VERSION 5.8 ;
BUSBITCHARS "[]" ;
DIVIDERCHAR "/" ;
UNITS
    DATABASE MICRONS 1000 ;
END UNITS

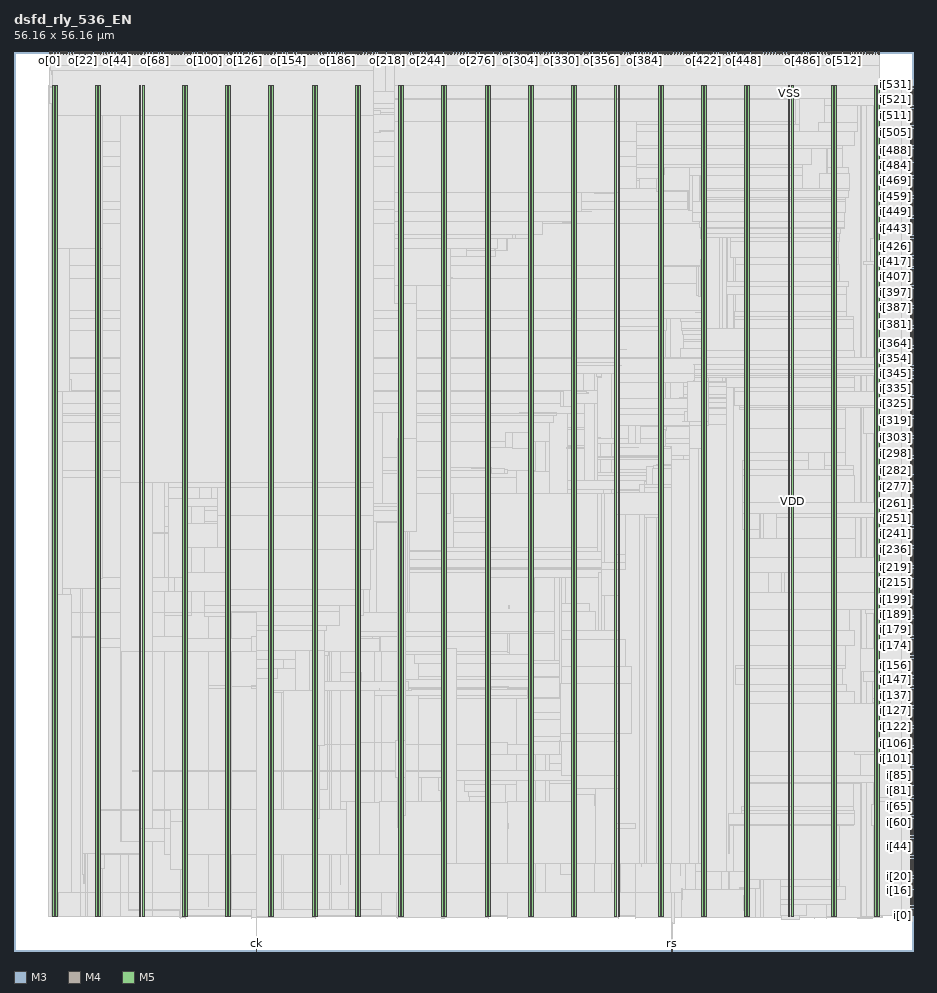
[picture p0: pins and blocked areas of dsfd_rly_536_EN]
MACRO dsfd_rly_536_EN
  FOREIGN dsfd_rly_536_EN 0 0 ;
  CLASS BLOCK ;
  SIZE 56.16 BY 56.16 ;
  PIN ck
    DIRECTION INPUT ;
    USE SIGNAL ;
    PORT
      LAYER M3 ;
        RECT  15.12 0 15.138 0.144 ;
    END
  END ck
  PIN i[0]
    DIRECTION INPUT ;
    USE SIGNAL ;
    PORT
      LAYER M4 ;
        RECT  55.968 2.208 56.16 2.232 ;
    END
  END i[0]
  PIN i[100]
    DIRECTION INPUT ;
    USE SIGNAL ;
    PORT
      LAYER M4 ;
        RECT  55.968 11.904 56.16 11.928 ;
    END
  END i[100]
  PIN i[101]
    DIRECTION INPUT ;
    USE SIGNAL ;
    PORT
      LAYER M4 ;
        RECT  55.968 12 56.16 12.024 ;
    END
  END i[101]
  PIN i[102]
    DIRECTION INPUT ;
    USE SIGNAL ;
    PORT
      LAYER M4 ;
        RECT  55.968 12.096 56.16 12.12 ;
    END
  END i[102]
  PIN i[103]
    DIRECTION INPUT ;
    USE SIGNAL ;
    PORT
      LAYER M4 ;
        RECT  55.968 12.192 56.16 12.216 ;
    END
  END i[103]
  PIN i[104]
    DIRECTION INPUT ;
    USE SIGNAL ;
    PORT
      LAYER M4 ;
        RECT  55.968 12.288 56.16 12.312 ;
    END
  END i[104]
  PIN i[105]
    DIRECTION INPUT ;
    USE SIGNAL ;
    PORT
      LAYER M4 ;
        RECT  55.968 12.384 56.16 12.408 ;
    END
  END i[105]
  PIN i[106]
    DIRECTION INPUT ;
    USE SIGNAL ;
    PORT
      LAYER M4 ;
        RECT  55.968 12.48 56.16 12.504 ;
    END
  END i[106]
  PIN i[107]
    DIRECTION INPUT ;
    USE SIGNAL ;
    PORT
      LAYER M4 ;
        RECT  55.968 12.576 56.16 12.6 ;
    END
  END i[107]
  PIN i[108]
    DIRECTION INPUT ;
    USE SIGNAL ;
    PORT
      LAYER M4 ;
        RECT  55.968 12.672 56.16 12.696 ;
    END
  END i[108]
  PIN i[109]
    DIRECTION INPUT ;
    USE SIGNAL ;
    PORT
      LAYER M4 ;
        RECT  55.968 12.768 56.16 12.792 ;
    END
  END i[109]
  PIN i[10]
    DIRECTION INPUT ;
    USE SIGNAL ;
    PORT
      LAYER M4 ;
        RECT  55.968 3.168 56.16 3.192 ;
    END
  END i[10]
  PIN i[110]
    DIRECTION INPUT ;
    USE SIGNAL ;
    PORT
      LAYER M4 ;
        RECT  55.968 12.864 56.16 12.888 ;
    END
  END i[110]
  PIN i[111]
    DIRECTION INPUT ;
    USE SIGNAL ;
    PORT
      LAYER M4 ;
        RECT  55.968 12.96 56.16 12.984 ;
    END
  END i[111]
  PIN i[112]
    DIRECTION INPUT ;
    USE SIGNAL ;
    PORT
      LAYER M4 ;
        RECT  55.968 13.056 56.16 13.08 ;
    END
  END i[112]
  PIN i[113]
    DIRECTION INPUT ;
    USE SIGNAL ;
    PORT
      LAYER M4 ;
        RECT  55.968 13.152 56.16 13.176 ;
    END
  END i[113]
  PIN i[114]
    DIRECTION INPUT ;
    USE SIGNAL ;
    PORT
      LAYER M4 ;
        RECT  55.968 13.248 56.16 13.272 ;
    END
  END i[114]
  PIN i[115]
    DIRECTION INPUT ;
    USE SIGNAL ;
    PORT
      LAYER M4 ;
        RECT  55.968 13.344 56.16 13.368 ;
    END
  END i[115]
  PIN i[116]
    DIRECTION INPUT ;
    USE SIGNAL ;
    PORT
      LAYER M4 ;
        RECT  55.968 13.44 56.16 13.464 ;
    END
  END i[116]
  PIN i[117]
    DIRECTION INPUT ;
    USE SIGNAL ;
    PORT
      LAYER M4 ;
        RECT  55.968 13.536 56.16 13.56 ;
    END
  END i[117]
  PIN i[118]
    DIRECTION INPUT ;
    USE SIGNAL ;
    PORT
      LAYER M4 ;
        RECT  55.968 13.632 56.16 13.656 ;
    END
  END i[118]
  PIN i[119]
    DIRECTION INPUT ;
    USE SIGNAL ;
    PORT
      LAYER M4 ;
        RECT  55.968 13.728 56.16 13.752 ;
    END
  END i[119]
  PIN i[11]
    DIRECTION INPUT ;
    USE SIGNAL ;
    PORT
      LAYER M4 ;
        RECT  55.968 3.264 56.16 3.288 ;
    END
  END i[11]
  PIN i[120]
    DIRECTION INPUT ;
    USE SIGNAL ;
    PORT
      LAYER M4 ;
        RECT  55.968 13.824 56.16 13.848 ;
    END
  END i[120]
  PIN i[121]
    DIRECTION INPUT ;
    USE SIGNAL ;
    PORT
      LAYER M4 ;
        RECT  55.968 13.92 56.16 13.944 ;
    END
  END i[121]
  PIN i[122]
    DIRECTION INPUT ;
    USE SIGNAL ;
    PORT
      LAYER M4 ;
        RECT  55.968 14.016 56.16 14.04 ;
    END
  END i[122]
  PIN i[123]
    DIRECTION INPUT ;
    USE SIGNAL ;
    PORT
      LAYER M4 ;
        RECT  55.968 14.112 56.16 14.136 ;
    END
  END i[123]
  PIN i[124]
    DIRECTION INPUT ;
    USE SIGNAL ;
    PORT
      LAYER M4 ;
        RECT  55.968 14.208 56.16 14.232 ;
    END
  END i[124]
  PIN i[125]
    DIRECTION INPUT ;
    USE SIGNAL ;
    PORT
      LAYER M4 ;
        RECT  55.968 14.304 56.16 14.328 ;
    END
  END i[125]
  PIN i[126]
    DIRECTION INPUT ;
    USE SIGNAL ;
    PORT
      LAYER M4 ;
        RECT  55.968 14.4 56.16 14.424 ;
    END
  END i[126]
  PIN i[127]
    DIRECTION INPUT ;
    USE SIGNAL ;
    PORT
      LAYER M4 ;
        RECT  55.968 14.496 56.16 14.52 ;
    END
  END i[127]
  PIN i[128]
    DIRECTION INPUT ;
    USE SIGNAL ;
    PORT
      LAYER M4 ;
        RECT  55.968 14.592 56.16 14.616 ;
    END
  END i[128]
  PIN i[129]
    DIRECTION INPUT ;
    USE SIGNAL ;
    PORT
      LAYER M4 ;
        RECT  55.968 14.688 56.16 14.712 ;
    END
  END i[129]
  PIN i[12]
    DIRECTION INPUT ;
    USE SIGNAL ;
    PORT
      LAYER M4 ;
        RECT  55.968 3.36 56.16 3.384 ;
    END
  END i[12]
  PIN i[130]
    DIRECTION INPUT ;
    USE SIGNAL ;
    PORT
      LAYER M4 ;
        RECT  55.968 14.784 56.16 14.808 ;
    END
  END i[130]
  PIN i[131]
    DIRECTION INPUT ;
    USE SIGNAL ;
    PORT
      LAYER M4 ;
        RECT  55.968 14.88 56.16 14.904 ;
    END
  END i[131]
  PIN i[132]
    DIRECTION INPUT ;
    USE SIGNAL ;
    PORT
      LAYER M4 ;
        RECT  55.968 14.976 56.16 15 ;
    END
  END i[132]
  PIN i[133]
    DIRECTION INPUT ;
    USE SIGNAL ;
    PORT
      LAYER M4 ;
        RECT  55.968 15.072 56.16 15.096 ;
    END
  END i[133]
  PIN i[134]
    DIRECTION INPUT ;
    USE SIGNAL ;
    PORT
      LAYER M4 ;
        RECT  55.968 15.168 56.16 15.192 ;
    END
  END i[134]
  PIN i[135]
    DIRECTION INPUT ;
    USE SIGNAL ;
    PORT
      LAYER M4 ;
        RECT  55.968 15.264 56.16 15.288 ;
    END
  END i[135]
  PIN i[136]
    DIRECTION INPUT ;
    USE SIGNAL ;
    PORT
      LAYER M4 ;
        RECT  55.968 15.36 56.16 15.384 ;
    END
  END i[136]
  PIN i[137]
    DIRECTION INPUT ;
    USE SIGNAL ;
    PORT
      LAYER M4 ;
        RECT  55.968 15.456 56.16 15.48 ;
    END
  END i[137]
  PIN i[138]
    DIRECTION INPUT ;
    USE SIGNAL ;
    PORT
      LAYER M4 ;
        RECT  55.968 15.552 56.16 15.576 ;
    END
  END i[138]
  PIN i[139]
    DIRECTION INPUT ;
    USE SIGNAL ;
    PORT
      LAYER M4 ;
        RECT  55.968 15.648 56.16 15.672 ;
    END
  END i[139]
  PIN i[13]
    DIRECTION INPUT ;
    USE SIGNAL ;
    PORT
      LAYER M4 ;
        RECT  55.968 3.456 56.16 3.48 ;
    END
  END i[13]
  PIN i[140]
    DIRECTION INPUT ;
    USE SIGNAL ;
    PORT
      LAYER M4 ;
        RECT  55.968 15.744 56.16 15.768 ;
    END
  END i[140]
  PIN i[141]
    DIRECTION INPUT ;
    USE SIGNAL ;
    PORT
      LAYER M4 ;
        RECT  55.968 15.84 56.16 15.864 ;
    END
  END i[141]
  PIN i[142]
    DIRECTION INPUT ;
    USE SIGNAL ;
    PORT
      LAYER M4 ;
        RECT  55.968 15.936 56.16 15.96 ;
    END
  END i[142]
  PIN i[143]
    DIRECTION INPUT ;
    USE SIGNAL ;
    PORT
      LAYER M4 ;
        RECT  55.968 16.032 56.16 16.056 ;
    END
  END i[143]
  PIN i[144]
    DIRECTION INPUT ;
    USE SIGNAL ;
    PORT
      LAYER M4 ;
        RECT  55.968 16.128 56.16 16.152 ;
    END
  END i[144]
  PIN i[145]
    DIRECTION INPUT ;
    USE SIGNAL ;
    PORT
      LAYER M4 ;
        RECT  55.968 16.224 56.16 16.248 ;
    END
  END i[145]
  PIN i[146]
    DIRECTION INPUT ;
    USE SIGNAL ;
    PORT
      LAYER M4 ;
        RECT  55.968 16.32 56.16 16.344 ;
    END
  END i[146]
  PIN i[147]
    DIRECTION INPUT ;
    USE SIGNAL ;
    PORT
      LAYER M4 ;
        RECT  55.968 16.416 56.16 16.44 ;
    END
  END i[147]
  PIN i[148]
    DIRECTION INPUT ;
    USE SIGNAL ;
    PORT
      LAYER M4 ;
        RECT  55.968 16.512 56.16 16.536 ;
    END
  END i[148]
  PIN i[149]
    DIRECTION INPUT ;
    USE SIGNAL ;
    PORT
      LAYER M4 ;
        RECT  55.968 16.608 56.16 16.632 ;
    END
  END i[149]
  PIN i[14]
    DIRECTION INPUT ;
    USE SIGNAL ;
    PORT
      LAYER M4 ;
        RECT  55.968 3.552 56.16 3.576 ;
    END
  END i[14]
  PIN i[150]
    DIRECTION INPUT ;
    USE SIGNAL ;
    PORT
      LAYER M4 ;
        RECT  55.968 16.704 56.16 16.728 ;
    END
  END i[150]
  PIN i[151]
    DIRECTION INPUT ;
    USE SIGNAL ;
    PORT
      LAYER M4 ;
        RECT  55.968 16.848 56.16 16.872 ;
    END
  END i[151]
  PIN i[152]
    DIRECTION INPUT ;
    USE SIGNAL ;
    PORT
      LAYER M4 ;
        RECT  55.968 16.944 56.16 16.968 ;
    END
  END i[152]
  PIN i[153]
    DIRECTION INPUT ;
    USE SIGNAL ;
    PORT
      LAYER M4 ;
        RECT  55.968 17.04 56.16 17.064 ;
    END
  END i[153]
  PIN i[154]
    DIRECTION INPUT ;
    USE SIGNAL ;
    PORT
      LAYER M4 ;
        RECT  55.968 17.136 56.16 17.16 ;
    END
  END i[154]
  PIN i[155]
    DIRECTION INPUT ;
    USE SIGNAL ;
    PORT
      LAYER M4 ;
        RECT  55.968 17.232 56.16 17.256 ;
    END
  END i[155]
  PIN i[156]
    DIRECTION INPUT ;
    USE SIGNAL ;
    PORT
      LAYER M4 ;
        RECT  55.968 17.328 56.16 17.352 ;
    END
  END i[156]
  PIN i[157]
    DIRECTION INPUT ;
    USE SIGNAL ;
    PORT
      LAYER M4 ;
        RECT  55.968 17.424 56.16 17.448 ;
    END
  END i[157]
  PIN i[158]
    DIRECTION INPUT ;
    USE SIGNAL ;
    PORT
      LAYER M4 ;
        RECT  55.968 17.52 56.16 17.544 ;
    END
  END i[158]
  PIN i[159]
    DIRECTION INPUT ;
    USE SIGNAL ;
    PORT
      LAYER M4 ;
        RECT  55.968 17.616 56.16 17.64 ;
    END
  END i[159]
  PIN i[15]
    DIRECTION INPUT ;
    USE SIGNAL ;
    PORT
      LAYER M4 ;
        RECT  55.968 3.648 56.16 3.672 ;
    END
  END i[15]
  PIN i[160]
    DIRECTION INPUT ;
    USE SIGNAL ;
    PORT
      LAYER M4 ;
        RECT  55.968 17.712 56.16 17.736 ;
    END
  END i[160]
  PIN i[161]
    DIRECTION INPUT ;
    USE SIGNAL ;
    PORT
      LAYER M4 ;
        RECT  55.968 17.808 56.16 17.832 ;
    END
  END i[161]
  PIN i[162]
    DIRECTION INPUT ;
    USE SIGNAL ;
    PORT
      LAYER M4 ;
        RECT  55.968 17.904 56.16 17.928 ;
    END
  END i[162]
  PIN i[163]
    DIRECTION INPUT ;
    USE SIGNAL ;
    PORT
      LAYER M4 ;
        RECT  55.968 18 56.16 18.024 ;
    END
  END i[163]
  PIN i[164]
    DIRECTION INPUT ;
    USE SIGNAL ;
    PORT
      LAYER M4 ;
        RECT  55.968 18.096 56.16 18.12 ;
    END
  END i[164]
  PIN i[165]
    DIRECTION INPUT ;
    USE SIGNAL ;
    PORT
      LAYER M4 ;
        RECT  55.968 18.192 56.16 18.216 ;
    END
  END i[165]
  PIN i[166]
    DIRECTION INPUT ;
    USE SIGNAL ;
    PORT
      LAYER M4 ;
        RECT  55.968 18.288 56.16 18.312 ;
    END
  END i[166]
  PIN i[167]
    DIRECTION INPUT ;
    USE SIGNAL ;
    PORT
      LAYER M4 ;
        RECT  55.968 18.384 56.16 18.408 ;
    END
  END i[167]
  PIN i[168]
    DIRECTION INPUT ;
    USE SIGNAL ;
    PORT
      LAYER M4 ;
        RECT  55.968 18.48 56.16 18.504 ;
    END
  END i[168]
  PIN i[169]
    DIRECTION INPUT ;
    USE SIGNAL ;
    PORT
      LAYER M4 ;
        RECT  55.968 18.576 56.16 18.6 ;
    END
  END i[169]
  PIN i[16]
    DIRECTION INPUT ;
    USE SIGNAL ;
    PORT
      LAYER M4 ;
        RECT  55.968 3.744 56.16 3.768 ;
    END
  END i[16]
  PIN i[170]
    DIRECTION INPUT ;
    USE SIGNAL ;
    PORT
      LAYER M4 ;
        RECT  55.968 18.672 56.16 18.696 ;
    END
  END i[170]
  PIN i[171]
    DIRECTION INPUT ;
    USE SIGNAL ;
    PORT
      LAYER M4 ;
        RECT  55.968 18.768 56.16 18.792 ;
    END
  END i[171]
  PIN i[172]
    DIRECTION INPUT ;
    USE SIGNAL ;
    PORT
      LAYER M4 ;
        RECT  55.968 18.864 56.16 18.888 ;
    END
  END i[172]
  PIN i[173]
    DIRECTION INPUT ;
    USE SIGNAL ;
    PORT
      LAYER M4 ;
        RECT  55.968 18.96 56.16 18.984 ;
    END
  END i[173]
  PIN i[174]
    DIRECTION INPUT ;
    USE SIGNAL ;
    PORT
      LAYER M4 ;
        RECT  55.968 19.056 56.16 19.08 ;
    END
  END i[174]
  PIN i[175]
    DIRECTION INPUT ;
    USE SIGNAL ;
    PORT
      LAYER M4 ;
        RECT  55.968 19.152 56.16 19.176 ;
    END
  END i[175]
  PIN i[176]
    DIRECTION INPUT ;
    USE SIGNAL ;
    PORT
      LAYER M4 ;
        RECT  55.968 19.248 56.16 19.272 ;
    END
  END i[176]
  PIN i[177]
    DIRECTION INPUT ;
    USE SIGNAL ;
    PORT
      LAYER M4 ;
        RECT  55.968 19.344 56.16 19.368 ;
    END
  END i[177]
  PIN i[178]
    DIRECTION INPUT ;
    USE SIGNAL ;
    PORT
      LAYER M4 ;
        RECT  55.968 19.44 56.16 19.464 ;
    END
  END i[178]
  PIN i[179]
    DIRECTION INPUT ;
    USE SIGNAL ;
    PORT
      LAYER M4 ;
        RECT  55.968 19.536 56.16 19.56 ;
    END
  END i[179]
  PIN i[17]
    DIRECTION INPUT ;
    USE SIGNAL ;
    PORT
      LAYER M4 ;
        RECT  55.968 3.888 56.16 3.912 ;
    END
  END i[17]
  PIN i[180]
    DIRECTION INPUT ;
    USE SIGNAL ;
    PORT
      LAYER M4 ;
        RECT  55.968 19.632 56.16 19.656 ;
    END
  END i[180]
  PIN i[181]
    DIRECTION INPUT ;
    USE SIGNAL ;
    PORT
      LAYER M4 ;
        RECT  55.968 19.728 56.16 19.752 ;
    END
  END i[181]
  PIN i[182]
    DIRECTION INPUT ;
    USE SIGNAL ;
    PORT
      LAYER M4 ;
        RECT  55.968 19.824 56.16 19.848 ;
    END
  END i[182]
  PIN i[183]
    DIRECTION INPUT ;
    USE SIGNAL ;
    PORT
      LAYER M4 ;
        RECT  55.968 19.92 56.16 19.944 ;
    END
  END i[183]
  PIN i[184]
    DIRECTION INPUT ;
    USE SIGNAL ;
    PORT
      LAYER M4 ;
        RECT  55.968 20.016 56.16 20.04 ;
    END
  END i[184]
  PIN i[185]
    DIRECTION INPUT ;
    USE SIGNAL ;
    PORT
      LAYER M4 ;
        RECT  55.968 20.112 56.16 20.136 ;
    END
  END i[185]
  PIN i[186]
    DIRECTION INPUT ;
    USE SIGNAL ;
    PORT
      LAYER M4 ;
        RECT  55.968 20.208 56.16 20.232 ;
    END
  END i[186]
  PIN i[187]
    DIRECTION INPUT ;
    USE SIGNAL ;
    PORT
      LAYER M4 ;
        RECT  55.968 20.304 56.16 20.328 ;
    END
  END i[187]
  PIN i[188]
    DIRECTION INPUT ;
    USE SIGNAL ;
    PORT
      LAYER M4 ;
        RECT  55.968 20.4 56.16 20.424 ;
    END
  END i[188]
  PIN i[189]
    DIRECTION INPUT ;
    USE SIGNAL ;
    PORT
      LAYER M4 ;
        RECT  55.968 20.496 56.16 20.52 ;
    END
  END i[189]
  PIN i[18]
    DIRECTION INPUT ;
    USE SIGNAL ;
    PORT
      LAYER M4 ;
        RECT  55.968 3.984 56.16 4.008 ;
    END
  END i[18]
  PIN i[190]
    DIRECTION INPUT ;
    USE SIGNAL ;
    PORT
      LAYER M4 ;
        RECT  55.968 20.592 56.16 20.616 ;
    END
  END i[190]
  PIN i[191]
    DIRECTION INPUT ;
    USE SIGNAL ;
    PORT
      LAYER M4 ;
        RECT  55.968 20.688 56.16 20.712 ;
    END
  END i[191]
  PIN i[192]
    DIRECTION INPUT ;
    USE SIGNAL ;
    PORT
      LAYER M4 ;
        RECT  55.968 20.784 56.16 20.808 ;
    END
  END i[192]
  PIN i[193]
    DIRECTION INPUT ;
    USE SIGNAL ;
    PORT
      LAYER M4 ;
        RECT  55.968 20.88 56.16 20.904 ;
    END
  END i[193]
  PIN i[194]
    DIRECTION INPUT ;
    USE SIGNAL ;
    PORT
      LAYER M4 ;
        RECT  55.968 20.976 56.16 21 ;
    END
  END i[194]
  PIN i[195]
    DIRECTION INPUT ;
    USE SIGNAL ;
    PORT
      LAYER M4 ;
        RECT  55.968 21.072 56.16 21.096 ;
    END
  END i[195]
  PIN i[196]
    DIRECTION INPUT ;
    USE SIGNAL ;
    PORT
      LAYER M4 ;
        RECT  55.968 21.168 56.16 21.192 ;
    END
  END i[196]
  PIN i[197]
    DIRECTION INPUT ;
    USE SIGNAL ;
    PORT
      LAYER M4 ;
        RECT  55.968 21.264 56.16 21.288 ;
    END
  END i[197]
  PIN i[198]
    DIRECTION INPUT ;
    USE SIGNAL ;
    PORT
      LAYER M4 ;
        RECT  55.968 21.36 56.16 21.384 ;
    END
  END i[198]
  PIN i[199]
    DIRECTION INPUT ;
    USE SIGNAL ;
    PORT
      LAYER M4 ;
        RECT  55.968 21.456 56.16 21.48 ;
    END
  END i[199]
  PIN i[19]
    DIRECTION INPUT ;
    USE SIGNAL ;
    PORT
      LAYER M4 ;
        RECT  55.968 4.08 56.16 4.104 ;
    END
  END i[19]
  PIN i[1]
    DIRECTION INPUT ;
    USE SIGNAL ;
    PORT
      LAYER M4 ;
        RECT  55.968 2.304 56.16 2.328 ;
    END
  END i[1]
  PIN i[200]
    DIRECTION INPUT ;
    USE SIGNAL ;
    PORT
      LAYER M4 ;
        RECT  55.968 21.552 56.16 21.576 ;
    END
  END i[200]
  PIN i[201]
    DIRECTION INPUT ;
    USE SIGNAL ;
    PORT
      LAYER M4 ;
        RECT  55.968 21.648 56.16 21.672 ;
    END
  END i[201]
  PIN i[202]
    DIRECTION INPUT ;
    USE SIGNAL ;
    PORT
      LAYER M4 ;
        RECT  55.968 21.744 56.16 21.768 ;
    END
  END i[202]
  PIN i[203]
    DIRECTION INPUT ;
    USE SIGNAL ;
    PORT
      LAYER M4 ;
        RECT  55.968 21.84 56.16 21.864 ;
    END
  END i[203]
  PIN i[204]
    DIRECTION INPUT ;
    USE SIGNAL ;
    PORT
      LAYER M4 ;
        RECT  55.968 21.936 56.16 21.96 ;
    END
  END i[204]
  PIN i[205]
    DIRECTION INPUT ;
    USE SIGNAL ;
    PORT
      LAYER M4 ;
        RECT  55.968 22.032 56.16 22.056 ;
    END
  END i[205]
  PIN i[206]
    DIRECTION INPUT ;
    USE SIGNAL ;
    PORT
      LAYER M4 ;
        RECT  55.968 22.128 56.16 22.152 ;
    END
  END i[206]
  PIN i[207]
    DIRECTION INPUT ;
    USE SIGNAL ;
    PORT
      LAYER M4 ;
        RECT  55.968 22.224 56.16 22.248 ;
    END
  END i[207]
  PIN i[208]
    DIRECTION INPUT ;
    USE SIGNAL ;
    PORT
      LAYER M4 ;
        RECT  55.968 22.32 56.16 22.344 ;
    END
  END i[208]
  PIN i[209]
    DIRECTION INPUT ;
    USE SIGNAL ;
    PORT
      LAYER M4 ;
        RECT  55.968 22.416 56.16 22.44 ;
    END
  END i[209]
  PIN i[20]
    DIRECTION INPUT ;
    USE SIGNAL ;
    PORT
      LAYER M4 ;
        RECT  55.968 4.176 56.16 4.2 ;
    END
  END i[20]
  PIN i[210]
    DIRECTION INPUT ;
    USE SIGNAL ;
    PORT
      LAYER M4 ;
        RECT  55.968 22.512 56.16 22.536 ;
    END
  END i[210]
  PIN i[211]
    DIRECTION INPUT ;
    USE SIGNAL ;
    PORT
      LAYER M4 ;
        RECT  55.968 22.608 56.16 22.632 ;
    END
  END i[211]
  PIN i[212]
    DIRECTION INPUT ;
    USE SIGNAL ;
    PORT
      LAYER M4 ;
        RECT  55.968 22.704 56.16 22.728 ;
    END
  END i[212]
  PIN i[213]
    DIRECTION INPUT ;
    USE SIGNAL ;
    PORT
      LAYER M4 ;
        RECT  55.968 22.8 56.16 22.824 ;
    END
  END i[213]
  PIN i[214]
    DIRECTION INPUT ;
    USE SIGNAL ;
    PORT
      LAYER M4 ;
        RECT  55.968 22.896 56.16 22.92 ;
    END
  END i[214]
  PIN i[215]
    DIRECTION INPUT ;
    USE SIGNAL ;
    PORT
      LAYER M4 ;
        RECT  55.968 22.992 56.16 23.016 ;
    END
  END i[215]
  PIN i[216]
    DIRECTION INPUT ;
    USE SIGNAL ;
    PORT
      LAYER M4 ;
        RECT  55.968 23.088 56.16 23.112 ;
    END
  END i[216]
  PIN i[217]
    DIRECTION INPUT ;
    USE SIGNAL ;
    PORT
      LAYER M4 ;
        RECT  55.968 23.184 56.16 23.208 ;
    END
  END i[217]
  PIN i[218]
    DIRECTION INPUT ;
    USE SIGNAL ;
    PORT
      LAYER M4 ;
        RECT  55.968 23.328 56.16 23.352 ;
    END
  END i[218]
  PIN i[219]
    DIRECTION INPUT ;
    USE SIGNAL ;
    PORT
      LAYER M4 ;
        RECT  55.968 23.424 56.16 23.448 ;
    END
  END i[219]
  PIN i[21]
    DIRECTION INPUT ;
    USE SIGNAL ;
    PORT
      LAYER M4 ;
        RECT  55.968 4.272 56.16 4.296 ;
    END
  END i[21]
  PIN i[220]
    DIRECTION INPUT ;
    USE SIGNAL ;
    PORT
      LAYER M4 ;
        RECT  55.968 23.52 56.16 23.544 ;
    END
  END i[220]
  PIN i[221]
    DIRECTION INPUT ;
    USE SIGNAL ;
    PORT
      LAYER M4 ;
        RECT  55.968 23.616 56.16 23.64 ;
    END
  END i[221]
  PIN i[222]
    DIRECTION INPUT ;
    USE SIGNAL ;
    PORT
      LAYER M4 ;
        RECT  55.968 23.712 56.16 23.736 ;
    END
  END i[222]
  PIN i[223]
    DIRECTION INPUT ;
    USE SIGNAL ;
    PORT
      LAYER M4 ;
        RECT  55.968 23.808 56.16 23.832 ;
    END
  END i[223]
  PIN i[224]
    DIRECTION INPUT ;
    USE SIGNAL ;
    PORT
      LAYER M4 ;
        RECT  55.968 23.904 56.16 23.928 ;
    END
  END i[224]
  PIN i[225]
    DIRECTION INPUT ;
    USE SIGNAL ;
    PORT
      LAYER M4 ;
        RECT  55.968 24 56.16 24.024 ;
    END
  END i[225]
  PIN i[226]
    DIRECTION INPUT ;
    USE SIGNAL ;
    PORT
      LAYER M4 ;
        RECT  55.968 24.096 56.16 24.12 ;
    END
  END i[226]
  PIN i[227]
    DIRECTION INPUT ;
    USE SIGNAL ;
    PORT
      LAYER M4 ;
        RECT  55.968 24.192 56.16 24.216 ;
    END
  END i[227]
  PIN i[228]
    DIRECTION INPUT ;
    USE SIGNAL ;
    PORT
      LAYER M4 ;
        RECT  55.968 24.288 56.16 24.312 ;
    END
  END i[228]
  PIN i[229]
    DIRECTION INPUT ;
    USE SIGNAL ;
    PORT
      LAYER M4 ;
        RECT  55.968 24.384 56.16 24.408 ;
    END
  END i[229]
  PIN i[22]
    DIRECTION INPUT ;
    USE SIGNAL ;
    PORT
      LAYER M4 ;
        RECT  55.968 4.368 56.16 4.392 ;
    END
  END i[22]
  PIN i[230]
    DIRECTION INPUT ;
    USE SIGNAL ;
    PORT
      LAYER M4 ;
        RECT  55.968 24.48 56.16 24.504 ;
    END
  END i[230]
  PIN i[231]
    DIRECTION INPUT ;
    USE SIGNAL ;
    PORT
      LAYER M4 ;
        RECT  55.968 24.576 56.16 24.6 ;
    END
  END i[231]
  PIN i[232]
    DIRECTION INPUT ;
    USE SIGNAL ;
    PORT
      LAYER M4 ;
        RECT  55.968 24.672 56.16 24.696 ;
    END
  END i[232]
  PIN i[233]
    DIRECTION INPUT ;
    USE SIGNAL ;
    PORT
      LAYER M4 ;
        RECT  55.968 24.768 56.16 24.792 ;
    END
  END i[233]
  PIN i[234]
    DIRECTION INPUT ;
    USE SIGNAL ;
    PORT
      LAYER M4 ;
        RECT  55.968 24.864 56.16 24.888 ;
    END
  END i[234]
  PIN i[235]
    DIRECTION INPUT ;
    USE SIGNAL ;
    PORT
      LAYER M4 ;
        RECT  55.968 24.96 56.16 24.984 ;
    END
  END i[235]
  PIN i[236]
    DIRECTION INPUT ;
    USE SIGNAL ;
    PORT
      LAYER M4 ;
        RECT  55.968 25.056 56.16 25.08 ;
    END
  END i[236]
  PIN i[237]
    DIRECTION INPUT ;
    USE SIGNAL ;
    PORT
      LAYER M4 ;
        RECT  55.968 25.152 56.16 25.176 ;
    END
  END i[237]
  PIN i[238]
    DIRECTION INPUT ;
    USE SIGNAL ;
    PORT
      LAYER M4 ;
        RECT  55.968 25.248 56.16 25.272 ;
    END
  END i[238]
  PIN i[239]
    DIRECTION INPUT ;
    USE SIGNAL ;
    PORT
      LAYER M4 ;
        RECT  55.968 25.344 56.16 25.368 ;
    END
  END i[239]
  PIN i[23]
    DIRECTION INPUT ;
    USE SIGNAL ;
    PORT
      LAYER M4 ;
        RECT  55.968 4.464 56.16 4.488 ;
    END
  END i[23]
  PIN i[240]
    DIRECTION INPUT ;
    USE SIGNAL ;
    PORT
      LAYER M4 ;
        RECT  55.968 25.44 56.16 25.464 ;
    END
  END i[240]
  PIN i[241]
    DIRECTION INPUT ;
    USE SIGNAL ;
    PORT
      LAYER M4 ;
        RECT  55.968 25.536 56.16 25.56 ;
    END
  END i[241]
  PIN i[242]
    DIRECTION INPUT ;
    USE SIGNAL ;
    PORT
      LAYER M4 ;
        RECT  55.968 25.632 56.16 25.656 ;
    END
  END i[242]
  PIN i[243]
    DIRECTION INPUT ;
    USE SIGNAL ;
    PORT
      LAYER M4 ;
        RECT  55.968 25.728 56.16 25.752 ;
    END
  END i[243]
  PIN i[244]
    DIRECTION INPUT ;
    USE SIGNAL ;
    PORT
      LAYER M4 ;
        RECT  55.968 25.824 56.16 25.848 ;
    END
  END i[244]
  PIN i[245]
    DIRECTION INPUT ;
    USE SIGNAL ;
    PORT
      LAYER M4 ;
        RECT  55.968 25.92 56.16 25.944 ;
    END
  END i[245]
  PIN i[246]
    DIRECTION INPUT ;
    USE SIGNAL ;
    PORT
      LAYER M4 ;
        RECT  55.968 26.016 56.16 26.04 ;
    END
  END i[246]
  PIN i[247]
    DIRECTION INPUT ;
    USE SIGNAL ;
    PORT
      LAYER M4 ;
        RECT  55.968 26.112 56.16 26.136 ;
    END
  END i[247]
  PIN i[248]
    DIRECTION INPUT ;
    USE SIGNAL ;
    PORT
      LAYER M4 ;
        RECT  55.968 26.208 56.16 26.232 ;
    END
  END i[248]
  PIN i[249]
    DIRECTION INPUT ;
    USE SIGNAL ;
    PORT
      LAYER M4 ;
        RECT  55.968 26.304 56.16 26.328 ;
    END
  END i[249]
  PIN i[24]
    DIRECTION INPUT ;
    USE SIGNAL ;
    PORT
      LAYER M4 ;
        RECT  55.968 4.56 56.16 4.584 ;
    END
  END i[24]
  PIN i[250]
    DIRECTION INPUT ;
    USE SIGNAL ;
    PORT
      LAYER M4 ;
        RECT  55.968 26.4 56.16 26.424 ;
    END
  END i[250]
  PIN i[251]
    DIRECTION INPUT ;
    USE SIGNAL ;
    PORT
      LAYER M4 ;
        RECT  55.968 26.496 56.16 26.52 ;
    END
  END i[251]
  PIN i[252]
    DIRECTION INPUT ;
    USE SIGNAL ;
    PORT
      LAYER M4 ;
        RECT  55.968 26.592 56.16 26.616 ;
    END
  END i[252]
  PIN i[253]
    DIRECTION INPUT ;
    USE SIGNAL ;
    PORT
      LAYER M4 ;
        RECT  55.968 26.688 56.16 26.712 ;
    END
  END i[253]
  PIN i[254]
    DIRECTION INPUT ;
    USE SIGNAL ;
    PORT
      LAYER M4 ;
        RECT  55.968 26.784 56.16 26.808 ;
    END
  END i[254]
  PIN i[255]
    DIRECTION INPUT ;
    USE SIGNAL ;
    PORT
      LAYER M4 ;
        RECT  55.968 26.88 56.16 26.904 ;
    END
  END i[255]
  PIN i[256]
    DIRECTION INPUT ;
    USE SIGNAL ;
    PORT
      LAYER M4 ;
        RECT  55.968 26.976 56.16 27 ;
    END
  END i[256]
  PIN i[257]
    DIRECTION INPUT ;
    USE SIGNAL ;
    PORT
      LAYER M4 ;
        RECT  55.968 27.072 56.16 27.096 ;
    END
  END i[257]
  PIN i[258]
    DIRECTION INPUT ;
    USE SIGNAL ;
    PORT
      LAYER M4 ;
        RECT  55.968 27.168 56.16 27.192 ;
    END
  END i[258]
  PIN i[259]
    DIRECTION INPUT ;
    USE SIGNAL ;
    PORT
      LAYER M4 ;
        RECT  55.968 27.264 56.16 27.288 ;
    END
  END i[259]
  PIN i[25]
    DIRECTION INPUT ;
    USE SIGNAL ;
    PORT
      LAYER M4 ;
        RECT  55.968 4.656 56.16 4.68 ;
    END
  END i[25]
  PIN i[260]
    DIRECTION INPUT ;
    USE SIGNAL ;
    PORT
      LAYER M4 ;
        RECT  55.968 27.36 56.16 27.384 ;
    END
  END i[260]
  PIN i[261]
    DIRECTION INPUT ;
    USE SIGNAL ;
    PORT
      LAYER M4 ;
        RECT  55.968 27.456 56.16 27.48 ;
    END
  END i[261]
  PIN i[262]
    DIRECTION INPUT ;
    USE SIGNAL ;
    PORT
      LAYER M4 ;
        RECT  55.968 27.552 56.16 27.576 ;
    END
  END i[262]
  PIN i[263]
    DIRECTION INPUT ;
    USE SIGNAL ;
    PORT
      LAYER M4 ;
        RECT  55.968 27.648 56.16 27.672 ;
    END
  END i[263]
  PIN i[264]
    DIRECTION INPUT ;
    USE SIGNAL ;
    PORT
      LAYER M4 ;
        RECT  55.968 27.744 56.16 27.768 ;
    END
  END i[264]
  PIN i[265]
    DIRECTION INPUT ;
    USE SIGNAL ;
    PORT
      LAYER M4 ;
        RECT  55.968 27.84 56.16 27.864 ;
    END
  END i[265]
  PIN i[266]
    DIRECTION INPUT ;
    USE SIGNAL ;
    PORT
      LAYER M4 ;
        RECT  55.968 27.936 56.16 27.96 ;
    END
  END i[266]
  PIN i[267]
    DIRECTION INPUT ;
    USE SIGNAL ;
    PORT
      LAYER M4 ;
        RECT  55.968 28.032 56.16 28.056 ;
    END
  END i[267]
  PIN i[268]
    DIRECTION INPUT ;
    USE SIGNAL ;
    PORT
      LAYER M4 ;
        RECT  55.968 28.128 56.16 28.152 ;
    END
  END i[268]
  PIN i[269]
    DIRECTION INPUT ;
    USE SIGNAL ;
    PORT
      LAYER M4 ;
        RECT  55.968 28.224 56.16 28.248 ;
    END
  END i[269]
  PIN i[26]
    DIRECTION INPUT ;
    USE SIGNAL ;
    PORT
      LAYER M4 ;
        RECT  55.968 4.752 56.16 4.776 ;
    END
  END i[26]
  PIN i[270]
    DIRECTION INPUT ;
    USE SIGNAL ;
    PORT
      LAYER M4 ;
        RECT  55.968 28.32 56.16 28.344 ;
    END
  END i[270]
  PIN i[271]
    DIRECTION INPUT ;
    USE SIGNAL ;
    PORT
      LAYER M4 ;
        RECT  55.968 28.416 56.16 28.44 ;
    END
  END i[271]
  PIN i[272]
    DIRECTION INPUT ;
    USE SIGNAL ;
    PORT
      LAYER M4 ;
        RECT  55.968 28.512 56.16 28.536 ;
    END
  END i[272]
  PIN i[273]
    DIRECTION INPUT ;
    USE SIGNAL ;
    PORT
      LAYER M4 ;
        RECT  55.968 28.608 56.16 28.632 ;
    END
  END i[273]
  PIN i[274]
    DIRECTION INPUT ;
    USE SIGNAL ;
    PORT
      LAYER M4 ;
        RECT  55.968 28.704 56.16 28.728 ;
    END
  END i[274]
  PIN i[275]
    DIRECTION INPUT ;
    USE SIGNAL ;
    PORT
      LAYER M4 ;
        RECT  55.968 28.8 56.16 28.824 ;
    END
  END i[275]
  PIN i[276]
    DIRECTION INPUT ;
    USE SIGNAL ;
    PORT
      LAYER M4 ;
        RECT  55.968 28.896 56.16 28.92 ;
    END
  END i[276]
  PIN i[277]
    DIRECTION INPUT ;
    USE SIGNAL ;
    PORT
      LAYER M4 ;
        RECT  55.968 28.992 56.16 29.016 ;
    END
  END i[277]
  PIN i[278]
    DIRECTION INPUT ;
    USE SIGNAL ;
    PORT
      LAYER M4 ;
        RECT  55.968 29.088 56.16 29.112 ;
    END
  END i[278]
  PIN i[279]
    DIRECTION INPUT ;
    USE SIGNAL ;
    PORT
      LAYER M4 ;
        RECT  55.968 29.184 56.16 29.208 ;
    END
  END i[279]
  PIN i[27]
    DIRECTION INPUT ;
    USE SIGNAL ;
    PORT
      LAYER M4 ;
        RECT  55.968 4.848 56.16 4.872 ;
    END
  END i[27]
  PIN i[280]
    DIRECTION INPUT ;
    USE SIGNAL ;
    PORT
      LAYER M4 ;
        RECT  55.968 29.28 56.16 29.304 ;
    END
  END i[280]
  PIN i[281]
    DIRECTION INPUT ;
    USE SIGNAL ;
    PORT
      LAYER M4 ;
        RECT  55.968 29.376 56.16 29.4 ;
    END
  END i[281]
  PIN i[282]
    DIRECTION INPUT ;
    USE SIGNAL ;
    PORT
      LAYER M4 ;
        RECT  55.968 29.472 56.16 29.496 ;
    END
  END i[282]
  PIN i[283]
    DIRECTION INPUT ;
    USE SIGNAL ;
    PORT
      LAYER M4 ;
        RECT  55.968 29.568 56.16 29.592 ;
    END
  END i[283]
  PIN i[284]
    DIRECTION INPUT ;
    USE SIGNAL ;
    PORT
      LAYER M4 ;
        RECT  55.968 29.664 56.16 29.688 ;
    END
  END i[284]
  PIN i[285]
    DIRECTION INPUT ;
    USE SIGNAL ;
    PORT
      LAYER M4 ;
        RECT  55.968 29.808 56.16 29.832 ;
    END
  END i[285]
  PIN i[286]
    DIRECTION INPUT ;
    USE SIGNAL ;
    PORT
      LAYER M4 ;
        RECT  55.968 29.904 56.16 29.928 ;
    END
  END i[286]
  PIN i[287]
    DIRECTION INPUT ;
    USE SIGNAL ;
    PORT
      LAYER M4 ;
        RECT  55.968 30 56.16 30.024 ;
    END
  END i[287]
  PIN i[288]
    DIRECTION INPUT ;
    USE SIGNAL ;
    PORT
      LAYER M4 ;
        RECT  55.968 30.096 56.16 30.12 ;
    END
  END i[288]
  PIN i[289]
    DIRECTION INPUT ;
    USE SIGNAL ;
    PORT
      LAYER M4 ;
        RECT  55.968 30.192 56.16 30.216 ;
    END
  END i[289]
  PIN i[28]
    DIRECTION INPUT ;
    USE SIGNAL ;
    PORT
      LAYER M4 ;
        RECT  55.968 4.944 56.16 4.968 ;
    END
  END i[28]
  PIN i[290]
    DIRECTION INPUT ;
    USE SIGNAL ;
    PORT
      LAYER M4 ;
        RECT  55.968 30.288 56.16 30.312 ;
    END
  END i[290]
  PIN i[291]
    DIRECTION INPUT ;
    USE SIGNAL ;
    PORT
      LAYER M4 ;
        RECT  55.968 30.384 56.16 30.408 ;
    END
  END i[291]
  PIN i[292]
    DIRECTION INPUT ;
    USE SIGNAL ;
    PORT
      LAYER M4 ;
        RECT  55.968 30.48 56.16 30.504 ;
    END
  END i[292]
  PIN i[293]
    DIRECTION INPUT ;
    USE SIGNAL ;
    PORT
      LAYER M4 ;
        RECT  55.968 30.576 56.16 30.6 ;
    END
  END i[293]
  PIN i[294]
    DIRECTION INPUT ;
    USE SIGNAL ;
    PORT
      LAYER M4 ;
        RECT  55.968 30.672 56.16 30.696 ;
    END
  END i[294]
  PIN i[295]
    DIRECTION INPUT ;
    USE SIGNAL ;
    PORT
      LAYER M4 ;
        RECT  55.968 30.768 56.16 30.792 ;
    END
  END i[295]
  PIN i[296]
    DIRECTION INPUT ;
    USE SIGNAL ;
    PORT
      LAYER M4 ;
        RECT  55.968 30.864 56.16 30.888 ;
    END
  END i[296]
  PIN i[297]
    DIRECTION INPUT ;
    USE SIGNAL ;
    PORT
      LAYER M4 ;
        RECT  55.968 30.96 56.16 30.984 ;
    END
  END i[297]
  PIN i[298]
    DIRECTION INPUT ;
    USE SIGNAL ;
    PORT
      LAYER M4 ;
        RECT  55.968 31.056 56.16 31.08 ;
    END
  END i[298]
  PIN i[299]
    DIRECTION INPUT ;
    USE SIGNAL ;
    PORT
      LAYER M4 ;
        RECT  55.968 31.152 56.16 31.176 ;
    END
  END i[299]
  PIN i[29]
    DIRECTION INPUT ;
    USE SIGNAL ;
    PORT
      LAYER M4 ;
        RECT  55.968 5.04 56.16 5.064 ;
    END
  END i[29]
  PIN i[2]
    DIRECTION INPUT ;
    USE SIGNAL ;
    PORT
      LAYER M4 ;
        RECT  55.968 2.4 56.16 2.424 ;
    END
  END i[2]
  PIN i[300]
    DIRECTION INPUT ;
    USE SIGNAL ;
    PORT
      LAYER M4 ;
        RECT  55.968 31.248 56.16 31.272 ;
    END
  END i[300]
  PIN i[301]
    DIRECTION INPUT ;
    USE SIGNAL ;
    PORT
      LAYER M4 ;
        RECT  55.968 31.344 56.16 31.368 ;
    END
  END i[301]
  PIN i[302]
    DIRECTION INPUT ;
    USE SIGNAL ;
    PORT
      LAYER M4 ;
        RECT  55.968 31.44 56.16 31.464 ;
    END
  END i[302]
  PIN i[303]
    DIRECTION INPUT ;
    USE SIGNAL ;
    PORT
      LAYER M4 ;
        RECT  55.968 31.536 56.16 31.56 ;
    END
  END i[303]
  PIN i[304]
    DIRECTION INPUT ;
    USE SIGNAL ;
    PORT
      LAYER M4 ;
        RECT  55.968 31.632 56.16 31.656 ;
    END
  END i[304]
  PIN i[305]
    DIRECTION INPUT ;
    USE SIGNAL ;
    PORT
      LAYER M4 ;
        RECT  55.968 31.728 56.16 31.752 ;
    END
  END i[305]
  PIN i[306]
    DIRECTION INPUT ;
    USE SIGNAL ;
    PORT
      LAYER M4 ;
        RECT  55.968 31.824 56.16 31.848 ;
    END
  END i[306]
  PIN i[307]
    DIRECTION INPUT ;
    USE SIGNAL ;
    PORT
      LAYER M4 ;
        RECT  55.968 31.92 56.16 31.944 ;
    END
  END i[307]
  PIN i[308]
    DIRECTION INPUT ;
    USE SIGNAL ;
    PORT
      LAYER M4 ;
        RECT  55.968 32.016 56.16 32.04 ;
    END
  END i[308]
  PIN i[309]
    DIRECTION INPUT ;
    USE SIGNAL ;
    PORT
      LAYER M4 ;
        RECT  55.968 32.112 56.16 32.136 ;
    END
  END i[309]
  PIN i[30]
    DIRECTION INPUT ;
    USE SIGNAL ;
    PORT
      LAYER M4 ;
        RECT  55.968 5.136 56.16 5.16 ;
    END
  END i[30]
  PIN i[310]
    DIRECTION INPUT ;
    USE SIGNAL ;
    PORT
      LAYER M4 ;
        RECT  55.968 32.208 56.16 32.232 ;
    END
  END i[310]
  PIN i[311]
    DIRECTION INPUT ;
    USE SIGNAL ;
    PORT
      LAYER M4 ;
        RECT  55.968 32.304 56.16 32.328 ;
    END
  END i[311]
  PIN i[312]
    DIRECTION INPUT ;
    USE SIGNAL ;
    PORT
      LAYER M4 ;
        RECT  55.968 32.4 56.16 32.424 ;
    END
  END i[312]
  PIN i[313]
    DIRECTION INPUT ;
    USE SIGNAL ;
    PORT
      LAYER M4 ;
        RECT  55.968 32.496 56.16 32.52 ;
    END
  END i[313]
  PIN i[314]
    DIRECTION INPUT ;
    USE SIGNAL ;
    PORT
      LAYER M4 ;
        RECT  55.968 32.592 56.16 32.616 ;
    END
  END i[314]
  PIN i[315]
    DIRECTION INPUT ;
    USE SIGNAL ;
    PORT
      LAYER M4 ;
        RECT  55.968 32.688 56.16 32.712 ;
    END
  END i[315]
  PIN i[316]
    DIRECTION INPUT ;
    USE SIGNAL ;
    PORT
      LAYER M4 ;
        RECT  55.968 32.784 56.16 32.808 ;
    END
  END i[316]
  PIN i[317]
    DIRECTION INPUT ;
    USE SIGNAL ;
    PORT
      LAYER M4 ;
        RECT  55.968 32.88 56.16 32.904 ;
    END
  END i[317]
  PIN i[318]
    DIRECTION INPUT ;
    USE SIGNAL ;
    PORT
      LAYER M4 ;
        RECT  55.968 32.976 56.16 33 ;
    END
  END i[318]
  PIN i[319]
    DIRECTION INPUT ;
    USE SIGNAL ;
    PORT
      LAYER M4 ;
        RECT  55.968 33.072 56.16 33.096 ;
    END
  END i[319]
  PIN i[31]
    DIRECTION INPUT ;
    USE SIGNAL ;
    PORT
      LAYER M4 ;
        RECT  55.968 5.232 56.16 5.256 ;
    END
  END i[31]
  PIN i[320]
    DIRECTION INPUT ;
    USE SIGNAL ;
    PORT
      LAYER M4 ;
        RECT  55.968 33.168 56.16 33.192 ;
    END
  END i[320]
  PIN i[321]
    DIRECTION INPUT ;
    USE SIGNAL ;
    PORT
      LAYER M4 ;
        RECT  55.968 33.264 56.16 33.288 ;
    END
  END i[321]
  PIN i[322]
    DIRECTION INPUT ;
    USE SIGNAL ;
    PORT
      LAYER M4 ;
        RECT  55.968 33.36 56.16 33.384 ;
    END
  END i[322]
  PIN i[323]
    DIRECTION INPUT ;
    USE SIGNAL ;
    PORT
      LAYER M4 ;
        RECT  55.968 33.456 56.16 33.48 ;
    END
  END i[323]
  PIN i[324]
    DIRECTION INPUT ;
    USE SIGNAL ;
    PORT
      LAYER M4 ;
        RECT  55.968 33.552 56.16 33.576 ;
    END
  END i[324]
  PIN i[325]
    DIRECTION INPUT ;
    USE SIGNAL ;
    PORT
      LAYER M4 ;
        RECT  55.968 33.648 56.16 33.672 ;
    END
  END i[325]
  PIN i[326]
    DIRECTION INPUT ;
    USE SIGNAL ;
    PORT
      LAYER M4 ;
        RECT  55.968 33.744 56.16 33.768 ;
    END
  END i[326]
  PIN i[327]
    DIRECTION INPUT ;
    USE SIGNAL ;
    PORT
      LAYER M4 ;
        RECT  55.968 33.84 56.16 33.864 ;
    END
  END i[327]
  PIN i[328]
    DIRECTION INPUT ;
    USE SIGNAL ;
    PORT
      LAYER M4 ;
        RECT  55.968 33.936 56.16 33.96 ;
    END
  END i[328]
  PIN i[329]
    DIRECTION INPUT ;
    USE SIGNAL ;
    PORT
      LAYER M4 ;
        RECT  55.968 34.032 56.16 34.056 ;
    END
  END i[329]
  PIN i[32]
    DIRECTION INPUT ;
    USE SIGNAL ;
    PORT
      LAYER M4 ;
        RECT  55.968 5.328 56.16 5.352 ;
    END
  END i[32]
  PIN i[330]
    DIRECTION INPUT ;
    USE SIGNAL ;
    PORT
      LAYER M4 ;
        RECT  55.968 34.128 56.16 34.152 ;
    END
  END i[330]
  PIN i[331]
    DIRECTION INPUT ;
    USE SIGNAL ;
    PORT
      LAYER M4 ;
        RECT  55.968 34.224 56.16 34.248 ;
    END
  END i[331]
  PIN i[332]
    DIRECTION INPUT ;
    USE SIGNAL ;
    PORT
      LAYER M4 ;
        RECT  55.968 34.32 56.16 34.344 ;
    END
  END i[332]
  PIN i[333]
    DIRECTION INPUT ;
    USE SIGNAL ;
    PORT
      LAYER M4 ;
        RECT  55.968 34.416 56.16 34.44 ;
    END
  END i[333]
  PIN i[334]
    DIRECTION INPUT ;
    USE SIGNAL ;
    PORT
      LAYER M4 ;
        RECT  55.968 34.512 56.16 34.536 ;
    END
  END i[334]
  PIN i[335]
    DIRECTION INPUT ;
    USE SIGNAL ;
    PORT
      LAYER M4 ;
        RECT  55.968 34.608 56.16 34.632 ;
    END
  END i[335]
  PIN i[336]
    DIRECTION INPUT ;
    USE SIGNAL ;
    PORT
      LAYER M4 ;
        RECT  55.968 34.704 56.16 34.728 ;
    END
  END i[336]
  PIN i[337]
    DIRECTION INPUT ;
    USE SIGNAL ;
    PORT
      LAYER M4 ;
        RECT  55.968 34.8 56.16 34.824 ;
    END
  END i[337]
  PIN i[338]
    DIRECTION INPUT ;
    USE SIGNAL ;
    PORT
      LAYER M4 ;
        RECT  55.968 34.896 56.16 34.92 ;
    END
  END i[338]
  PIN i[339]
    DIRECTION INPUT ;
    USE SIGNAL ;
    PORT
      LAYER M4 ;
        RECT  55.968 34.992 56.16 35.016 ;
    END
  END i[339]
  PIN i[33]
    DIRECTION INPUT ;
    USE SIGNAL ;
    PORT
      LAYER M4 ;
        RECT  55.968 5.424 56.16 5.448 ;
    END
  END i[33]
  PIN i[340]
    DIRECTION INPUT ;
    USE SIGNAL ;
    PORT
      LAYER M4 ;
        RECT  55.968 35.088 56.16 35.112 ;
    END
  END i[340]
  PIN i[341]
    DIRECTION INPUT ;
    USE SIGNAL ;
    PORT
      LAYER M4 ;
        RECT  55.968 35.184 56.16 35.208 ;
    END
  END i[341]
  PIN i[342]
    DIRECTION INPUT ;
    USE SIGNAL ;
    PORT
      LAYER M4 ;
        RECT  55.968 35.28 56.16 35.304 ;
    END
  END i[342]
  PIN i[343]
    DIRECTION INPUT ;
    USE SIGNAL ;
    PORT
      LAYER M4 ;
        RECT  55.968 35.376 56.16 35.4 ;
    END
  END i[343]
  PIN i[344]
    DIRECTION INPUT ;
    USE SIGNAL ;
    PORT
      LAYER M4 ;
        RECT  55.968 35.472 56.16 35.496 ;
    END
  END i[344]
  PIN i[345]
    DIRECTION INPUT ;
    USE SIGNAL ;
    PORT
      LAYER M4 ;
        RECT  55.968 35.568 56.16 35.592 ;
    END
  END i[345]
  PIN i[346]
    DIRECTION INPUT ;
    USE SIGNAL ;
    PORT
      LAYER M4 ;
        RECT  55.968 35.664 56.16 35.688 ;
    END
  END i[346]
  PIN i[347]
    DIRECTION INPUT ;
    USE SIGNAL ;
    PORT
      LAYER M4 ;
        RECT  55.968 35.76 56.16 35.784 ;
    END
  END i[347]
  PIN i[348]
    DIRECTION INPUT ;
    USE SIGNAL ;
    PORT
      LAYER M4 ;
        RECT  55.968 35.856 56.16 35.88 ;
    END
  END i[348]
  PIN i[349]
    DIRECTION INPUT ;
    USE SIGNAL ;
    PORT
      LAYER M4 ;
        RECT  55.968 35.952 56.16 35.976 ;
    END
  END i[349]
  PIN i[34]
    DIRECTION INPUT ;
    USE SIGNAL ;
    PORT
      LAYER M4 ;
        RECT  55.968 5.52 56.16 5.544 ;
    END
  END i[34]
  PIN i[350]
    DIRECTION INPUT ;
    USE SIGNAL ;
    PORT
      LAYER M4 ;
        RECT  55.968 36.048 56.16 36.072 ;
    END
  END i[350]
  PIN i[351]
    DIRECTION INPUT ;
    USE SIGNAL ;
    PORT
      LAYER M4 ;
        RECT  55.968 36.144 56.16 36.168 ;
    END
  END i[351]
  PIN i[352]
    DIRECTION INPUT ;
    USE SIGNAL ;
    PORT
      LAYER M4 ;
        RECT  55.968 36.288 56.16 36.312 ;
    END
  END i[352]
  PIN i[353]
    DIRECTION INPUT ;
    USE SIGNAL ;
    PORT
      LAYER M4 ;
        RECT  55.968 36.384 56.16 36.408 ;
    END
  END i[353]
  PIN i[354]
    DIRECTION INPUT ;
    USE SIGNAL ;
    PORT
      LAYER M4 ;
        RECT  55.968 36.48 56.16 36.504 ;
    END
  END i[354]
  PIN i[355]
    DIRECTION INPUT ;
    USE SIGNAL ;
    PORT
      LAYER M4 ;
        RECT  55.968 36.576 56.16 36.6 ;
    END
  END i[355]
  PIN i[356]
    DIRECTION INPUT ;
    USE SIGNAL ;
    PORT
      LAYER M4 ;
        RECT  55.968 36.672 56.16 36.696 ;
    END
  END i[356]
  PIN i[357]
    DIRECTION INPUT ;
    USE SIGNAL ;
    PORT
      LAYER M4 ;
        RECT  55.968 36.768 56.16 36.792 ;
    END
  END i[357]
  PIN i[358]
    DIRECTION INPUT ;
    USE SIGNAL ;
    PORT
      LAYER M4 ;
        RECT  55.968 36.864 56.16 36.888 ;
    END
  END i[358]
  PIN i[359]
    DIRECTION INPUT ;
    USE SIGNAL ;
    PORT
      LAYER M4 ;
        RECT  55.968 36.96 56.16 36.984 ;
    END
  END i[359]
  PIN i[35]
    DIRECTION INPUT ;
    USE SIGNAL ;
    PORT
      LAYER M4 ;
        RECT  55.968 5.616 56.16 5.64 ;
    END
  END i[35]
  PIN i[360]
    DIRECTION INPUT ;
    USE SIGNAL ;
    PORT
      LAYER M4 ;
        RECT  55.968 37.056 56.16 37.08 ;
    END
  END i[360]
  PIN i[361]
    DIRECTION INPUT ;
    USE SIGNAL ;
    PORT
      LAYER M4 ;
        RECT  55.968 37.152 56.16 37.176 ;
    END
  END i[361]
  PIN i[362]
    DIRECTION INPUT ;
    USE SIGNAL ;
    PORT
      LAYER M4 ;
        RECT  55.968 37.248 56.16 37.272 ;
    END
  END i[362]
  PIN i[363]
    DIRECTION INPUT ;
    USE SIGNAL ;
    PORT
      LAYER M4 ;
        RECT  55.968 37.344 56.16 37.368 ;
    END
  END i[363]
  PIN i[364]
    DIRECTION INPUT ;
    USE SIGNAL ;
    PORT
      LAYER M4 ;
        RECT  55.968 37.44 56.16 37.464 ;
    END
  END i[364]
  PIN i[365]
    DIRECTION INPUT ;
    USE SIGNAL ;
    PORT
      LAYER M4 ;
        RECT  55.968 37.536 56.16 37.56 ;
    END
  END i[365]
  PIN i[366]
    DIRECTION INPUT ;
    USE SIGNAL ;
    PORT
      LAYER M4 ;
        RECT  55.968 37.632 56.16 37.656 ;
    END
  END i[366]
  PIN i[367]
    DIRECTION INPUT ;
    USE SIGNAL ;
    PORT
      LAYER M4 ;
        RECT  55.968 37.728 56.16 37.752 ;
    END
  END i[367]
  PIN i[368]
    DIRECTION INPUT ;
    USE SIGNAL ;
    PORT
      LAYER M4 ;
        RECT  55.968 37.824 56.16 37.848 ;
    END
  END i[368]
  PIN i[369]
    DIRECTION INPUT ;
    USE SIGNAL ;
    PORT
      LAYER M4 ;
        RECT  55.968 37.92 56.16 37.944 ;
    END
  END i[369]
  PIN i[36]
    DIRECTION INPUT ;
    USE SIGNAL ;
    PORT
      LAYER M4 ;
        RECT  55.968 5.712 56.16 5.736 ;
    END
  END i[36]
  PIN i[370]
    DIRECTION INPUT ;
    USE SIGNAL ;
    PORT
      LAYER M4 ;
        RECT  55.968 38.016 56.16 38.04 ;
    END
  END i[370]
  PIN i[371]
    DIRECTION INPUT ;
    USE SIGNAL ;
    PORT
      LAYER M4 ;
        RECT  55.968 38.112 56.16 38.136 ;
    END
  END i[371]
  PIN i[372]
    DIRECTION INPUT ;
    USE SIGNAL ;
    PORT
      LAYER M4 ;
        RECT  55.968 38.208 56.16 38.232 ;
    END
  END i[372]
  PIN i[373]
    DIRECTION INPUT ;
    USE SIGNAL ;
    PORT
      LAYER M4 ;
        RECT  55.968 38.304 56.16 38.328 ;
    END
  END i[373]
  PIN i[374]
    DIRECTION INPUT ;
    USE SIGNAL ;
    PORT
      LAYER M4 ;
        RECT  55.968 38.4 56.16 38.424 ;
    END
  END i[374]
  PIN i[375]
    DIRECTION INPUT ;
    USE SIGNAL ;
    PORT
      LAYER M4 ;
        RECT  55.968 38.496 56.16 38.52 ;
    END
  END i[375]
  PIN i[376]
    DIRECTION INPUT ;
    USE SIGNAL ;
    PORT
      LAYER M4 ;
        RECT  55.968 38.592 56.16 38.616 ;
    END
  END i[376]
  PIN i[377]
    DIRECTION INPUT ;
    USE SIGNAL ;
    PORT
      LAYER M4 ;
        RECT  55.968 38.688 56.16 38.712 ;
    END
  END i[377]
  PIN i[378]
    DIRECTION INPUT ;
    USE SIGNAL ;
    PORT
      LAYER M4 ;
        RECT  55.968 38.784 56.16 38.808 ;
    END
  END i[378]
  PIN i[379]
    DIRECTION INPUT ;
    USE SIGNAL ;
    PORT
      LAYER M4 ;
        RECT  55.968 38.88 56.16 38.904 ;
    END
  END i[379]
  PIN i[37]
    DIRECTION INPUT ;
    USE SIGNAL ;
    PORT
      LAYER M4 ;
        RECT  55.968 5.808 56.16 5.832 ;
    END
  END i[37]
  PIN i[380]
    DIRECTION INPUT ;
    USE SIGNAL ;
    PORT
      LAYER M4 ;
        RECT  55.968 38.976 56.16 39 ;
    END
  END i[380]
  PIN i[381]
    DIRECTION INPUT ;
    USE SIGNAL ;
    PORT
      LAYER M4 ;
        RECT  55.968 39.072 56.16 39.096 ;
    END
  END i[381]
  PIN i[382]
    DIRECTION INPUT ;
    USE SIGNAL ;
    PORT
      LAYER M4 ;
        RECT  55.968 39.168 56.16 39.192 ;
    END
  END i[382]
  PIN i[383]
    DIRECTION INPUT ;
    USE SIGNAL ;
    PORT
      LAYER M4 ;
        RECT  55.968 39.264 56.16 39.288 ;
    END
  END i[383]
  PIN i[384]
    DIRECTION INPUT ;
    USE SIGNAL ;
    PORT
      LAYER M4 ;
        RECT  55.968 39.36 56.16 39.384 ;
    END
  END i[384]
  PIN i[385]
    DIRECTION INPUT ;
    USE SIGNAL ;
    PORT
      LAYER M4 ;
        RECT  55.968 39.456 56.16 39.48 ;
    END
  END i[385]
  PIN i[386]
    DIRECTION INPUT ;
    USE SIGNAL ;
    PORT
      LAYER M4 ;
        RECT  55.968 39.552 56.16 39.576 ;
    END
  END i[386]
  PIN i[387]
    DIRECTION INPUT ;
    USE SIGNAL ;
    PORT
      LAYER M4 ;
        RECT  55.968 39.648 56.16 39.672 ;
    END
  END i[387]
  PIN i[388]
    DIRECTION INPUT ;
    USE SIGNAL ;
    PORT
      LAYER M4 ;
        RECT  55.968 39.744 56.16 39.768 ;
    END
  END i[388]
  PIN i[389]
    DIRECTION INPUT ;
    USE SIGNAL ;
    PORT
      LAYER M4 ;
        RECT  55.968 39.84 56.16 39.864 ;
    END
  END i[389]
  PIN i[38]
    DIRECTION INPUT ;
    USE SIGNAL ;
    PORT
      LAYER M4 ;
        RECT  55.968 5.904 56.16 5.928 ;
    END
  END i[38]
  PIN i[390]
    DIRECTION INPUT ;
    USE SIGNAL ;
    PORT
      LAYER M4 ;
        RECT  55.968 39.936 56.16 39.96 ;
    END
  END i[390]
  PIN i[391]
    DIRECTION INPUT ;
    USE SIGNAL ;
    PORT
      LAYER M4 ;
        RECT  55.968 40.032 56.16 40.056 ;
    END
  END i[391]
  PIN i[392]
    DIRECTION INPUT ;
    USE SIGNAL ;
    PORT
      LAYER M4 ;
        RECT  55.968 40.128 56.16 40.152 ;
    END
  END i[392]
  PIN i[393]
    DIRECTION INPUT ;
    USE SIGNAL ;
    PORT
      LAYER M4 ;
        RECT  55.968 40.224 56.16 40.248 ;
    END
  END i[393]
  PIN i[394]
    DIRECTION INPUT ;
    USE SIGNAL ;
    PORT
      LAYER M4 ;
        RECT  55.968 40.32 56.16 40.344 ;
    END
  END i[394]
  PIN i[395]
    DIRECTION INPUT ;
    USE SIGNAL ;
    PORT
      LAYER M4 ;
        RECT  55.968 40.416 56.16 40.44 ;
    END
  END i[395]
  PIN i[396]
    DIRECTION INPUT ;
    USE SIGNAL ;
    PORT
      LAYER M4 ;
        RECT  55.968 40.512 56.16 40.536 ;
    END
  END i[396]
  PIN i[397]
    DIRECTION INPUT ;
    USE SIGNAL ;
    PORT
      LAYER M4 ;
        RECT  55.968 40.608 56.16 40.632 ;
    END
  END i[397]
  PIN i[398]
    DIRECTION INPUT ;
    USE SIGNAL ;
    PORT
      LAYER M4 ;
        RECT  55.968 40.704 56.16 40.728 ;
    END
  END i[398]
  PIN i[399]
    DIRECTION INPUT ;
    USE SIGNAL ;
    PORT
      LAYER M4 ;
        RECT  55.968 40.8 56.16 40.824 ;
    END
  END i[399]
  PIN i[39]
    DIRECTION INPUT ;
    USE SIGNAL ;
    PORT
      LAYER M4 ;
        RECT  55.968 6 56.16 6.024 ;
    END
  END i[39]
  PIN i[3]
    DIRECTION INPUT ;
    USE SIGNAL ;
    PORT
      LAYER M4 ;
        RECT  55.968 2.496 56.16 2.52 ;
    END
  END i[3]
  PIN i[400]
    DIRECTION INPUT ;
    USE SIGNAL ;
    PORT
      LAYER M4 ;
        RECT  55.968 40.896 56.16 40.92 ;
    END
  END i[400]
  PIN i[401]
    DIRECTION INPUT ;
    USE SIGNAL ;
    PORT
      LAYER M4 ;
        RECT  55.968 40.992 56.16 41.016 ;
    END
  END i[401]
  PIN i[402]
    DIRECTION INPUT ;
    USE SIGNAL ;
    PORT
      LAYER M4 ;
        RECT  55.968 41.088 56.16 41.112 ;
    END
  END i[402]
  PIN i[403]
    DIRECTION INPUT ;
    USE SIGNAL ;
    PORT
      LAYER M4 ;
        RECT  55.968 41.184 56.16 41.208 ;
    END
  END i[403]
  PIN i[404]
    DIRECTION INPUT ;
    USE SIGNAL ;
    PORT
      LAYER M4 ;
        RECT  55.968 41.28 56.16 41.304 ;
    END
  END i[404]
  PIN i[405]
    DIRECTION INPUT ;
    USE SIGNAL ;
    PORT
      LAYER M4 ;
        RECT  55.968 41.376 56.16 41.4 ;
    END
  END i[405]
  PIN i[406]
    DIRECTION INPUT ;
    USE SIGNAL ;
    PORT
      LAYER M4 ;
        RECT  55.968 41.472 56.16 41.496 ;
    END
  END i[406]
  PIN i[407]
    DIRECTION INPUT ;
    USE SIGNAL ;
    PORT
      LAYER M4 ;
        RECT  55.968 41.568 56.16 41.592 ;
    END
  END i[407]
  PIN i[408]
    DIRECTION INPUT ;
    USE SIGNAL ;
    PORT
      LAYER M4 ;
        RECT  55.968 41.664 56.16 41.688 ;
    END
  END i[408]
  PIN i[409]
    DIRECTION INPUT ;
    USE SIGNAL ;
    PORT
      LAYER M4 ;
        RECT  55.968 41.76 56.16 41.784 ;
    END
  END i[409]
  PIN i[40]
    DIRECTION INPUT ;
    USE SIGNAL ;
    PORT
      LAYER M4 ;
        RECT  55.968 6.096 56.16 6.12 ;
    END
  END i[40]
  PIN i[410]
    DIRECTION INPUT ;
    USE SIGNAL ;
    PORT
      LAYER M4 ;
        RECT  55.968 41.856 56.16 41.88 ;
    END
  END i[410]
  PIN i[411]
    DIRECTION INPUT ;
    USE SIGNAL ;
    PORT
      LAYER M4 ;
        RECT  55.968 41.952 56.16 41.976 ;
    END
  END i[411]
  PIN i[412]
    DIRECTION INPUT ;
    USE SIGNAL ;
    PORT
      LAYER M4 ;
        RECT  55.968 42.048 56.16 42.072 ;
    END
  END i[412]
  PIN i[413]
    DIRECTION INPUT ;
    USE SIGNAL ;
    PORT
      LAYER M4 ;
        RECT  55.968 42.144 56.16 42.168 ;
    END
  END i[413]
  PIN i[414]
    DIRECTION INPUT ;
    USE SIGNAL ;
    PORT
      LAYER M4 ;
        RECT  55.968 42.24 56.16 42.264 ;
    END
  END i[414]
  PIN i[415]
    DIRECTION INPUT ;
    USE SIGNAL ;
    PORT
      LAYER M4 ;
        RECT  55.968 42.336 56.16 42.36 ;
    END
  END i[415]
  PIN i[416]
    DIRECTION INPUT ;
    USE SIGNAL ;
    PORT
      LAYER M4 ;
        RECT  55.968 42.432 56.16 42.456 ;
    END
  END i[416]
  PIN i[417]
    DIRECTION INPUT ;
    USE SIGNAL ;
    PORT
      LAYER M4 ;
        RECT  55.968 42.528 56.16 42.552 ;
    END
  END i[417]
  PIN i[418]
    DIRECTION INPUT ;
    USE SIGNAL ;
    PORT
      LAYER M4 ;
        RECT  55.968 42.624 56.16 42.648 ;
    END
  END i[418]
  PIN i[419]
    DIRECTION INPUT ;
    USE SIGNAL ;
    PORT
      LAYER M4 ;
        RECT  55.968 42.768 56.16 42.792 ;
    END
  END i[419]
  PIN i[41]
    DIRECTION INPUT ;
    USE SIGNAL ;
    PORT
      LAYER M4 ;
        RECT  55.968 6.192 56.16 6.216 ;
    END
  END i[41]
  PIN i[420]
    DIRECTION INPUT ;
    USE SIGNAL ;
    PORT
      LAYER M4 ;
        RECT  55.968 42.864 56.16 42.888 ;
    END
  END i[420]
  PIN i[421]
    DIRECTION INPUT ;
    USE SIGNAL ;
    PORT
      LAYER M4 ;
        RECT  55.968 42.96 56.16 42.984 ;
    END
  END i[421]
  PIN i[422]
    DIRECTION INPUT ;
    USE SIGNAL ;
    PORT
      LAYER M4 ;
        RECT  55.968 43.056 56.16 43.08 ;
    END
  END i[422]
  PIN i[423]
    DIRECTION INPUT ;
    USE SIGNAL ;
    PORT
      LAYER M4 ;
        RECT  55.968 43.152 56.16 43.176 ;
    END
  END i[423]
  PIN i[424]
    DIRECTION INPUT ;
    USE SIGNAL ;
    PORT
      LAYER M4 ;
        RECT  55.968 43.248 56.16 43.272 ;
    END
  END i[424]
  PIN i[425]
    DIRECTION INPUT ;
    USE SIGNAL ;
    PORT
      LAYER M4 ;
        RECT  55.968 43.344 56.16 43.368 ;
    END
  END i[425]
  PIN i[426]
    DIRECTION INPUT ;
    USE SIGNAL ;
    PORT
      LAYER M4 ;
        RECT  55.968 43.44 56.16 43.464 ;
    END
  END i[426]
  PIN i[427]
    DIRECTION INPUT ;
    USE SIGNAL ;
    PORT
      LAYER M4 ;
        RECT  55.968 43.536 56.16 43.56 ;
    END
  END i[427]
  PIN i[428]
    DIRECTION INPUT ;
    USE SIGNAL ;
    PORT
      LAYER M4 ;
        RECT  55.968 43.632 56.16 43.656 ;
    END
  END i[428]
  PIN i[429]
    DIRECTION INPUT ;
    USE SIGNAL ;
    PORT
      LAYER M4 ;
        RECT  55.968 43.728 56.16 43.752 ;
    END
  END i[429]
  PIN i[42]
    DIRECTION INPUT ;
    USE SIGNAL ;
    PORT
      LAYER M4 ;
        RECT  55.968 6.288 56.16 6.312 ;
    END
  END i[42]
  PIN i[430]
    DIRECTION INPUT ;
    USE SIGNAL ;
    PORT
      LAYER M4 ;
        RECT  55.968 43.824 56.16 43.848 ;
    END
  END i[430]
  PIN i[431]
    DIRECTION INPUT ;
    USE SIGNAL ;
    PORT
      LAYER M4 ;
        RECT  55.968 43.92 56.16 43.944 ;
    END
  END i[431]
  PIN i[432]
    DIRECTION INPUT ;
    USE SIGNAL ;
    PORT
      LAYER M4 ;
        RECT  55.968 44.016 56.16 44.04 ;
    END
  END i[432]
  PIN i[433]
    DIRECTION INPUT ;
    USE SIGNAL ;
    PORT
      LAYER M4 ;
        RECT  55.968 44.112 56.16 44.136 ;
    END
  END i[433]
  PIN i[434]
    DIRECTION INPUT ;
    USE SIGNAL ;
    PORT
      LAYER M4 ;
        RECT  55.968 44.208 56.16 44.232 ;
    END
  END i[434]
  PIN i[435]
    DIRECTION INPUT ;
    USE SIGNAL ;
    PORT
      LAYER M4 ;
        RECT  55.968 44.304 56.16 44.328 ;
    END
  END i[435]
  PIN i[436]
    DIRECTION INPUT ;
    USE SIGNAL ;
    PORT
      LAYER M4 ;
        RECT  55.968 44.4 56.16 44.424 ;
    END
  END i[436]
  PIN i[437]
    DIRECTION INPUT ;
    USE SIGNAL ;
    PORT
      LAYER M4 ;
        RECT  55.968 44.496 56.16 44.52 ;
    END
  END i[437]
  PIN i[438]
    DIRECTION INPUT ;
    USE SIGNAL ;
    PORT
      LAYER M4 ;
        RECT  55.968 44.592 56.16 44.616 ;
    END
  END i[438]
  PIN i[439]
    DIRECTION INPUT ;
    USE SIGNAL ;
    PORT
      LAYER M4 ;
        RECT  55.968 44.688 56.16 44.712 ;
    END
  END i[439]
  PIN i[43]
    DIRECTION INPUT ;
    USE SIGNAL ;
    PORT
      LAYER M4 ;
        RECT  55.968 6.384 56.16 6.408 ;
    END
  END i[43]
  PIN i[440]
    DIRECTION INPUT ;
    USE SIGNAL ;
    PORT
      LAYER M4 ;
        RECT  55.968 44.784 56.16 44.808 ;
    END
  END i[440]
  PIN i[441]
    DIRECTION INPUT ;
    USE SIGNAL ;
    PORT
      LAYER M4 ;
        RECT  55.968 44.88 56.16 44.904 ;
    END
  END i[441]
  PIN i[442]
    DIRECTION INPUT ;
    USE SIGNAL ;
    PORT
      LAYER M4 ;
        RECT  55.968 44.976 56.16 45 ;
    END
  END i[442]
  PIN i[443]
    DIRECTION INPUT ;
    USE SIGNAL ;
    PORT
      LAYER M4 ;
        RECT  55.968 45.072 56.16 45.096 ;
    END
  END i[443]
  PIN i[444]
    DIRECTION INPUT ;
    USE SIGNAL ;
    PORT
      LAYER M4 ;
        RECT  55.968 45.168 56.16 45.192 ;
    END
  END i[444]
  PIN i[445]
    DIRECTION INPUT ;
    USE SIGNAL ;
    PORT
      LAYER M4 ;
        RECT  55.968 45.264 56.16 45.288 ;
    END
  END i[445]
  PIN i[446]
    DIRECTION INPUT ;
    USE SIGNAL ;
    PORT
      LAYER M4 ;
        RECT  55.968 45.36 56.16 45.384 ;
    END
  END i[446]
  PIN i[447]
    DIRECTION INPUT ;
    USE SIGNAL ;
    PORT
      LAYER M4 ;
        RECT  55.968 45.456 56.16 45.48 ;
    END
  END i[447]
  PIN i[448]
    DIRECTION INPUT ;
    USE SIGNAL ;
    PORT
      LAYER M4 ;
        RECT  55.968 45.552 56.16 45.576 ;
    END
  END i[448]
  PIN i[449]
    DIRECTION INPUT ;
    USE SIGNAL ;
    PORT
      LAYER M4 ;
        RECT  55.968 45.648 56.16 45.672 ;
    END
  END i[449]
  PIN i[44]
    DIRECTION INPUT ;
    USE SIGNAL ;
    PORT
      LAYER M4 ;
        RECT  55.968 6.48 56.16 6.504 ;
    END
  END i[44]
  PIN i[450]
    DIRECTION INPUT ;
    USE SIGNAL ;
    PORT
      LAYER M4 ;
        RECT  55.968 45.744 56.16 45.768 ;
    END
  END i[450]
  PIN i[451]
    DIRECTION INPUT ;
    USE SIGNAL ;
    PORT
      LAYER M4 ;
        RECT  55.968 45.84 56.16 45.864 ;
    END
  END i[451]
  PIN i[452]
    DIRECTION INPUT ;
    USE SIGNAL ;
    PORT
      LAYER M4 ;
        RECT  55.968 45.936 56.16 45.96 ;
    END
  END i[452]
  PIN i[453]
    DIRECTION INPUT ;
    USE SIGNAL ;
    PORT
      LAYER M4 ;
        RECT  55.968 46.032 56.16 46.056 ;
    END
  END i[453]
  PIN i[454]
    DIRECTION INPUT ;
    USE SIGNAL ;
    PORT
      LAYER M4 ;
        RECT  55.968 46.128 56.16 46.152 ;
    END
  END i[454]
  PIN i[455]
    DIRECTION INPUT ;
    USE SIGNAL ;
    PORT
      LAYER M4 ;
        RECT  55.968 46.224 56.16 46.248 ;
    END
  END i[455]
  PIN i[456]
    DIRECTION INPUT ;
    USE SIGNAL ;
    PORT
      LAYER M4 ;
        RECT  55.968 46.32 56.16 46.344 ;
    END
  END i[456]
  PIN i[457]
    DIRECTION INPUT ;
    USE SIGNAL ;
    PORT
      LAYER M4 ;
        RECT  55.968 46.416 56.16 46.44 ;
    END
  END i[457]
  PIN i[458]
    DIRECTION INPUT ;
    USE SIGNAL ;
    PORT
      LAYER M4 ;
        RECT  55.968 46.512 56.16 46.536 ;
    END
  END i[458]
  PIN i[459]
    DIRECTION INPUT ;
    USE SIGNAL ;
    PORT
      LAYER M4 ;
        RECT  55.968 46.608 56.16 46.632 ;
    END
  END i[459]
  PIN i[45]
    DIRECTION INPUT ;
    USE SIGNAL ;
    PORT
      LAYER M4 ;
        RECT  55.968 6.576 56.16 6.6 ;
    END
  END i[45]
  PIN i[460]
    DIRECTION INPUT ;
    USE SIGNAL ;
    PORT
      LAYER M4 ;
        RECT  55.968 46.704 56.16 46.728 ;
    END
  END i[460]
  PIN i[461]
    DIRECTION INPUT ;
    USE SIGNAL ;
    PORT
      LAYER M4 ;
        RECT  55.968 46.8 56.16 46.824 ;
    END
  END i[461]
  PIN i[462]
    DIRECTION INPUT ;
    USE SIGNAL ;
    PORT
      LAYER M4 ;
        RECT  55.968 46.896 56.16 46.92 ;
    END
  END i[462]
  PIN i[463]
    DIRECTION INPUT ;
    USE SIGNAL ;
    PORT
      LAYER M4 ;
        RECT  55.968 46.992 56.16 47.016 ;
    END
  END i[463]
  PIN i[464]
    DIRECTION INPUT ;
    USE SIGNAL ;
    PORT
      LAYER M4 ;
        RECT  55.968 47.088 56.16 47.112 ;
    END
  END i[464]
  PIN i[465]
    DIRECTION INPUT ;
    USE SIGNAL ;
    PORT
      LAYER M4 ;
        RECT  55.968 47.184 56.16 47.208 ;
    END
  END i[465]
  PIN i[466]
    DIRECTION INPUT ;
    USE SIGNAL ;
    PORT
      LAYER M4 ;
        RECT  55.968 47.28 56.16 47.304 ;
    END
  END i[466]
  PIN i[467]
    DIRECTION INPUT ;
    USE SIGNAL ;
    PORT
      LAYER M4 ;
        RECT  55.968 47.376 56.16 47.4 ;
    END
  END i[467]
  PIN i[468]
    DIRECTION INPUT ;
    USE SIGNAL ;
    PORT
      LAYER M4 ;
        RECT  55.968 47.472 56.16 47.496 ;
    END
  END i[468]
  PIN i[469]
    DIRECTION INPUT ;
    USE SIGNAL ;
    PORT
      LAYER M4 ;
        RECT  55.968 47.568 56.16 47.592 ;
    END
  END i[469]
  PIN i[46]
    DIRECTION INPUT ;
    USE SIGNAL ;
    PORT
      LAYER M4 ;
        RECT  55.968 6.672 56.16 6.696 ;
    END
  END i[46]
  PIN i[470]
    DIRECTION INPUT ;
    USE SIGNAL ;
    PORT
      LAYER M4 ;
        RECT  55.968 47.664 56.16 47.688 ;
    END
  END i[470]
  PIN i[471]
    DIRECTION INPUT ;
    USE SIGNAL ;
    PORT
      LAYER M4 ;
        RECT  55.968 47.76 56.16 47.784 ;
    END
  END i[471]
  PIN i[472]
    DIRECTION INPUT ;
    USE SIGNAL ;
    PORT
      LAYER M4 ;
        RECT  55.968 47.856 56.16 47.88 ;
    END
  END i[472]
  PIN i[473]
    DIRECTION INPUT ;
    USE SIGNAL ;
    PORT
      LAYER M4 ;
        RECT  55.968 47.952 56.16 47.976 ;
    END
  END i[473]
  PIN i[474]
    DIRECTION INPUT ;
    USE SIGNAL ;
    PORT
      LAYER M4 ;
        RECT  55.968 48.048 56.16 48.072 ;
    END
  END i[474]
  PIN i[475]
    DIRECTION INPUT ;
    USE SIGNAL ;
    PORT
      LAYER M4 ;
        RECT  55.968 48.144 56.16 48.168 ;
    END
  END i[475]
  PIN i[476]
    DIRECTION INPUT ;
    USE SIGNAL ;
    PORT
      LAYER M4 ;
        RECT  55.968 48.24 56.16 48.264 ;
    END
  END i[476]
  PIN i[477]
    DIRECTION INPUT ;
    USE SIGNAL ;
    PORT
      LAYER M4 ;
        RECT  55.968 48.336 56.16 48.36 ;
    END
  END i[477]
  PIN i[478]
    DIRECTION INPUT ;
    USE SIGNAL ;
    PORT
      LAYER M4 ;
        RECT  55.968 48.432 56.16 48.456 ;
    END
  END i[478]
  PIN i[479]
    DIRECTION INPUT ;
    USE SIGNAL ;
    PORT
      LAYER M4 ;
        RECT  55.968 48.528 56.16 48.552 ;
    END
  END i[479]
  PIN i[47]
    DIRECTION INPUT ;
    USE SIGNAL ;
    PORT
      LAYER M4 ;
        RECT  55.968 6.768 56.16 6.792 ;
    END
  END i[47]
  PIN i[480]
    DIRECTION INPUT ;
    USE SIGNAL ;
    PORT
      LAYER M4 ;
        RECT  55.968 48.624 56.16 48.648 ;
    END
  END i[480]
  PIN i[481]
    DIRECTION INPUT ;
    USE SIGNAL ;
    PORT
      LAYER M4 ;
        RECT  55.968 48.72 56.16 48.744 ;
    END
  END i[481]
  PIN i[482]
    DIRECTION INPUT ;
    USE SIGNAL ;
    PORT
      LAYER M4 ;
        RECT  55.968 48.816 56.16 48.84 ;
    END
  END i[482]
  PIN i[483]
    DIRECTION INPUT ;
    USE SIGNAL ;
    PORT
      LAYER M4 ;
        RECT  55.968 48.912 56.16 48.936 ;
    END
  END i[483]
  PIN i[484]
    DIRECTION INPUT ;
    USE SIGNAL ;
    PORT
      LAYER M4 ;
        RECT  55.968 49.008 56.16 49.032 ;
    END
  END i[484]
  PIN i[485]
    DIRECTION INPUT ;
    USE SIGNAL ;
    PORT
      LAYER M4 ;
        RECT  55.968 49.104 56.16 49.128 ;
    END
  END i[485]
  PIN i[486]
    DIRECTION INPUT ;
    USE SIGNAL ;
    PORT
      LAYER M4 ;
        RECT  55.968 49.248 56.16 49.272 ;
    END
  END i[486]
  PIN i[487]
    DIRECTION INPUT ;
    USE SIGNAL ;
    PORT
      LAYER M4 ;
        RECT  55.968 49.344 56.16 49.368 ;
    END
  END i[487]
  PIN i[488]
    DIRECTION INPUT ;
    USE SIGNAL ;
    PORT
      LAYER M4 ;
        RECT  55.968 49.44 56.16 49.464 ;
    END
  END i[488]
  PIN i[489]
    DIRECTION INPUT ;
    USE SIGNAL ;
    PORT
      LAYER M4 ;
        RECT  55.968 49.536 56.16 49.56 ;
    END
  END i[489]
  PIN i[48]
    DIRECTION INPUT ;
    USE SIGNAL ;
    PORT
      LAYER M4 ;
        RECT  55.968 6.864 56.16 6.888 ;
    END
  END i[48]
  PIN i[490]
    DIRECTION INPUT ;
    USE SIGNAL ;
    PORT
      LAYER M4 ;
        RECT  55.968 49.632 56.16 49.656 ;
    END
  END i[490]
  PIN i[491]
    DIRECTION INPUT ;
    USE SIGNAL ;
    PORT
      LAYER M4 ;
        RECT  55.968 49.728 56.16 49.752 ;
    END
  END i[491]
  PIN i[492]
    DIRECTION INPUT ;
    USE SIGNAL ;
    PORT
      LAYER M4 ;
        RECT  55.968 49.824 56.16 49.848 ;
    END
  END i[492]
  PIN i[493]
    DIRECTION INPUT ;
    USE SIGNAL ;
    PORT
      LAYER M4 ;
        RECT  55.968 49.92 56.16 49.944 ;
    END
  END i[493]
  PIN i[494]
    DIRECTION INPUT ;
    USE SIGNAL ;
    PORT
      LAYER M4 ;
        RECT  55.968 50.016 56.16 50.04 ;
    END
  END i[494]
  PIN i[495]
    DIRECTION INPUT ;
    USE SIGNAL ;
    PORT
      LAYER M4 ;
        RECT  55.968 50.112 56.16 50.136 ;
    END
  END i[495]
  PIN i[496]
    DIRECTION INPUT ;
    USE SIGNAL ;
    PORT
      LAYER M4 ;
        RECT  55.968 50.208 56.16 50.232 ;
    END
  END i[496]
  PIN i[497]
    DIRECTION INPUT ;
    USE SIGNAL ;
    PORT
      LAYER M4 ;
        RECT  55.968 50.304 56.16 50.328 ;
    END
  END i[497]
  PIN i[498]
    DIRECTION INPUT ;
    USE SIGNAL ;
    PORT
      LAYER M4 ;
        RECT  55.968 50.4 56.16 50.424 ;
    END
  END i[498]
  PIN i[499]
    DIRECTION INPUT ;
    USE SIGNAL ;
    PORT
      LAYER M4 ;
        RECT  55.968 50.496 56.16 50.52 ;
    END
  END i[499]
  PIN i[49]
    DIRECTION INPUT ;
    USE SIGNAL ;
    PORT
      LAYER M4 ;
        RECT  55.968 6.96 56.16 6.984 ;
    END
  END i[49]
  PIN i[4]
    DIRECTION INPUT ;
    USE SIGNAL ;
    PORT
      LAYER M4 ;
        RECT  55.968 2.592 56.16 2.616 ;
    END
  END i[4]
  PIN i[500]
    DIRECTION INPUT ;
    USE SIGNAL ;
    PORT
      LAYER M4 ;
        RECT  55.968 50.592 56.16 50.616 ;
    END
  END i[500]
  PIN i[501]
    DIRECTION INPUT ;
    USE SIGNAL ;
    PORT
      LAYER M4 ;
        RECT  55.968 50.688 56.16 50.712 ;
    END
  END i[501]
  PIN i[502]
    DIRECTION INPUT ;
    USE SIGNAL ;
    PORT
      LAYER M4 ;
        RECT  55.968 50.784 56.16 50.808 ;
    END
  END i[502]
  PIN i[503]
    DIRECTION INPUT ;
    USE SIGNAL ;
    PORT
      LAYER M4 ;
        RECT  55.968 50.88 56.16 50.904 ;
    END
  END i[503]
  PIN i[504]
    DIRECTION INPUT ;
    USE SIGNAL ;
    PORT
      LAYER M4 ;
        RECT  55.968 50.976 56.16 51 ;
    END
  END i[504]
  PIN i[505]
    DIRECTION INPUT ;
    USE SIGNAL ;
    PORT
      LAYER M4 ;
        RECT  55.968 51.072 56.16 51.096 ;
    END
  END i[505]
  PIN i[506]
    DIRECTION INPUT ;
    USE SIGNAL ;
    PORT
      LAYER M4 ;
        RECT  55.968 51.168 56.16 51.192 ;
    END
  END i[506]
  PIN i[507]
    DIRECTION INPUT ;
    USE SIGNAL ;
    PORT
      LAYER M4 ;
        RECT  55.968 51.264 56.16 51.288 ;
    END
  END i[507]
  PIN i[508]
    DIRECTION INPUT ;
    USE SIGNAL ;
    PORT
      LAYER M4 ;
        RECT  55.968 51.36 56.16 51.384 ;
    END
  END i[508]
  PIN i[509]
    DIRECTION INPUT ;
    USE SIGNAL ;
    PORT
      LAYER M4 ;
        RECT  55.968 51.456 56.16 51.48 ;
    END
  END i[509]
  PIN i[50]
    DIRECTION INPUT ;
    USE SIGNAL ;
    PORT
      LAYER M4 ;
        RECT  55.968 7.056 56.16 7.08 ;
    END
  END i[50]
  PIN i[510]
    DIRECTION INPUT ;
    USE SIGNAL ;
    PORT
      LAYER M4 ;
        RECT  55.968 51.552 56.16 51.576 ;
    END
  END i[510]
  PIN i[511]
    DIRECTION INPUT ;
    USE SIGNAL ;
    PORT
      LAYER M4 ;
        RECT  55.968 51.648 56.16 51.672 ;
    END
  END i[511]
  PIN i[512]
    DIRECTION INPUT ;
    USE SIGNAL ;
    PORT
      LAYER M4 ;
        RECT  55.968 51.744 56.16 51.768 ;
    END
  END i[512]
  PIN i[513]
    DIRECTION INPUT ;
    USE SIGNAL ;
    PORT
      LAYER M4 ;
        RECT  55.968 51.84 56.16 51.864 ;
    END
  END i[513]
  PIN i[514]
    DIRECTION INPUT ;
    USE SIGNAL ;
    PORT
      LAYER M4 ;
        RECT  55.968 51.936 56.16 51.96 ;
    END
  END i[514]
  PIN i[515]
    DIRECTION INPUT ;
    USE SIGNAL ;
    PORT
      LAYER M4 ;
        RECT  55.968 52.032 56.16 52.056 ;
    END
  END i[515]
  PIN i[516]
    DIRECTION INPUT ;
    USE SIGNAL ;
    PORT
      LAYER M4 ;
        RECT  55.968 52.128 56.16 52.152 ;
    END
  END i[516]
  PIN i[517]
    DIRECTION INPUT ;
    USE SIGNAL ;
    PORT
      LAYER M4 ;
        RECT  55.968 52.224 56.16 52.248 ;
    END
  END i[517]
  PIN i[518]
    DIRECTION INPUT ;
    USE SIGNAL ;
    PORT
      LAYER M4 ;
        RECT  55.968 52.32 56.16 52.344 ;
    END
  END i[518]
  PIN i[519]
    DIRECTION INPUT ;
    USE SIGNAL ;
    PORT
      LAYER M4 ;
        RECT  55.968 52.416 56.16 52.44 ;
    END
  END i[519]
  PIN i[51]
    DIRECTION INPUT ;
    USE SIGNAL ;
    PORT
      LAYER M4 ;
        RECT  55.968 7.152 56.16 7.176 ;
    END
  END i[51]
  PIN i[520]
    DIRECTION INPUT ;
    USE SIGNAL ;
    PORT
      LAYER M4 ;
        RECT  55.968 52.512 56.16 52.536 ;
    END
  END i[520]
  PIN i[521]
    DIRECTION INPUT ;
    USE SIGNAL ;
    PORT
      LAYER M4 ;
        RECT  55.968 52.608 56.16 52.632 ;
    END
  END i[521]
  PIN i[522]
    DIRECTION INPUT ;
    USE SIGNAL ;
    PORT
      LAYER M4 ;
        RECT  55.968 52.704 56.16 52.728 ;
    END
  END i[522]
  PIN i[523]
    DIRECTION INPUT ;
    USE SIGNAL ;
    PORT
      LAYER M4 ;
        RECT  55.968 52.8 56.16 52.824 ;
    END
  END i[523]
  PIN i[524]
    DIRECTION INPUT ;
    USE SIGNAL ;
    PORT
      LAYER M4 ;
        RECT  55.968 52.896 56.16 52.92 ;
    END
  END i[524]
  PIN i[525]
    DIRECTION INPUT ;
    USE SIGNAL ;
    PORT
      LAYER M4 ;
        RECT  55.968 52.992 56.16 53.016 ;
    END
  END i[525]
  PIN i[526]
    DIRECTION INPUT ;
    USE SIGNAL ;
    PORT
      LAYER M4 ;
        RECT  55.968 53.088 56.16 53.112 ;
    END
  END i[526]
  PIN i[527]
    DIRECTION INPUT ;
    USE SIGNAL ;
    PORT
      LAYER M4 ;
        RECT  55.968 53.184 56.16 53.208 ;
    END
  END i[527]
  PIN i[528]
    DIRECTION INPUT ;
    USE SIGNAL ;
    PORT
      LAYER M4 ;
        RECT  55.968 53.28 56.16 53.304 ;
    END
  END i[528]
  PIN i[529]
    DIRECTION INPUT ;
    USE SIGNAL ;
    PORT
      LAYER M4 ;
        RECT  55.968 53.376 56.16 53.4 ;
    END
  END i[529]
  PIN i[52]
    DIRECTION INPUT ;
    USE SIGNAL ;
    PORT
      LAYER M4 ;
        RECT  55.968 7.248 56.16 7.272 ;
    END
  END i[52]
  PIN i[530]
    DIRECTION INPUT ;
    USE SIGNAL ;
    PORT
      LAYER M4 ;
        RECT  55.968 53.472 56.16 53.496 ;
    END
  END i[530]
  PIN i[531]
    DIRECTION INPUT ;
    USE SIGNAL ;
    PORT
      LAYER M4 ;
        RECT  55.968 53.568 56.16 53.592 ;
    END
  END i[531]
  PIN i[532]
    DIRECTION INPUT ;
    USE SIGNAL ;
    PORT
      LAYER M4 ;
        RECT  55.968 53.664 56.16 53.688 ;
    END
  END i[532]
  PIN i[533]
    DIRECTION INPUT ;
    USE SIGNAL ;
    PORT
      LAYER M4 ;
        RECT  55.968 53.76 56.16 53.784 ;
    END
  END i[533]
  PIN i[534]
    DIRECTION INPUT ;
    USE SIGNAL ;
    PORT
      LAYER M4 ;
        RECT  55.968 53.856 56.16 53.88 ;
    END
  END i[534]
  PIN i[535]
    DIRECTION INPUT ;
    USE SIGNAL ;
    PORT
      LAYER M4 ;
        RECT  55.968 53.952 56.16 53.976 ;
    END
  END i[535]
  PIN i[53]
    DIRECTION INPUT ;
    USE SIGNAL ;
    PORT
      LAYER M4 ;
        RECT  55.968 7.344 56.16 7.368 ;
    END
  END i[53]
  PIN i[54]
    DIRECTION INPUT ;
    USE SIGNAL ;
    PORT
      LAYER M4 ;
        RECT  55.968 7.44 56.16 7.464 ;
    END
  END i[54]
  PIN i[55]
    DIRECTION INPUT ;
    USE SIGNAL ;
    PORT
      LAYER M4 ;
        RECT  55.968 7.536 56.16 7.56 ;
    END
  END i[55]
  PIN i[56]
    DIRECTION INPUT ;
    USE SIGNAL ;
    PORT
      LAYER M4 ;
        RECT  55.968 7.632 56.16 7.656 ;
    END
  END i[56]
  PIN i[57]
    DIRECTION INPUT ;
    USE SIGNAL ;
    PORT
      LAYER M4 ;
        RECT  55.968 7.728 56.16 7.752 ;
    END
  END i[57]
  PIN i[58]
    DIRECTION INPUT ;
    USE SIGNAL ;
    PORT
      LAYER M4 ;
        RECT  55.968 7.824 56.16 7.848 ;
    END
  END i[58]
  PIN i[59]
    DIRECTION INPUT ;
    USE SIGNAL ;
    PORT
      LAYER M4 ;
        RECT  55.968 7.92 56.16 7.944 ;
    END
  END i[59]
  PIN i[5]
    DIRECTION INPUT ;
    USE SIGNAL ;
    PORT
      LAYER M4 ;
        RECT  55.968 2.688 56.16 2.712 ;
    END
  END i[5]
  PIN i[60]
    DIRECTION INPUT ;
    USE SIGNAL ;
    PORT
      LAYER M4 ;
        RECT  55.968 8.016 56.16 8.04 ;
    END
  END i[60]
  PIN i[61]
    DIRECTION INPUT ;
    USE SIGNAL ;
    PORT
      LAYER M4 ;
        RECT  55.968 8.112 56.16 8.136 ;
    END
  END i[61]
  PIN i[62]
    DIRECTION INPUT ;
    USE SIGNAL ;
    PORT
      LAYER M4 ;
        RECT  55.968 8.208 56.16 8.232 ;
    END
  END i[62]
  PIN i[63]
    DIRECTION INPUT ;
    USE SIGNAL ;
    PORT
      LAYER M4 ;
        RECT  55.968 8.304 56.16 8.328 ;
    END
  END i[63]
  PIN i[64]
    DIRECTION INPUT ;
    USE SIGNAL ;
    PORT
      LAYER M4 ;
        RECT  55.968 8.4 56.16 8.424 ;
    END
  END i[64]
  PIN i[65]
    DIRECTION INPUT ;
    USE SIGNAL ;
    PORT
      LAYER M4 ;
        RECT  55.968 8.496 56.16 8.52 ;
    END
  END i[65]
  PIN i[66]
    DIRECTION INPUT ;
    USE SIGNAL ;
    PORT
      LAYER M4 ;
        RECT  55.968 8.592 56.16 8.616 ;
    END
  END i[66]
  PIN i[67]
    DIRECTION INPUT ;
    USE SIGNAL ;
    PORT
      LAYER M4 ;
        RECT  55.968 8.688 56.16 8.712 ;
    END
  END i[67]
  PIN i[68]
    DIRECTION INPUT ;
    USE SIGNAL ;
    PORT
      LAYER M4 ;
        RECT  55.968 8.784 56.16 8.808 ;
    END
  END i[68]
  PIN i[69]
    DIRECTION INPUT ;
    USE SIGNAL ;
    PORT
      LAYER M4 ;
        RECT  55.968 8.88 56.16 8.904 ;
    END
  END i[69]
  PIN i[6]
    DIRECTION INPUT ;
    USE SIGNAL ;
    PORT
      LAYER M4 ;
        RECT  55.968 2.784 56.16 2.808 ;
    END
  END i[6]
  PIN i[70]
    DIRECTION INPUT ;
    USE SIGNAL ;
    PORT
      LAYER M4 ;
        RECT  55.968 8.976 56.16 9 ;
    END
  END i[70]
  PIN i[71]
    DIRECTION INPUT ;
    USE SIGNAL ;
    PORT
      LAYER M4 ;
        RECT  55.968 9.072 56.16 9.096 ;
    END
  END i[71]
  PIN i[72]
    DIRECTION INPUT ;
    USE SIGNAL ;
    PORT
      LAYER M4 ;
        RECT  55.968 9.168 56.16 9.192 ;
    END
  END i[72]
  PIN i[73]
    DIRECTION INPUT ;
    USE SIGNAL ;
    PORT
      LAYER M4 ;
        RECT  55.968 9.264 56.16 9.288 ;
    END
  END i[73]
  PIN i[74]
    DIRECTION INPUT ;
    USE SIGNAL ;
    PORT
      LAYER M4 ;
        RECT  55.968 9.36 56.16 9.384 ;
    END
  END i[74]
  PIN i[75]
    DIRECTION INPUT ;
    USE SIGNAL ;
    PORT
      LAYER M4 ;
        RECT  55.968 9.456 56.16 9.48 ;
    END
  END i[75]
  PIN i[76]
    DIRECTION INPUT ;
    USE SIGNAL ;
    PORT
      LAYER M4 ;
        RECT  55.968 9.552 56.16 9.576 ;
    END
  END i[76]
  PIN i[77]
    DIRECTION INPUT ;
    USE SIGNAL ;
    PORT
      LAYER M4 ;
        RECT  55.968 9.648 56.16 9.672 ;
    END
  END i[77]
  PIN i[78]
    DIRECTION INPUT ;
    USE SIGNAL ;
    PORT
      LAYER M4 ;
        RECT  55.968 9.744 56.16 9.768 ;
    END
  END i[78]
  PIN i[79]
    DIRECTION INPUT ;
    USE SIGNAL ;
    PORT
      LAYER M4 ;
        RECT  55.968 9.84 56.16 9.864 ;
    END
  END i[79]
  PIN i[7]
    DIRECTION INPUT ;
    USE SIGNAL ;
    PORT
      LAYER M4 ;
        RECT  55.968 2.88 56.16 2.904 ;
    END
  END i[7]
  PIN i[80]
    DIRECTION INPUT ;
    USE SIGNAL ;
    PORT
      LAYER M4 ;
        RECT  55.968 9.936 56.16 9.96 ;
    END
  END i[80]
  PIN i[81]
    DIRECTION INPUT ;
    USE SIGNAL ;
    PORT
      LAYER M4 ;
        RECT  55.968 10.032 56.16 10.056 ;
    END
  END i[81]
  PIN i[82]
    DIRECTION INPUT ;
    USE SIGNAL ;
    PORT
      LAYER M4 ;
        RECT  55.968 10.128 56.16 10.152 ;
    END
  END i[82]
  PIN i[83]
    DIRECTION INPUT ;
    USE SIGNAL ;
    PORT
      LAYER M4 ;
        RECT  55.968 10.224 56.16 10.248 ;
    END
  END i[83]
  PIN i[84]
    DIRECTION INPUT ;
    USE SIGNAL ;
    PORT
      LAYER M4 ;
        RECT  55.968 10.368 56.16 10.392 ;
    END
  END i[84]
  PIN i[85]
    DIRECTION INPUT ;
    USE SIGNAL ;
    PORT
      LAYER M4 ;
        RECT  55.968 10.464 56.16 10.488 ;
    END
  END i[85]
  PIN i[86]
    DIRECTION INPUT ;
    USE SIGNAL ;
    PORT
      LAYER M4 ;
        RECT  55.968 10.56 56.16 10.584 ;
    END
  END i[86]
  PIN i[87]
    DIRECTION INPUT ;
    USE SIGNAL ;
    PORT
      LAYER M4 ;
        RECT  55.968 10.656 56.16 10.68 ;
    END
  END i[87]
  PIN i[88]
    DIRECTION INPUT ;
    USE SIGNAL ;
    PORT
      LAYER M4 ;
        RECT  55.968 10.752 56.16 10.776 ;
    END
  END i[88]
  PIN i[89]
    DIRECTION INPUT ;
    USE SIGNAL ;
    PORT
      LAYER M4 ;
        RECT  55.968 10.848 56.16 10.872 ;
    END
  END i[89]
  PIN i[8]
    DIRECTION INPUT ;
    USE SIGNAL ;
    PORT
      LAYER M4 ;
        RECT  55.968 2.976 56.16 3 ;
    END
  END i[8]
  PIN i[90]
    DIRECTION INPUT ;
    USE SIGNAL ;
    PORT
      LAYER M4 ;
        RECT  55.968 10.944 56.16 10.968 ;
    END
  END i[90]
  PIN i[91]
    DIRECTION INPUT ;
    USE SIGNAL ;
    PORT
      LAYER M4 ;
        RECT  55.968 11.04 56.16 11.064 ;
    END
  END i[91]
  PIN i[92]
    DIRECTION INPUT ;
    USE SIGNAL ;
    PORT
      LAYER M4 ;
        RECT  55.968 11.136 56.16 11.16 ;
    END
  END i[92]
  PIN i[93]
    DIRECTION INPUT ;
    USE SIGNAL ;
    PORT
      LAYER M4 ;
        RECT  55.968 11.232 56.16 11.256 ;
    END
  END i[93]
  PIN i[94]
    DIRECTION INPUT ;
    USE SIGNAL ;
    PORT
      LAYER M4 ;
        RECT  55.968 11.328 56.16 11.352 ;
    END
  END i[94]
  PIN i[95]
    DIRECTION INPUT ;
    USE SIGNAL ;
    PORT
      LAYER M4 ;
        RECT  55.968 11.424 56.16 11.448 ;
    END
  END i[95]
  PIN i[96]
    DIRECTION INPUT ;
    USE SIGNAL ;
    PORT
      LAYER M4 ;
        RECT  55.968 11.52 56.16 11.544 ;
    END
  END i[96]
  PIN i[97]
    DIRECTION INPUT ;
    USE SIGNAL ;
    PORT
      LAYER M4 ;
        RECT  55.968 11.616 56.16 11.64 ;
    END
  END i[97]
  PIN i[98]
    DIRECTION INPUT ;
    USE SIGNAL ;
    PORT
      LAYER M4 ;
        RECT  55.968 11.712 56.16 11.736 ;
    END
  END i[98]
  PIN i[99]
    DIRECTION INPUT ;
    USE SIGNAL ;
    PORT
      LAYER M4 ;
        RECT  55.968 11.808 56.16 11.832 ;
    END
  END i[99]
  PIN i[9]
    DIRECTION INPUT ;
    USE SIGNAL ;
    PORT
      LAYER M4 ;
        RECT  55.968 3.072 56.16 3.096 ;
    END
  END i[9]
  PIN o[0]
    DIRECTION OUTPUT ;
    USE SIGNAL ;
    PORT
      LAYER M3 ;
        RECT  2.196 56.016 2.214 56.16 ;
    END
  END o[0]
  PIN o[100]
    DIRECTION OUTPUT ;
    USE SIGNAL ;
    PORT
      LAYER M3 ;
        RECT  11.88 56.016 11.898 56.16 ;
    END
  END o[100]
  PIN o[101]
    DIRECTION OUTPUT ;
    USE SIGNAL ;
    PORT
      LAYER M5 ;
        RECT  11.952 55.968 11.976 56.16 ;
    END
  END o[101]
  PIN o[102]
    DIRECTION OUTPUT ;
    USE SIGNAL ;
    PORT
      LAYER M3 ;
        RECT  12.06 56.016 12.078 56.16 ;
    END
  END o[102]
  PIN o[103]
    DIRECTION OUTPUT ;
    USE SIGNAL ;
    PORT
      LAYER M5 ;
        RECT  12.144 55.968 12.168 56.16 ;
    END
  END o[103]
  PIN o[104]
    DIRECTION OUTPUT ;
    USE SIGNAL ;
    PORT
      LAYER M3 ;
        RECT  12.24 56.016 12.258 56.16 ;
    END
  END o[104]
  PIN o[105]
    DIRECTION OUTPUT ;
    USE SIGNAL ;
    PORT
      LAYER M5 ;
        RECT  12.336 55.968 12.36 56.16 ;
    END
  END o[105]
  PIN o[106]
    DIRECTION OUTPUT ;
    USE SIGNAL ;
    PORT
      LAYER M3 ;
        RECT  12.456 56.016 12.474 56.16 ;
    END
  END o[106]
  PIN o[107]
    DIRECTION OUTPUT ;
    USE SIGNAL ;
    PORT
      LAYER M5 ;
        RECT  12.528 55.968 12.552 56.16 ;
    END
  END o[107]
  PIN o[108]
    DIRECTION OUTPUT ;
    USE SIGNAL ;
    PORT
      LAYER M3 ;
        RECT  12.636 56.016 12.654 56.16 ;
    END
  END o[108]
  PIN o[109]
    DIRECTION OUTPUT ;
    USE SIGNAL ;
    PORT
      LAYER M5 ;
        RECT  12.72 55.968 12.744 56.16 ;
    END
  END o[109]
  PIN o[10]
    DIRECTION OUTPUT ;
    USE SIGNAL ;
    PORT
      LAYER M3 ;
        RECT  3.168 56.016 3.186 56.16 ;
    END
  END o[10]
  PIN o[110]
    DIRECTION OUTPUT ;
    USE SIGNAL ;
    PORT
      LAYER M3 ;
        RECT  12.852 56.016 12.87 56.16 ;
    END
  END o[110]
  PIN o[111]
    DIRECTION OUTPUT ;
    USE SIGNAL ;
    PORT
      LAYER M5 ;
        RECT  12.912 55.968 12.936 56.16 ;
    END
  END o[111]
  PIN o[112]
    DIRECTION OUTPUT ;
    USE SIGNAL ;
    PORT
      LAYER M3 ;
        RECT  13.032 56.016 13.05 56.16 ;
    END
  END o[112]
  PIN o[113]
    DIRECTION OUTPUT ;
    USE SIGNAL ;
    PORT
      LAYER M5 ;
        RECT  13.104 55.968 13.128 56.16 ;
    END
  END o[113]
  PIN o[114]
    DIRECTION OUTPUT ;
    USE SIGNAL ;
    PORT
      LAYER M3 ;
        RECT  13.212 56.016 13.23 56.16 ;
    END
  END o[114]
  PIN o[115]
    DIRECTION OUTPUT ;
    USE SIGNAL ;
    PORT
      LAYER M5 ;
        RECT  13.296 55.968 13.32 56.16 ;
    END
  END o[115]
  PIN o[116]
    DIRECTION OUTPUT ;
    USE SIGNAL ;
    PORT
      LAYER M3 ;
        RECT  13.428 56.016 13.446 56.16 ;
    END
  END o[116]
  PIN o[117]
    DIRECTION OUTPUT ;
    USE SIGNAL ;
    PORT
      LAYER M5 ;
        RECT  13.536 55.968 13.56 56.16 ;
    END
  END o[117]
  PIN o[118]
    DIRECTION OUTPUT ;
    USE SIGNAL ;
    PORT
      LAYER M3 ;
        RECT  13.608 56.016 13.626 56.16 ;
    END
  END o[118]
  PIN o[119]
    DIRECTION OUTPUT ;
    USE SIGNAL ;
    PORT
      LAYER M5 ;
        RECT  13.728 55.968 13.752 56.16 ;
    END
  END o[119]
  PIN o[11]
    DIRECTION OUTPUT ;
    USE SIGNAL ;
    PORT
      LAYER M5 ;
        RECT  3.264 55.968 3.288 56.16 ;
    END
  END o[11]
  PIN o[120]
    DIRECTION OUTPUT ;
    USE SIGNAL ;
    PORT
      LAYER M3 ;
        RECT  13.788 56.016 13.806 56.16 ;
    END
  END o[120]
  PIN o[121]
    DIRECTION OUTPUT ;
    USE SIGNAL ;
    PORT
      LAYER M5 ;
        RECT  13.92 55.968 13.944 56.16 ;
    END
  END o[121]
  PIN o[122]
    DIRECTION OUTPUT ;
    USE SIGNAL ;
    PORT
      LAYER M3 ;
        RECT  14.004 56.016 14.022 56.16 ;
    END
  END o[122]
  PIN o[123]
    DIRECTION OUTPUT ;
    USE SIGNAL ;
    PORT
      LAYER M5 ;
        RECT  14.112 55.968 14.136 56.16 ;
    END
  END o[123]
  PIN o[124]
    DIRECTION OUTPUT ;
    USE SIGNAL ;
    PORT
      LAYER M3 ;
        RECT  14.184 56.016 14.202 56.16 ;
    END
  END o[124]
  PIN o[125]
    DIRECTION OUTPUT ;
    USE SIGNAL ;
    PORT
      LAYER M5 ;
        RECT  14.304 55.968 14.328 56.16 ;
    END
  END o[125]
  PIN o[126]
    DIRECTION OUTPUT ;
    USE SIGNAL ;
    PORT
      LAYER M3 ;
        RECT  14.4 56.016 14.418 56.16 ;
    END
  END o[126]
  PIN o[127]
    DIRECTION OUTPUT ;
    USE SIGNAL ;
    PORT
      LAYER M5 ;
        RECT  14.496 55.968 14.52 56.16 ;
    END
  END o[127]
  PIN o[128]
    DIRECTION OUTPUT ;
    USE SIGNAL ;
    PORT
      LAYER M3 ;
        RECT  14.58 56.016 14.598 56.16 ;
    END
  END o[128]
  PIN o[129]
    DIRECTION OUTPUT ;
    USE SIGNAL ;
    PORT
      LAYER M5 ;
        RECT  14.688 55.968 14.712 56.16 ;
    END
  END o[129]
  PIN o[12]
    DIRECTION OUTPUT ;
    USE SIGNAL ;
    PORT
      LAYER M3 ;
        RECT  3.348 56.016 3.366 56.16 ;
    END
  END o[12]
  PIN o[130]
    DIRECTION OUTPUT ;
    USE SIGNAL ;
    PORT
      LAYER M3 ;
        RECT  14.76 56.016 14.778 56.16 ;
    END
  END o[130]
  PIN o[131]
    DIRECTION OUTPUT ;
    USE SIGNAL ;
    PORT
      LAYER M5 ;
        RECT  14.88 55.968 14.904 56.16 ;
    END
  END o[131]
  PIN o[132]
    DIRECTION OUTPUT ;
    USE SIGNAL ;
    PORT
      LAYER M3 ;
        RECT  14.976 56.016 14.994 56.16 ;
    END
  END o[132]
  PIN o[133]
    DIRECTION OUTPUT ;
    USE SIGNAL ;
    PORT
      LAYER M5 ;
        RECT  15.072 55.968 15.096 56.16 ;
    END
  END o[133]
  PIN o[134]
    DIRECTION OUTPUT ;
    USE SIGNAL ;
    PORT
      LAYER M3 ;
        RECT  15.156 56.016 15.174 56.16 ;
    END
  END o[134]
  PIN o[135]
    DIRECTION OUTPUT ;
    USE SIGNAL ;
    PORT
      LAYER M5 ;
        RECT  15.264 55.968 15.288 56.16 ;
    END
  END o[135]
  PIN o[136]
    DIRECTION OUTPUT ;
    USE SIGNAL ;
    PORT
      LAYER M3 ;
        RECT  15.336 56.016 15.354 56.16 ;
    END
  END o[136]
  PIN o[137]
    DIRECTION OUTPUT ;
    USE SIGNAL ;
    PORT
      LAYER M5 ;
        RECT  15.456 55.968 15.48 56.16 ;
    END
  END o[137]
  PIN o[138]
    DIRECTION OUTPUT ;
    USE SIGNAL ;
    PORT
      LAYER M3 ;
        RECT  15.552 56.016 15.57 56.16 ;
    END
  END o[138]
  PIN o[139]
    DIRECTION OUTPUT ;
    USE SIGNAL ;
    PORT
      LAYER M5 ;
        RECT  15.648 55.968 15.672 56.16 ;
    END
  END o[139]
  PIN o[13]
    DIRECTION OUTPUT ;
    USE SIGNAL ;
    PORT
      LAYER M5 ;
        RECT  3.456 55.968 3.48 56.16 ;
    END
  END o[13]
  PIN o[140]
    DIRECTION OUTPUT ;
    USE SIGNAL ;
    PORT
      LAYER M3 ;
        RECT  15.732 56.016 15.75 56.16 ;
    END
  END o[140]
  PIN o[141]
    DIRECTION OUTPUT ;
    USE SIGNAL ;
    PORT
      LAYER M5 ;
        RECT  15.84 55.968 15.864 56.16 ;
    END
  END o[141]
  PIN o[142]
    DIRECTION OUTPUT ;
    USE SIGNAL ;
    PORT
      LAYER M3 ;
        RECT  15.948 56.016 15.966 56.16 ;
    END
  END o[142]
  PIN o[143]
    DIRECTION OUTPUT ;
    USE SIGNAL ;
    PORT
      LAYER M5 ;
        RECT  16.032 55.968 16.056 56.16 ;
    END
  END o[143]
  PIN o[144]
    DIRECTION OUTPUT ;
    USE SIGNAL ;
    PORT
      LAYER M3 ;
        RECT  16.128 56.016 16.146 56.16 ;
    END
  END o[144]
  PIN o[145]
    DIRECTION OUTPUT ;
    USE SIGNAL ;
    PORT
      LAYER M5 ;
        RECT  16.224 55.968 16.248 56.16 ;
    END
  END o[145]
  PIN o[146]
    DIRECTION OUTPUT ;
    USE SIGNAL ;
    PORT
      LAYER M3 ;
        RECT  16.308 56.016 16.326 56.16 ;
    END
  END o[146]
  PIN o[147]
    DIRECTION OUTPUT ;
    USE SIGNAL ;
    PORT
      LAYER M5 ;
        RECT  16.416 55.968 16.44 56.16 ;
    END
  END o[147]
  PIN o[148]
    DIRECTION OUTPUT ;
    USE SIGNAL ;
    PORT
      LAYER M3 ;
        RECT  16.524 56.016 16.542 56.16 ;
    END
  END o[148]
  PIN o[149]
    DIRECTION OUTPUT ;
    USE SIGNAL ;
    PORT
      LAYER M5 ;
        RECT  16.608 55.968 16.632 56.16 ;
    END
  END o[149]
  PIN o[14]
    DIRECTION OUTPUT ;
    USE SIGNAL ;
    PORT
      LAYER M3 ;
        RECT  3.564 56.016 3.582 56.16 ;
    END
  END o[14]
  PIN o[150]
    DIRECTION OUTPUT ;
    USE SIGNAL ;
    PORT
      LAYER M3 ;
        RECT  16.704 56.016 16.722 56.16 ;
    END
  END o[150]
  PIN o[151]
    DIRECTION OUTPUT ;
    USE SIGNAL ;
    PORT
      LAYER M5 ;
        RECT  16.8 55.968 16.824 56.16 ;
    END
  END o[151]
  PIN o[152]
    DIRECTION OUTPUT ;
    USE SIGNAL ;
    PORT
      LAYER M3 ;
        RECT  16.884 56.016 16.902 56.16 ;
    END
  END o[152]
  PIN o[153]
    DIRECTION OUTPUT ;
    USE SIGNAL ;
    PORT
      LAYER M5 ;
        RECT  16.992 55.968 17.016 56.16 ;
    END
  END o[153]
  PIN o[154]
    DIRECTION OUTPUT ;
    USE SIGNAL ;
    PORT
      LAYER M3 ;
        RECT  17.1 56.016 17.118 56.16 ;
    END
  END o[154]
  PIN o[155]
    DIRECTION OUTPUT ;
    USE SIGNAL ;
    PORT
      LAYER M5 ;
        RECT  17.184 55.968 17.208 56.16 ;
    END
  END o[155]
  PIN o[156]
    DIRECTION OUTPUT ;
    USE SIGNAL ;
    PORT
      LAYER M3 ;
        RECT  17.28 56.016 17.298 56.16 ;
    END
  END o[156]
  PIN o[157]
    DIRECTION OUTPUT ;
    USE SIGNAL ;
    PORT
      LAYER M5 ;
        RECT  17.376 55.968 17.4 56.16 ;
    END
  END o[157]
  PIN o[158]
    DIRECTION OUTPUT ;
    USE SIGNAL ;
    PORT
      LAYER M3 ;
        RECT  17.496 56.016 17.514 56.16 ;
    END
  END o[158]
  PIN o[159]
    DIRECTION OUTPUT ;
    USE SIGNAL ;
    PORT
      LAYER M5 ;
        RECT  17.568 55.968 17.592 56.16 ;
    END
  END o[159]
  PIN o[15]
    DIRECTION OUTPUT ;
    USE SIGNAL ;
    PORT
      LAYER M5 ;
        RECT  3.648 55.968 3.672 56.16 ;
    END
  END o[15]
  PIN o[160]
    DIRECTION OUTPUT ;
    USE SIGNAL ;
    PORT
      LAYER M3 ;
        RECT  17.676 56.016 17.694 56.16 ;
    END
  END o[160]
  PIN o[161]
    DIRECTION OUTPUT ;
    USE SIGNAL ;
    PORT
      LAYER M5 ;
        RECT  17.76 55.968 17.784 56.16 ;
    END
  END o[161]
  PIN o[162]
    DIRECTION OUTPUT ;
    USE SIGNAL ;
    PORT
      LAYER M3 ;
        RECT  17.856 56.016 17.874 56.16 ;
    END
  END o[162]
  PIN o[163]
    DIRECTION OUTPUT ;
    USE SIGNAL ;
    PORT
      LAYER M5 ;
        RECT  17.952 55.968 17.976 56.16 ;
    END
  END o[163]
  PIN o[164]
    DIRECTION OUTPUT ;
    USE SIGNAL ;
    PORT
      LAYER M3 ;
        RECT  18.072 56.016 18.09 56.16 ;
    END
  END o[164]
  PIN o[165]
    DIRECTION OUTPUT ;
    USE SIGNAL ;
    PORT
      LAYER M5 ;
        RECT  18.144 55.968 18.168 56.16 ;
    END
  END o[165]
  PIN o[166]
    DIRECTION OUTPUT ;
    USE SIGNAL ;
    PORT
      LAYER M3 ;
        RECT  18.252 56.016 18.27 56.16 ;
    END
  END o[166]
  PIN o[167]
    DIRECTION OUTPUT ;
    USE SIGNAL ;
    PORT
      LAYER M5 ;
        RECT  18.336 55.968 18.36 56.16 ;
    END
  END o[167]
  PIN o[168]
    DIRECTION OUTPUT ;
    USE SIGNAL ;
    PORT
      LAYER M3 ;
        RECT  18.432 56.016 18.45 56.16 ;
    END
  END o[168]
  PIN o[169]
    DIRECTION OUTPUT ;
    USE SIGNAL ;
    PORT
      LAYER M5 ;
        RECT  18.528 55.968 18.552 56.16 ;
    END
  END o[169]
  PIN o[16]
    DIRECTION OUTPUT ;
    USE SIGNAL ;
    PORT
      LAYER M3 ;
        RECT  3.744 56.016 3.762 56.16 ;
    END
  END o[16]
  PIN o[170]
    DIRECTION OUTPUT ;
    USE SIGNAL ;
    PORT
      LAYER M3 ;
        RECT  18.648 56.016 18.666 56.16 ;
    END
  END o[170]
  PIN o[171]
    DIRECTION OUTPUT ;
    USE SIGNAL ;
    PORT
      LAYER M5 ;
        RECT  18.72 55.968 18.744 56.16 ;
    END
  END o[171]
  PIN o[172]
    DIRECTION OUTPUT ;
    USE SIGNAL ;
    PORT
      LAYER M3 ;
        RECT  18.828 56.016 18.846 56.16 ;
    END
  END o[172]
  PIN o[173]
    DIRECTION OUTPUT ;
    USE SIGNAL ;
    PORT
      LAYER M5 ;
        RECT  18.912 55.968 18.936 56.16 ;
    END
  END o[173]
  PIN o[174]
    DIRECTION OUTPUT ;
    USE SIGNAL ;
    PORT
      LAYER M3 ;
        RECT  19.044 56.016 19.062 56.16 ;
    END
  END o[174]
  PIN o[175]
    DIRECTION OUTPUT ;
    USE SIGNAL ;
    PORT
      LAYER M5 ;
        RECT  19.104 55.968 19.128 56.16 ;
    END
  END o[175]
  PIN o[176]
    DIRECTION OUTPUT ;
    USE SIGNAL ;
    PORT
      LAYER M3 ;
        RECT  19.224 56.016 19.242 56.16 ;
    END
  END o[176]
  PIN o[177]
    DIRECTION OUTPUT ;
    USE SIGNAL ;
    PORT
      LAYER M5 ;
        RECT  19.296 55.968 19.32 56.16 ;
    END
  END o[177]
  PIN o[178]
    DIRECTION OUTPUT ;
    USE SIGNAL ;
    PORT
      LAYER M3 ;
        RECT  19.404 56.016 19.422 56.16 ;
    END
  END o[178]
  PIN o[179]
    DIRECTION OUTPUT ;
    USE SIGNAL ;
    PORT
      LAYER M5 ;
        RECT  19.488 55.968 19.512 56.16 ;
    END
  END o[179]
  PIN o[17]
    DIRECTION OUTPUT ;
    USE SIGNAL ;
    PORT
      LAYER M5 ;
        RECT  3.84 55.968 3.864 56.16 ;
    END
  END o[17]
  PIN o[180]
    DIRECTION OUTPUT ;
    USE SIGNAL ;
    PORT
      LAYER M3 ;
        RECT  19.62 56.016 19.638 56.16 ;
    END
  END o[180]
  PIN o[181]
    DIRECTION OUTPUT ;
    USE SIGNAL ;
    PORT
      LAYER M5 ;
        RECT  19.68 55.968 19.704 56.16 ;
    END
  END o[181]
  PIN o[182]
    DIRECTION OUTPUT ;
    USE SIGNAL ;
    PORT
      LAYER M3 ;
        RECT  19.8 56.016 19.818 56.16 ;
    END
  END o[182]
  PIN o[183]
    DIRECTION OUTPUT ;
    USE SIGNAL ;
    PORT
      LAYER M5 ;
        RECT  19.872 55.968 19.896 56.16 ;
    END
  END o[183]
  PIN o[184]
    DIRECTION OUTPUT ;
    USE SIGNAL ;
    PORT
      LAYER M3 ;
        RECT  19.98 56.016 19.998 56.16 ;
    END
  END o[184]
  PIN o[185]
    DIRECTION OUTPUT ;
    USE SIGNAL ;
    PORT
      LAYER M5 ;
        RECT  20.112 55.968 20.136 56.16 ;
    END
  END o[185]
  PIN o[186]
    DIRECTION OUTPUT ;
    USE SIGNAL ;
    PORT
      LAYER M3 ;
        RECT  20.196 56.016 20.214 56.16 ;
    END
  END o[186]
  PIN o[187]
    DIRECTION OUTPUT ;
    USE SIGNAL ;
    PORT
      LAYER M5 ;
        RECT  20.304 55.968 20.328 56.16 ;
    END
  END o[187]
  PIN o[188]
    DIRECTION OUTPUT ;
    USE SIGNAL ;
    PORT
      LAYER M3 ;
        RECT  20.376 56.016 20.394 56.16 ;
    END
  END o[188]
  PIN o[189]
    DIRECTION OUTPUT ;
    USE SIGNAL ;
    PORT
      LAYER M5 ;
        RECT  20.496 55.968 20.52 56.16 ;
    END
  END o[189]
  PIN o[18]
    DIRECTION OUTPUT ;
    USE SIGNAL ;
    PORT
      LAYER M3 ;
        RECT  3.924 56.016 3.942 56.16 ;
    END
  END o[18]
  PIN o[190]
    DIRECTION OUTPUT ;
    USE SIGNAL ;
    PORT
      LAYER M3 ;
        RECT  20.592 56.016 20.61 56.16 ;
    END
  END o[190]
  PIN o[191]
    DIRECTION OUTPUT ;
    USE SIGNAL ;
    PORT
      LAYER M5 ;
        RECT  20.688 55.968 20.712 56.16 ;
    END
  END o[191]
  PIN o[192]
    DIRECTION OUTPUT ;
    USE SIGNAL ;
    PORT
      LAYER M3 ;
        RECT  20.772 56.016 20.79 56.16 ;
    END
  END o[192]
  PIN o[193]
    DIRECTION OUTPUT ;
    USE SIGNAL ;
    PORT
      LAYER M5 ;
        RECT  20.88 55.968 20.904 56.16 ;
    END
  END o[193]
  PIN o[194]
    DIRECTION OUTPUT ;
    USE SIGNAL ;
    PORT
      LAYER M3 ;
        RECT  20.952 56.016 20.97 56.16 ;
    END
  END o[194]
  PIN o[195]
    DIRECTION OUTPUT ;
    USE SIGNAL ;
    PORT
      LAYER M5 ;
        RECT  21.072 55.968 21.096 56.16 ;
    END
  END o[195]
  PIN o[196]
    DIRECTION OUTPUT ;
    USE SIGNAL ;
    PORT
      LAYER M3 ;
        RECT  21.168 56.016 21.186 56.16 ;
    END
  END o[196]
  PIN o[197]
    DIRECTION OUTPUT ;
    USE SIGNAL ;
    PORT
      LAYER M5 ;
        RECT  21.264 55.968 21.288 56.16 ;
    END
  END o[197]
  PIN o[198]
    DIRECTION OUTPUT ;
    USE SIGNAL ;
    PORT
      LAYER M3 ;
        RECT  21.348 56.016 21.366 56.16 ;
    END
  END o[198]
  PIN o[199]
    DIRECTION OUTPUT ;
    USE SIGNAL ;
    PORT
      LAYER M5 ;
        RECT  21.456 55.968 21.48 56.16 ;
    END
  END o[199]
  PIN o[19]
    DIRECTION OUTPUT ;
    USE SIGNAL ;
    PORT
      LAYER M5 ;
        RECT  4.032 55.968 4.056 56.16 ;
    END
  END o[19]
  PIN o[1]
    DIRECTION OUTPUT ;
    USE SIGNAL ;
    PORT
      LAYER M5 ;
        RECT  2.304 55.968 2.328 56.16 ;
    END
  END o[1]
  PIN o[200]
    DIRECTION OUTPUT ;
    USE SIGNAL ;
    PORT
      LAYER M3 ;
        RECT  21.528 56.016 21.546 56.16 ;
    END
  END o[200]
  PIN o[201]
    DIRECTION OUTPUT ;
    USE SIGNAL ;
    PORT
      LAYER M5 ;
        RECT  21.648 55.968 21.672 56.16 ;
    END
  END o[201]
  PIN o[202]
    DIRECTION OUTPUT ;
    USE SIGNAL ;
    PORT
      LAYER M3 ;
        RECT  21.744 56.016 21.762 56.16 ;
    END
  END o[202]
  PIN o[203]
    DIRECTION OUTPUT ;
    USE SIGNAL ;
    PORT
      LAYER M5 ;
        RECT  21.84 55.968 21.864 56.16 ;
    END
  END o[203]
  PIN o[204]
    DIRECTION OUTPUT ;
    USE SIGNAL ;
    PORT
      LAYER M3 ;
        RECT  21.924 56.016 21.942 56.16 ;
    END
  END o[204]
  PIN o[205]
    DIRECTION OUTPUT ;
    USE SIGNAL ;
    PORT
      LAYER M5 ;
        RECT  22.032 55.968 22.056 56.16 ;
    END
  END o[205]
  PIN o[206]
    DIRECTION OUTPUT ;
    USE SIGNAL ;
    PORT
      LAYER M3 ;
        RECT  22.14 56.016 22.158 56.16 ;
    END
  END o[206]
  PIN o[207]
    DIRECTION OUTPUT ;
    USE SIGNAL ;
    PORT
      LAYER M5 ;
        RECT  22.224 55.968 22.248 56.16 ;
    END
  END o[207]
  PIN o[208]
    DIRECTION OUTPUT ;
    USE SIGNAL ;
    PORT
      LAYER M3 ;
        RECT  22.32 56.016 22.338 56.16 ;
    END
  END o[208]
  PIN o[209]
    DIRECTION OUTPUT ;
    USE SIGNAL ;
    PORT
      LAYER M5 ;
        RECT  22.416 55.968 22.44 56.16 ;
    END
  END o[209]
  PIN o[20]
    DIRECTION OUTPUT ;
    USE SIGNAL ;
    PORT
      LAYER M3 ;
        RECT  4.14 56.016 4.158 56.16 ;
    END
  END o[20]
  PIN o[210]
    DIRECTION OUTPUT ;
    USE SIGNAL ;
    PORT
      LAYER M3 ;
        RECT  22.5 56.016 22.518 56.16 ;
    END
  END o[210]
  PIN o[211]
    DIRECTION OUTPUT ;
    USE SIGNAL ;
    PORT
      LAYER M5 ;
        RECT  22.608 55.968 22.632 56.16 ;
    END
  END o[211]
  PIN o[212]
    DIRECTION OUTPUT ;
    USE SIGNAL ;
    PORT
      LAYER M3 ;
        RECT  22.716 56.016 22.734 56.16 ;
    END
  END o[212]
  PIN o[213]
    DIRECTION OUTPUT ;
    USE SIGNAL ;
    PORT
      LAYER M5 ;
        RECT  22.8 55.968 22.824 56.16 ;
    END
  END o[213]
  PIN o[214]
    DIRECTION OUTPUT ;
    USE SIGNAL ;
    PORT
      LAYER M3 ;
        RECT  22.896 56.016 22.914 56.16 ;
    END
  END o[214]
  PIN o[215]
    DIRECTION OUTPUT ;
    USE SIGNAL ;
    PORT
      LAYER M5 ;
        RECT  22.992 55.968 23.016 56.16 ;
    END
  END o[215]
  PIN o[216]
    DIRECTION OUTPUT ;
    USE SIGNAL ;
    PORT
      LAYER M3 ;
        RECT  23.076 56.016 23.094 56.16 ;
    END
  END o[216]
  PIN o[217]
    DIRECTION OUTPUT ;
    USE SIGNAL ;
    PORT
      LAYER M5 ;
        RECT  23.184 55.968 23.208 56.16 ;
    END
  END o[217]
  PIN o[218]
    DIRECTION OUTPUT ;
    USE SIGNAL ;
    PORT
      LAYER M3 ;
        RECT  23.292 56.016 23.31 56.16 ;
    END
  END o[218]
  PIN o[219]
    DIRECTION OUTPUT ;
    USE SIGNAL ;
    PORT
      LAYER M5 ;
        RECT  23.376 55.968 23.4 56.16 ;
    END
  END o[219]
  PIN o[21]
    DIRECTION OUTPUT ;
    USE SIGNAL ;
    PORT
      LAYER M5 ;
        RECT  4.224 55.968 4.248 56.16 ;
    END
  END o[21]
  PIN o[220]
    DIRECTION OUTPUT ;
    USE SIGNAL ;
    PORT
      LAYER M3 ;
        RECT  23.472 56.016 23.49 56.16 ;
    END
  END o[220]
  PIN o[221]
    DIRECTION OUTPUT ;
    USE SIGNAL ;
    PORT
      LAYER M5 ;
        RECT  23.568 55.968 23.592 56.16 ;
    END
  END o[221]
  PIN o[222]
    DIRECTION OUTPUT ;
    USE SIGNAL ;
    PORT
      LAYER M3 ;
        RECT  23.688 56.016 23.706 56.16 ;
    END
  END o[222]
  PIN o[223]
    DIRECTION OUTPUT ;
    USE SIGNAL ;
    PORT
      LAYER M5 ;
        RECT  23.76 55.968 23.784 56.16 ;
    END
  END o[223]
  PIN o[224]
    DIRECTION OUTPUT ;
    USE SIGNAL ;
    PORT
      LAYER M3 ;
        RECT  23.868 56.016 23.886 56.16 ;
    END
  END o[224]
  PIN o[225]
    DIRECTION OUTPUT ;
    USE SIGNAL ;
    PORT
      LAYER M5 ;
        RECT  23.952 55.968 23.976 56.16 ;
    END
  END o[225]
  PIN o[226]
    DIRECTION OUTPUT ;
    USE SIGNAL ;
    PORT
      LAYER M3 ;
        RECT  24.048 56.016 24.066 56.16 ;
    END
  END o[226]
  PIN o[227]
    DIRECTION OUTPUT ;
    USE SIGNAL ;
    PORT
      LAYER M5 ;
        RECT  24.144 55.968 24.168 56.16 ;
    END
  END o[227]
  PIN o[228]
    DIRECTION OUTPUT ;
    USE SIGNAL ;
    PORT
      LAYER M3 ;
        RECT  24.264 56.016 24.282 56.16 ;
    END
  END o[228]
  PIN o[229]
    DIRECTION OUTPUT ;
    USE SIGNAL ;
    PORT
      LAYER M5 ;
        RECT  24.336 55.968 24.36 56.16 ;
    END
  END o[229]
  PIN o[22]
    DIRECTION OUTPUT ;
    USE SIGNAL ;
    PORT
      LAYER M3 ;
        RECT  4.32 56.016 4.338 56.16 ;
    END
  END o[22]
  PIN o[230]
    DIRECTION OUTPUT ;
    USE SIGNAL ;
    PORT
      LAYER M3 ;
        RECT  24.444 56.016 24.462 56.16 ;
    END
  END o[230]
  PIN o[231]
    DIRECTION OUTPUT ;
    USE SIGNAL ;
    PORT
      LAYER M5 ;
        RECT  24.528 55.968 24.552 56.16 ;
    END
  END o[231]
  PIN o[232]
    DIRECTION OUTPUT ;
    USE SIGNAL ;
    PORT
      LAYER M3 ;
        RECT  24.624 56.016 24.642 56.16 ;
    END
  END o[232]
  PIN o[233]
    DIRECTION OUTPUT ;
    USE SIGNAL ;
    PORT
      LAYER M5 ;
        RECT  24.72 55.968 24.744 56.16 ;
    END
  END o[233]
  PIN o[234]
    DIRECTION OUTPUT ;
    USE SIGNAL ;
    PORT
      LAYER M3 ;
        RECT  24.84 56.016 24.858 56.16 ;
    END
  END o[234]
  PIN o[235]
    DIRECTION OUTPUT ;
    USE SIGNAL ;
    PORT
      LAYER M5 ;
        RECT  24.912 55.968 24.936 56.16 ;
    END
  END o[235]
  PIN o[236]
    DIRECTION OUTPUT ;
    USE SIGNAL ;
    PORT
      LAYER M3 ;
        RECT  25.02 56.016 25.038 56.16 ;
    END
  END o[236]
  PIN o[237]
    DIRECTION OUTPUT ;
    USE SIGNAL ;
    PORT
      LAYER M5 ;
        RECT  25.104 55.968 25.128 56.16 ;
    END
  END o[237]
  PIN o[238]
    DIRECTION OUTPUT ;
    USE SIGNAL ;
    PORT
      LAYER M3 ;
        RECT  25.2 56.016 25.218 56.16 ;
    END
  END o[238]
  PIN o[239]
    DIRECTION OUTPUT ;
    USE SIGNAL ;
    PORT
      LAYER M5 ;
        RECT  25.296 55.968 25.32 56.16 ;
    END
  END o[239]
  PIN o[23]
    DIRECTION OUTPUT ;
    USE SIGNAL ;
    PORT
      LAYER M5 ;
        RECT  4.416 55.968 4.44 56.16 ;
    END
  END o[23]
  PIN o[240]
    DIRECTION OUTPUT ;
    USE SIGNAL ;
    PORT
      LAYER M3 ;
        RECT  25.416 56.016 25.434 56.16 ;
    END
  END o[240]
  PIN o[241]
    DIRECTION OUTPUT ;
    USE SIGNAL ;
    PORT
      LAYER M5 ;
        RECT  25.488 55.968 25.512 56.16 ;
    END
  END o[241]
  PIN o[242]
    DIRECTION OUTPUT ;
    USE SIGNAL ;
    PORT
      LAYER M3 ;
        RECT  25.596 56.016 25.614 56.16 ;
    END
  END o[242]
  PIN o[243]
    DIRECTION OUTPUT ;
    USE SIGNAL ;
    PORT
      LAYER M5 ;
        RECT  25.68 55.968 25.704 56.16 ;
    END
  END o[243]
  PIN o[244]
    DIRECTION OUTPUT ;
    USE SIGNAL ;
    PORT
      LAYER M3 ;
        RECT  25.812 56.016 25.83 56.16 ;
    END
  END o[244]
  PIN o[245]
    DIRECTION OUTPUT ;
    USE SIGNAL ;
    PORT
      LAYER M5 ;
        RECT  25.872 55.968 25.896 56.16 ;
    END
  END o[245]
  PIN o[246]
    DIRECTION OUTPUT ;
    USE SIGNAL ;
    PORT
      LAYER M3 ;
        RECT  25.992 56.016 26.01 56.16 ;
    END
  END o[246]
  PIN o[247]
    DIRECTION OUTPUT ;
    USE SIGNAL ;
    PORT
      LAYER M5 ;
        RECT  26.064 55.968 26.088 56.16 ;
    END
  END o[247]
  PIN o[248]
    DIRECTION OUTPUT ;
    USE SIGNAL ;
    PORT
      LAYER M3 ;
        RECT  26.172 56.016 26.19 56.16 ;
    END
  END o[248]
  PIN o[249]
    DIRECTION OUTPUT ;
    USE SIGNAL ;
    PORT
      LAYER M5 ;
        RECT  26.256 55.968 26.28 56.16 ;
    END
  END o[249]
  PIN o[24]
    DIRECTION OUTPUT ;
    USE SIGNAL ;
    PORT
      LAYER M3 ;
        RECT  4.536 56.016 4.554 56.16 ;
    END
  END o[24]
  PIN o[250]
    DIRECTION OUTPUT ;
    USE SIGNAL ;
    PORT
      LAYER M3 ;
        RECT  26.388 56.016 26.406 56.16 ;
    END
  END o[250]
  PIN o[251]
    DIRECTION OUTPUT ;
    USE SIGNAL ;
    PORT
      LAYER M5 ;
        RECT  26.496 55.968 26.52 56.16 ;
    END
  END o[251]
  PIN o[252]
    DIRECTION OUTPUT ;
    USE SIGNAL ;
    PORT
      LAYER M3 ;
        RECT  26.568 56.016 26.586 56.16 ;
    END
  END o[252]
  PIN o[253]
    DIRECTION OUTPUT ;
    USE SIGNAL ;
    PORT
      LAYER M5 ;
        RECT  26.688 55.968 26.712 56.16 ;
    END
  END o[253]
  PIN o[254]
    DIRECTION OUTPUT ;
    USE SIGNAL ;
    PORT
      LAYER M3 ;
        RECT  26.748 56.016 26.766 56.16 ;
    END
  END o[254]
  PIN o[255]
    DIRECTION OUTPUT ;
    USE SIGNAL ;
    PORT
      LAYER M5 ;
        RECT  26.88 55.968 26.904 56.16 ;
    END
  END o[255]
  PIN o[256]
    DIRECTION OUTPUT ;
    USE SIGNAL ;
    PORT
      LAYER M3 ;
        RECT  26.964 56.016 26.982 56.16 ;
    END
  END o[256]
  PIN o[257]
    DIRECTION OUTPUT ;
    USE SIGNAL ;
    PORT
      LAYER M5 ;
        RECT  27.072 55.968 27.096 56.16 ;
    END
  END o[257]
  PIN o[258]
    DIRECTION OUTPUT ;
    USE SIGNAL ;
    PORT
      LAYER M3 ;
        RECT  27.144 56.016 27.162 56.16 ;
    END
  END o[258]
  PIN o[259]
    DIRECTION OUTPUT ;
    USE SIGNAL ;
    PORT
      LAYER M5 ;
        RECT  27.264 55.968 27.288 56.16 ;
    END
  END o[259]
  PIN o[25]
    DIRECTION OUTPUT ;
    USE SIGNAL ;
    PORT
      LAYER M5 ;
        RECT  4.608 55.968 4.632 56.16 ;
    END
  END o[25]
  PIN o[260]
    DIRECTION OUTPUT ;
    USE SIGNAL ;
    PORT
      LAYER M3 ;
        RECT  27.36 56.016 27.378 56.16 ;
    END
  END o[260]
  PIN o[261]
    DIRECTION OUTPUT ;
    USE SIGNAL ;
    PORT
      LAYER M5 ;
        RECT  27.456 55.968 27.48 56.16 ;
    END
  END o[261]
  PIN o[262]
    DIRECTION OUTPUT ;
    USE SIGNAL ;
    PORT
      LAYER M3 ;
        RECT  27.54 56.016 27.558 56.16 ;
    END
  END o[262]
  PIN o[263]
    DIRECTION OUTPUT ;
    USE SIGNAL ;
    PORT
      LAYER M5 ;
        RECT  27.648 55.968 27.672 56.16 ;
    END
  END o[263]
  PIN o[264]
    DIRECTION OUTPUT ;
    USE SIGNAL ;
    PORT
      LAYER M3 ;
        RECT  27.72 56.016 27.738 56.16 ;
    END
  END o[264]
  PIN o[265]
    DIRECTION OUTPUT ;
    USE SIGNAL ;
    PORT
      LAYER M5 ;
        RECT  27.84 55.968 27.864 56.16 ;
    END
  END o[265]
  PIN o[266]
    DIRECTION OUTPUT ;
    USE SIGNAL ;
    PORT
      LAYER M3 ;
        RECT  27.936 56.016 27.954 56.16 ;
    END
  END o[266]
  PIN o[267]
    DIRECTION OUTPUT ;
    USE SIGNAL ;
    PORT
      LAYER M5 ;
        RECT  28.032 55.968 28.056 56.16 ;
    END
  END o[267]
  PIN o[268]
    DIRECTION OUTPUT ;
    USE SIGNAL ;
    PORT
      LAYER M3 ;
        RECT  28.116 56.016 28.134 56.16 ;
    END
  END o[268]
  PIN o[269]
    DIRECTION OUTPUT ;
    USE SIGNAL ;
    PORT
      LAYER M5 ;
        RECT  28.224 55.968 28.248 56.16 ;
    END
  END o[269]
  PIN o[26]
    DIRECTION OUTPUT ;
    USE SIGNAL ;
    PORT
      LAYER M3 ;
        RECT  4.716 56.016 4.734 56.16 ;
    END
  END o[26]
  PIN o[270]
    DIRECTION OUTPUT ;
    USE SIGNAL ;
    PORT
      LAYER M3 ;
        RECT  28.296 56.016 28.314 56.16 ;
    END
  END o[270]
  PIN o[271]
    DIRECTION OUTPUT ;
    USE SIGNAL ;
    PORT
      LAYER M5 ;
        RECT  28.416 55.968 28.44 56.16 ;
    END
  END o[271]
  PIN o[272]
    DIRECTION OUTPUT ;
    USE SIGNAL ;
    PORT
      LAYER M3 ;
        RECT  28.512 56.016 28.53 56.16 ;
    END
  END o[272]
  PIN o[273]
    DIRECTION OUTPUT ;
    USE SIGNAL ;
    PORT
      LAYER M5 ;
        RECT  28.608 55.968 28.632 56.16 ;
    END
  END o[273]
  PIN o[274]
    DIRECTION OUTPUT ;
    USE SIGNAL ;
    PORT
      LAYER M3 ;
        RECT  28.692 56.016 28.71 56.16 ;
    END
  END o[274]
  PIN o[275]
    DIRECTION OUTPUT ;
    USE SIGNAL ;
    PORT
      LAYER M5 ;
        RECT  28.8 55.968 28.824 56.16 ;
    END
  END o[275]
  PIN o[276]
    DIRECTION OUTPUT ;
    USE SIGNAL ;
    PORT
      LAYER M3 ;
        RECT  28.908 56.016 28.926 56.16 ;
    END
  END o[276]
  PIN o[277]
    DIRECTION OUTPUT ;
    USE SIGNAL ;
    PORT
      LAYER M5 ;
        RECT  28.992 55.968 29.016 56.16 ;
    END
  END o[277]
  PIN o[278]
    DIRECTION OUTPUT ;
    USE SIGNAL ;
    PORT
      LAYER M3 ;
        RECT  29.088 56.016 29.106 56.16 ;
    END
  END o[278]
  PIN o[279]
    DIRECTION OUTPUT ;
    USE SIGNAL ;
    PORT
      LAYER M5 ;
        RECT  29.184 55.968 29.208 56.16 ;
    END
  END o[279]
  PIN o[27]
    DIRECTION OUTPUT ;
    USE SIGNAL ;
    PORT
      LAYER M5 ;
        RECT  4.8 55.968 4.824 56.16 ;
    END
  END o[27]
  PIN o[280]
    DIRECTION OUTPUT ;
    USE SIGNAL ;
    PORT
      LAYER M3 ;
        RECT  29.268 56.016 29.286 56.16 ;
    END
  END o[280]
  PIN o[281]
    DIRECTION OUTPUT ;
    USE SIGNAL ;
    PORT
      LAYER M5 ;
        RECT  29.376 55.968 29.4 56.16 ;
    END
  END o[281]
  PIN o[282]
    DIRECTION OUTPUT ;
    USE SIGNAL ;
    PORT
      LAYER M3 ;
        RECT  29.484 56.016 29.502 56.16 ;
    END
  END o[282]
  PIN o[283]
    DIRECTION OUTPUT ;
    USE SIGNAL ;
    PORT
      LAYER M5 ;
        RECT  29.568 55.968 29.592 56.16 ;
    END
  END o[283]
  PIN o[284]
    DIRECTION OUTPUT ;
    USE SIGNAL ;
    PORT
      LAYER M3 ;
        RECT  29.664 56.016 29.682 56.16 ;
    END
  END o[284]
  PIN o[285]
    DIRECTION OUTPUT ;
    USE SIGNAL ;
    PORT
      LAYER M5 ;
        RECT  29.76 55.968 29.784 56.16 ;
    END
  END o[285]
  PIN o[286]
    DIRECTION OUTPUT ;
    USE SIGNAL ;
    PORT
      LAYER M3 ;
        RECT  29.844 56.016 29.862 56.16 ;
    END
  END o[286]
  PIN o[287]
    DIRECTION OUTPUT ;
    USE SIGNAL ;
    PORT
      LAYER M5 ;
        RECT  29.952 55.968 29.976 56.16 ;
    END
  END o[287]
  PIN o[288]
    DIRECTION OUTPUT ;
    USE SIGNAL ;
    PORT
      LAYER M3 ;
        RECT  30.06 56.016 30.078 56.16 ;
    END
  END o[288]
  PIN o[289]
    DIRECTION OUTPUT ;
    USE SIGNAL ;
    PORT
      LAYER M5 ;
        RECT  30.144 55.968 30.168 56.16 ;
    END
  END o[289]
  PIN o[28]
    DIRECTION OUTPUT ;
    USE SIGNAL ;
    PORT
      LAYER M3 ;
        RECT  4.896 56.016 4.914 56.16 ;
    END
  END o[28]
  PIN o[290]
    DIRECTION OUTPUT ;
    USE SIGNAL ;
    PORT
      LAYER M3 ;
        RECT  30.24 56.016 30.258 56.16 ;
    END
  END o[290]
  PIN o[291]
    DIRECTION OUTPUT ;
    USE SIGNAL ;
    PORT
      LAYER M5 ;
        RECT  30.336 55.968 30.36 56.16 ;
    END
  END o[291]
  PIN o[292]
    DIRECTION OUTPUT ;
    USE SIGNAL ;
    PORT
      LAYER M3 ;
        RECT  30.456 56.016 30.474 56.16 ;
    END
  END o[292]
  PIN o[293]
    DIRECTION OUTPUT ;
    USE SIGNAL ;
    PORT
      LAYER M5 ;
        RECT  30.528 55.968 30.552 56.16 ;
    END
  END o[293]
  PIN o[294]
    DIRECTION OUTPUT ;
    USE SIGNAL ;
    PORT
      LAYER M3 ;
        RECT  30.636 56.016 30.654 56.16 ;
    END
  END o[294]
  PIN o[295]
    DIRECTION OUTPUT ;
    USE SIGNAL ;
    PORT
      LAYER M5 ;
        RECT  30.72 55.968 30.744 56.16 ;
    END
  END o[295]
  PIN o[296]
    DIRECTION OUTPUT ;
    USE SIGNAL ;
    PORT
      LAYER M3 ;
        RECT  30.816 56.016 30.834 56.16 ;
    END
  END o[296]
  PIN o[297]
    DIRECTION OUTPUT ;
    USE SIGNAL ;
    PORT
      LAYER M5 ;
        RECT  30.912 55.968 30.936 56.16 ;
    END
  END o[297]
  PIN o[298]
    DIRECTION OUTPUT ;
    USE SIGNAL ;
    PORT
      LAYER M3 ;
        RECT  31.032 56.016 31.05 56.16 ;
    END
  END o[298]
  PIN o[299]
    DIRECTION OUTPUT ;
    USE SIGNAL ;
    PORT
      LAYER M5 ;
        RECT  31.104 55.968 31.128 56.16 ;
    END
  END o[299]
  PIN o[29]
    DIRECTION OUTPUT ;
    USE SIGNAL ;
    PORT
      LAYER M5 ;
        RECT  4.992 55.968 5.016 56.16 ;
    END
  END o[29]
  PIN o[2]
    DIRECTION OUTPUT ;
    USE SIGNAL ;
    PORT
      LAYER M3 ;
        RECT  2.376 56.016 2.394 56.16 ;
    END
  END o[2]
  PIN o[300]
    DIRECTION OUTPUT ;
    USE SIGNAL ;
    PORT
      LAYER M3 ;
        RECT  31.212 56.016 31.23 56.16 ;
    END
  END o[300]
  PIN o[301]
    DIRECTION OUTPUT ;
    USE SIGNAL ;
    PORT
      LAYER M5 ;
        RECT  31.296 55.968 31.32 56.16 ;
    END
  END o[301]
  PIN o[302]
    DIRECTION OUTPUT ;
    USE SIGNAL ;
    PORT
      LAYER M3 ;
        RECT  31.392 56.016 31.41 56.16 ;
    END
  END o[302]
  PIN o[303]
    DIRECTION OUTPUT ;
    USE SIGNAL ;
    PORT
      LAYER M5 ;
        RECT  31.488 55.968 31.512 56.16 ;
    END
  END o[303]
  PIN o[304]
    DIRECTION OUTPUT ;
    USE SIGNAL ;
    PORT
      LAYER M3 ;
        RECT  31.608 56.016 31.626 56.16 ;
    END
  END o[304]
  PIN o[305]
    DIRECTION OUTPUT ;
    USE SIGNAL ;
    PORT
      LAYER M5 ;
        RECT  31.68 55.968 31.704 56.16 ;
    END
  END o[305]
  PIN o[306]
    DIRECTION OUTPUT ;
    USE SIGNAL ;
    PORT
      LAYER M3 ;
        RECT  31.788 56.016 31.806 56.16 ;
    END
  END o[306]
  PIN o[307]
    DIRECTION OUTPUT ;
    USE SIGNAL ;
    PORT
      LAYER M5 ;
        RECT  31.872 55.968 31.896 56.16 ;
    END
  END o[307]
  PIN o[308]
    DIRECTION OUTPUT ;
    USE SIGNAL ;
    PORT
      LAYER M3 ;
        RECT  32.004 56.016 32.022 56.16 ;
    END
  END o[308]
  PIN o[309]
    DIRECTION OUTPUT ;
    USE SIGNAL ;
    PORT
      LAYER M5 ;
        RECT  32.064 55.968 32.088 56.16 ;
    END
  END o[309]
  PIN o[30]
    DIRECTION OUTPUT ;
    USE SIGNAL ;
    PORT
      LAYER M3 ;
        RECT  5.112 56.016 5.13 56.16 ;
    END
  END o[30]
  PIN o[310]
    DIRECTION OUTPUT ;
    USE SIGNAL ;
    PORT
      LAYER M3 ;
        RECT  32.184 56.016 32.202 56.16 ;
    END
  END o[310]
  PIN o[311]
    DIRECTION OUTPUT ;
    USE SIGNAL ;
    PORT
      LAYER M5 ;
        RECT  32.256 55.968 32.28 56.16 ;
    END
  END o[311]
  PIN o[312]
    DIRECTION OUTPUT ;
    USE SIGNAL ;
    PORT
      LAYER M3 ;
        RECT  32.364 56.016 32.382 56.16 ;
    END
  END o[312]
  PIN o[313]
    DIRECTION OUTPUT ;
    USE SIGNAL ;
    PORT
      LAYER M5 ;
        RECT  32.448 55.968 32.472 56.16 ;
    END
  END o[313]
  PIN o[314]
    DIRECTION OUTPUT ;
    USE SIGNAL ;
    PORT
      LAYER M3 ;
        RECT  32.58 56.016 32.598 56.16 ;
    END
  END o[314]
  PIN o[315]
    DIRECTION OUTPUT ;
    USE SIGNAL ;
    PORT
      LAYER M5 ;
        RECT  32.64 55.968 32.664 56.16 ;
    END
  END o[315]
  PIN o[316]
    DIRECTION OUTPUT ;
    USE SIGNAL ;
    PORT
      LAYER M3 ;
        RECT  32.76 56.016 32.778 56.16 ;
    END
  END o[316]
  PIN o[317]
    DIRECTION OUTPUT ;
    USE SIGNAL ;
    PORT
      LAYER M5 ;
        RECT  32.832 55.968 32.856 56.16 ;
    END
  END o[317]
  PIN o[318]
    DIRECTION OUTPUT ;
    USE SIGNAL ;
    PORT
      LAYER M3 ;
        RECT  32.94 56.016 32.958 56.16 ;
    END
  END o[318]
  PIN o[319]
    DIRECTION OUTPUT ;
    USE SIGNAL ;
    PORT
      LAYER M5 ;
        RECT  33.072 55.968 33.096 56.16 ;
    END
  END o[319]
  PIN o[31]
    DIRECTION OUTPUT ;
    USE SIGNAL ;
    PORT
      LAYER M5 ;
        RECT  5.184 55.968 5.208 56.16 ;
    END
  END o[31]
  PIN o[320]
    DIRECTION OUTPUT ;
    USE SIGNAL ;
    PORT
      LAYER M3 ;
        RECT  33.156 56.016 33.174 56.16 ;
    END
  END o[320]
  PIN o[321]
    DIRECTION OUTPUT ;
    USE SIGNAL ;
    PORT
      LAYER M5 ;
        RECT  33.264 55.968 33.288 56.16 ;
    END
  END o[321]
  PIN o[322]
    DIRECTION OUTPUT ;
    USE SIGNAL ;
    PORT
      LAYER M3 ;
        RECT  33.336 56.016 33.354 56.16 ;
    END
  END o[322]
  PIN o[323]
    DIRECTION OUTPUT ;
    USE SIGNAL ;
    PORT
      LAYER M5 ;
        RECT  33.456 55.968 33.48 56.16 ;
    END
  END o[323]
  PIN o[324]
    DIRECTION OUTPUT ;
    USE SIGNAL ;
    PORT
      LAYER M3 ;
        RECT  33.552 56.016 33.57 56.16 ;
    END
  END o[324]
  PIN o[325]
    DIRECTION OUTPUT ;
    USE SIGNAL ;
    PORT
      LAYER M5 ;
        RECT  33.648 55.968 33.672 56.16 ;
    END
  END o[325]
  PIN o[326]
    DIRECTION OUTPUT ;
    USE SIGNAL ;
    PORT
      LAYER M3 ;
        RECT  33.732 56.016 33.75 56.16 ;
    END
  END o[326]
  PIN o[327]
    DIRECTION OUTPUT ;
    USE SIGNAL ;
    PORT
      LAYER M5 ;
        RECT  33.84 55.968 33.864 56.16 ;
    END
  END o[327]
  PIN o[328]
    DIRECTION OUTPUT ;
    USE SIGNAL ;
    PORT
      LAYER M3 ;
        RECT  33.912 56.016 33.93 56.16 ;
    END
  END o[328]
  PIN o[329]
    DIRECTION OUTPUT ;
    USE SIGNAL ;
    PORT
      LAYER M5 ;
        RECT  34.032 55.968 34.056 56.16 ;
    END
  END o[329]
  PIN o[32]
    DIRECTION OUTPUT ;
    USE SIGNAL ;
    PORT
      LAYER M3 ;
        RECT  5.292 56.016 5.31 56.16 ;
    END
  END o[32]
  PIN o[330]
    DIRECTION OUTPUT ;
    USE SIGNAL ;
    PORT
      LAYER M3 ;
        RECT  34.128 56.016 34.146 56.16 ;
    END
  END o[330]
  PIN o[331]
    DIRECTION OUTPUT ;
    USE SIGNAL ;
    PORT
      LAYER M5 ;
        RECT  34.224 55.968 34.248 56.16 ;
    END
  END o[331]
  PIN o[332]
    DIRECTION OUTPUT ;
    USE SIGNAL ;
    PORT
      LAYER M3 ;
        RECT  34.308 56.016 34.326 56.16 ;
    END
  END o[332]
  PIN o[333]
    DIRECTION OUTPUT ;
    USE SIGNAL ;
    PORT
      LAYER M5 ;
        RECT  34.416 55.968 34.44 56.16 ;
    END
  END o[333]
  PIN o[334]
    DIRECTION OUTPUT ;
    USE SIGNAL ;
    PORT
      LAYER M3 ;
        RECT  34.488 56.016 34.506 56.16 ;
    END
  END o[334]
  PIN o[335]
    DIRECTION OUTPUT ;
    USE SIGNAL ;
    PORT
      LAYER M5 ;
        RECT  34.608 55.968 34.632 56.16 ;
    END
  END o[335]
  PIN o[336]
    DIRECTION OUTPUT ;
    USE SIGNAL ;
    PORT
      LAYER M3 ;
        RECT  34.704 56.016 34.722 56.16 ;
    END
  END o[336]
  PIN o[337]
    DIRECTION OUTPUT ;
    USE SIGNAL ;
    PORT
      LAYER M5 ;
        RECT  34.8 55.968 34.824 56.16 ;
    END
  END o[337]
  PIN o[338]
    DIRECTION OUTPUT ;
    USE SIGNAL ;
    PORT
      LAYER M3 ;
        RECT  34.884 56.016 34.902 56.16 ;
    END
  END o[338]
  PIN o[339]
    DIRECTION OUTPUT ;
    USE SIGNAL ;
    PORT
      LAYER M5 ;
        RECT  34.992 55.968 35.016 56.16 ;
    END
  END o[339]
  PIN o[33]
    DIRECTION OUTPUT ;
    USE SIGNAL ;
    PORT
      LAYER M5 ;
        RECT  5.376 55.968 5.4 56.16 ;
    END
  END o[33]
  PIN o[340]
    DIRECTION OUTPUT ;
    USE SIGNAL ;
    PORT
      LAYER M3 ;
        RECT  35.1 56.016 35.118 56.16 ;
    END
  END o[340]
  PIN o[341]
    DIRECTION OUTPUT ;
    USE SIGNAL ;
    PORT
      LAYER M5 ;
        RECT  35.184 55.968 35.208 56.16 ;
    END
  END o[341]
  PIN o[342]
    DIRECTION OUTPUT ;
    USE SIGNAL ;
    PORT
      LAYER M3 ;
        RECT  35.28 56.016 35.298 56.16 ;
    END
  END o[342]
  PIN o[343]
    DIRECTION OUTPUT ;
    USE SIGNAL ;
    PORT
      LAYER M5 ;
        RECT  35.376 55.968 35.4 56.16 ;
    END
  END o[343]
  PIN o[344]
    DIRECTION OUTPUT ;
    USE SIGNAL ;
    PORT
      LAYER M3 ;
        RECT  35.46 56.016 35.478 56.16 ;
    END
  END o[344]
  PIN o[345]
    DIRECTION OUTPUT ;
    USE SIGNAL ;
    PORT
      LAYER M5 ;
        RECT  35.568 55.968 35.592 56.16 ;
    END
  END o[345]
  PIN o[346]
    DIRECTION OUTPUT ;
    USE SIGNAL ;
    PORT
      LAYER M3 ;
        RECT  35.676 56.016 35.694 56.16 ;
    END
  END o[346]
  PIN o[347]
    DIRECTION OUTPUT ;
    USE SIGNAL ;
    PORT
      LAYER M5 ;
        RECT  35.76 55.968 35.784 56.16 ;
    END
  END o[347]
  PIN o[348]
    DIRECTION OUTPUT ;
    USE SIGNAL ;
    PORT
      LAYER M3 ;
        RECT  35.856 56.016 35.874 56.16 ;
    END
  END o[348]
  PIN o[349]
    DIRECTION OUTPUT ;
    USE SIGNAL ;
    PORT
      LAYER M5 ;
        RECT  35.952 55.968 35.976 56.16 ;
    END
  END o[349]
  PIN o[34]
    DIRECTION OUTPUT ;
    USE SIGNAL ;
    PORT
      LAYER M3 ;
        RECT  5.472 56.016 5.49 56.16 ;
    END
  END o[34]
  PIN o[350]
    DIRECTION OUTPUT ;
    USE SIGNAL ;
    PORT
      LAYER M3 ;
        RECT  36.036 56.016 36.054 56.16 ;
    END
  END o[350]
  PIN o[351]
    DIRECTION OUTPUT ;
    USE SIGNAL ;
    PORT
      LAYER M5 ;
        RECT  36.144 55.968 36.168 56.16 ;
    END
  END o[351]
  PIN o[352]
    DIRECTION OUTPUT ;
    USE SIGNAL ;
    PORT
      LAYER M3 ;
        RECT  36.252 56.016 36.27 56.16 ;
    END
  END o[352]
  PIN o[353]
    DIRECTION OUTPUT ;
    USE SIGNAL ;
    PORT
      LAYER M5 ;
        RECT  36.336 55.968 36.36 56.16 ;
    END
  END o[353]
  PIN o[354]
    DIRECTION OUTPUT ;
    USE SIGNAL ;
    PORT
      LAYER M3 ;
        RECT  36.432 56.016 36.45 56.16 ;
    END
  END o[354]
  PIN o[355]
    DIRECTION OUTPUT ;
    USE SIGNAL ;
    PORT
      LAYER M5 ;
        RECT  36.528 55.968 36.552 56.16 ;
    END
  END o[355]
  PIN o[356]
    DIRECTION OUTPUT ;
    USE SIGNAL ;
    PORT
      LAYER M3 ;
        RECT  36.648 56.016 36.666 56.16 ;
    END
  END o[356]
  PIN o[357]
    DIRECTION OUTPUT ;
    USE SIGNAL ;
    PORT
      LAYER M5 ;
        RECT  36.72 55.968 36.744 56.16 ;
    END
  END o[357]
  PIN o[358]
    DIRECTION OUTPUT ;
    USE SIGNAL ;
    PORT
      LAYER M3 ;
        RECT  36.828 56.016 36.846 56.16 ;
    END
  END o[358]
  PIN o[359]
    DIRECTION OUTPUT ;
    USE SIGNAL ;
    PORT
      LAYER M5 ;
        RECT  36.912 55.968 36.936 56.16 ;
    END
  END o[359]
  PIN o[35]
    DIRECTION OUTPUT ;
    USE SIGNAL ;
    PORT
      LAYER M5 ;
        RECT  5.568 55.968 5.592 56.16 ;
    END
  END o[35]
  PIN o[360]
    DIRECTION OUTPUT ;
    USE SIGNAL ;
    PORT
      LAYER M3 ;
        RECT  37.008 56.016 37.026 56.16 ;
    END
  END o[360]
  PIN o[361]
    DIRECTION OUTPUT ;
    USE SIGNAL ;
    PORT
      LAYER M5 ;
        RECT  37.104 55.968 37.128 56.16 ;
    END
  END o[361]
  PIN o[362]
    DIRECTION OUTPUT ;
    USE SIGNAL ;
    PORT
      LAYER M3 ;
        RECT  37.224 56.016 37.242 56.16 ;
    END
  END o[362]
  PIN o[363]
    DIRECTION OUTPUT ;
    USE SIGNAL ;
    PORT
      LAYER M5 ;
        RECT  37.296 55.968 37.32 56.16 ;
    END
  END o[363]
  PIN o[364]
    DIRECTION OUTPUT ;
    USE SIGNAL ;
    PORT
      LAYER M3 ;
        RECT  37.404 56.016 37.422 56.16 ;
    END
  END o[364]
  PIN o[365]
    DIRECTION OUTPUT ;
    USE SIGNAL ;
    PORT
      LAYER M5 ;
        RECT  37.488 55.968 37.512 56.16 ;
    END
  END o[365]
  PIN o[366]
    DIRECTION OUTPUT ;
    USE SIGNAL ;
    PORT
      LAYER M3 ;
        RECT  37.584 56.016 37.602 56.16 ;
    END
  END o[366]
  PIN o[367]
    DIRECTION OUTPUT ;
    USE SIGNAL ;
    PORT
      LAYER M5 ;
        RECT  37.68 55.968 37.704 56.16 ;
    END
  END o[367]
  PIN o[368]
    DIRECTION OUTPUT ;
    USE SIGNAL ;
    PORT
      LAYER M3 ;
        RECT  37.8 56.016 37.818 56.16 ;
    END
  END o[368]
  PIN o[369]
    DIRECTION OUTPUT ;
    USE SIGNAL ;
    PORT
      LAYER M5 ;
        RECT  37.872 55.968 37.896 56.16 ;
    END
  END o[369]
  PIN o[36]
    DIRECTION OUTPUT ;
    USE SIGNAL ;
    PORT
      LAYER M3 ;
        RECT  5.688 56.016 5.706 56.16 ;
    END
  END o[36]
  PIN o[370]
    DIRECTION OUTPUT ;
    USE SIGNAL ;
    PORT
      LAYER M3 ;
        RECT  37.98 56.016 37.998 56.16 ;
    END
  END o[370]
  PIN o[371]
    DIRECTION OUTPUT ;
    USE SIGNAL ;
    PORT
      LAYER M5 ;
        RECT  38.064 55.968 38.088 56.16 ;
    END
  END o[371]
  PIN o[372]
    DIRECTION OUTPUT ;
    USE SIGNAL ;
    PORT
      LAYER M3 ;
        RECT  38.16 56.016 38.178 56.16 ;
    END
  END o[372]
  PIN o[373]
    DIRECTION OUTPUT ;
    USE SIGNAL ;
    PORT
      LAYER M5 ;
        RECT  38.256 55.968 38.28 56.16 ;
    END
  END o[373]
  PIN o[374]
    DIRECTION OUTPUT ;
    USE SIGNAL ;
    PORT
      LAYER M3 ;
        RECT  38.376 56.016 38.394 56.16 ;
    END
  END o[374]
  PIN o[375]
    DIRECTION OUTPUT ;
    USE SIGNAL ;
    PORT
      LAYER M5 ;
        RECT  38.448 55.968 38.472 56.16 ;
    END
  END o[375]
  PIN o[376]
    DIRECTION OUTPUT ;
    USE SIGNAL ;
    PORT
      LAYER M3 ;
        RECT  38.556 56.016 38.574 56.16 ;
    END
  END o[376]
  PIN o[377]
    DIRECTION OUTPUT ;
    USE SIGNAL ;
    PORT
      LAYER M5 ;
        RECT  38.64 55.968 38.664 56.16 ;
    END
  END o[377]
  PIN o[378]
    DIRECTION OUTPUT ;
    USE SIGNAL ;
    PORT
      LAYER M3 ;
        RECT  38.772 56.016 38.79 56.16 ;
    END
  END o[378]
  PIN o[379]
    DIRECTION OUTPUT ;
    USE SIGNAL ;
    PORT
      LAYER M5 ;
        RECT  38.832 55.968 38.856 56.16 ;
    END
  END o[379]
  PIN o[37]
    DIRECTION OUTPUT ;
    USE SIGNAL ;
    PORT
      LAYER M5 ;
        RECT  5.76 55.968 5.784 56.16 ;
    END
  END o[37]
  PIN o[380]
    DIRECTION OUTPUT ;
    USE SIGNAL ;
    PORT
      LAYER M3 ;
        RECT  38.952 56.016 38.97 56.16 ;
    END
  END o[380]
  PIN o[381]
    DIRECTION OUTPUT ;
    USE SIGNAL ;
    PORT
      LAYER M5 ;
        RECT  39.024 55.968 39.048 56.16 ;
    END
  END o[381]
  PIN o[382]
    DIRECTION OUTPUT ;
    USE SIGNAL ;
    PORT
      LAYER M3 ;
        RECT  39.132 56.016 39.15 56.16 ;
    END
  END o[382]
  PIN o[383]
    DIRECTION OUTPUT ;
    USE SIGNAL ;
    PORT
      LAYER M5 ;
        RECT  39.216 55.968 39.24 56.16 ;
    END
  END o[383]
  PIN o[384]
    DIRECTION OUTPUT ;
    USE SIGNAL ;
    PORT
      LAYER M3 ;
        RECT  39.348 56.016 39.366 56.16 ;
    END
  END o[384]
  PIN o[385]
    DIRECTION OUTPUT ;
    USE SIGNAL ;
    PORT
      LAYER M5 ;
        RECT  39.456 55.968 39.48 56.16 ;
    END
  END o[385]
  PIN o[386]
    DIRECTION OUTPUT ;
    USE SIGNAL ;
    PORT
      LAYER M3 ;
        RECT  39.528 56.016 39.546 56.16 ;
    END
  END o[386]
  PIN o[387]
    DIRECTION OUTPUT ;
    USE SIGNAL ;
    PORT
      LAYER M5 ;
        RECT  39.648 55.968 39.672 56.16 ;
    END
  END o[387]
  PIN o[388]
    DIRECTION OUTPUT ;
    USE SIGNAL ;
    PORT
      LAYER M3 ;
        RECT  39.708 56.016 39.726 56.16 ;
    END
  END o[388]
  PIN o[389]
    DIRECTION OUTPUT ;
    USE SIGNAL ;
    PORT
      LAYER M5 ;
        RECT  39.84 55.968 39.864 56.16 ;
    END
  END o[389]
  PIN o[38]
    DIRECTION OUTPUT ;
    USE SIGNAL ;
    PORT
      LAYER M3 ;
        RECT  5.868 56.016 5.886 56.16 ;
    END
  END o[38]
  PIN o[390]
    DIRECTION OUTPUT ;
    USE SIGNAL ;
    PORT
      LAYER M3 ;
        RECT  39.924 56.016 39.942 56.16 ;
    END
  END o[390]
  PIN o[391]
    DIRECTION OUTPUT ;
    USE SIGNAL ;
    PORT
      LAYER M5 ;
        RECT  40.032 55.968 40.056 56.16 ;
    END
  END o[391]
  PIN o[392]
    DIRECTION OUTPUT ;
    USE SIGNAL ;
    PORT
      LAYER M3 ;
        RECT  40.104 56.016 40.122 56.16 ;
    END
  END o[392]
  PIN o[393]
    DIRECTION OUTPUT ;
    USE SIGNAL ;
    PORT
      LAYER M5 ;
        RECT  40.224 55.968 40.248 56.16 ;
    END
  END o[393]
  PIN o[394]
    DIRECTION OUTPUT ;
    USE SIGNAL ;
    PORT
      LAYER M3 ;
        RECT  40.32 56.016 40.338 56.16 ;
    END
  END o[394]
  PIN o[395]
    DIRECTION OUTPUT ;
    USE SIGNAL ;
    PORT
      LAYER M5 ;
        RECT  40.416 55.968 40.44 56.16 ;
    END
  END o[395]
  PIN o[396]
    DIRECTION OUTPUT ;
    USE SIGNAL ;
    PORT
      LAYER M3 ;
        RECT  40.5 56.016 40.518 56.16 ;
    END
  END o[396]
  PIN o[397]
    DIRECTION OUTPUT ;
    USE SIGNAL ;
    PORT
      LAYER M5 ;
        RECT  40.608 55.968 40.632 56.16 ;
    END
  END o[397]
  PIN o[398]
    DIRECTION OUTPUT ;
    USE SIGNAL ;
    PORT
      LAYER M3 ;
        RECT  40.68 56.016 40.698 56.16 ;
    END
  END o[398]
  PIN o[399]
    DIRECTION OUTPUT ;
    USE SIGNAL ;
    PORT
      LAYER M5 ;
        RECT  40.8 55.968 40.824 56.16 ;
    END
  END o[399]
  PIN o[39]
    DIRECTION OUTPUT ;
    USE SIGNAL ;
    PORT
      LAYER M5 ;
        RECT  5.952 55.968 5.976 56.16 ;
    END
  END o[39]
  PIN o[3]
    DIRECTION OUTPUT ;
    USE SIGNAL ;
    PORT
      LAYER M5 ;
        RECT  2.496 55.968 2.52 56.16 ;
    END
  END o[3]
  PIN o[400]
    DIRECTION OUTPUT ;
    USE SIGNAL ;
    PORT
      LAYER M3 ;
        RECT  40.896 56.016 40.914 56.16 ;
    END
  END o[400]
  PIN o[401]
    DIRECTION OUTPUT ;
    USE SIGNAL ;
    PORT
      LAYER M5 ;
        RECT  40.992 55.968 41.016 56.16 ;
    END
  END o[401]
  PIN o[402]
    DIRECTION OUTPUT ;
    USE SIGNAL ;
    PORT
      LAYER M3 ;
        RECT  41.076 56.016 41.094 56.16 ;
    END
  END o[402]
  PIN o[403]
    DIRECTION OUTPUT ;
    USE SIGNAL ;
    PORT
      LAYER M5 ;
        RECT  41.184 55.968 41.208 56.16 ;
    END
  END o[403]
  PIN o[404]
    DIRECTION OUTPUT ;
    USE SIGNAL ;
    PORT
      LAYER M3 ;
        RECT  41.256 56.016 41.274 56.16 ;
    END
  END o[404]
  PIN o[405]
    DIRECTION OUTPUT ;
    USE SIGNAL ;
    PORT
      LAYER M5 ;
        RECT  41.376 55.968 41.4 56.16 ;
    END
  END o[405]
  PIN o[406]
    DIRECTION OUTPUT ;
    USE SIGNAL ;
    PORT
      LAYER M3 ;
        RECT  41.472 56.016 41.49 56.16 ;
    END
  END o[406]
  PIN o[407]
    DIRECTION OUTPUT ;
    USE SIGNAL ;
    PORT
      LAYER M5 ;
        RECT  41.568 55.968 41.592 56.16 ;
    END
  END o[407]
  PIN o[408]
    DIRECTION OUTPUT ;
    USE SIGNAL ;
    PORT
      LAYER M3 ;
        RECT  41.652 56.016 41.67 56.16 ;
    END
  END o[408]
  PIN o[409]
    DIRECTION OUTPUT ;
    USE SIGNAL ;
    PORT
      LAYER M5 ;
        RECT  41.76 55.968 41.784 56.16 ;
    END
  END o[409]
  PIN o[40]
    DIRECTION OUTPUT ;
    USE SIGNAL ;
    PORT
      LAYER M3 ;
        RECT  6.084 56.016 6.102 56.16 ;
    END
  END o[40]
  PIN o[410]
    DIRECTION OUTPUT ;
    USE SIGNAL ;
    PORT
      LAYER M3 ;
        RECT  41.868 56.016 41.886 56.16 ;
    END
  END o[410]
  PIN o[411]
    DIRECTION OUTPUT ;
    USE SIGNAL ;
    PORT
      LAYER M5 ;
        RECT  41.952 55.968 41.976 56.16 ;
    END
  END o[411]
  PIN o[412]
    DIRECTION OUTPUT ;
    USE SIGNAL ;
    PORT
      LAYER M3 ;
        RECT  42.048 56.016 42.066 56.16 ;
    END
  END o[412]
  PIN o[413]
    DIRECTION OUTPUT ;
    USE SIGNAL ;
    PORT
      LAYER M5 ;
        RECT  42.144 55.968 42.168 56.16 ;
    END
  END o[413]
  PIN o[414]
    DIRECTION OUTPUT ;
    USE SIGNAL ;
    PORT
      LAYER M3 ;
        RECT  42.228 56.016 42.246 56.16 ;
    END
  END o[414]
  PIN o[415]
    DIRECTION OUTPUT ;
    USE SIGNAL ;
    PORT
      LAYER M5 ;
        RECT  42.336 55.968 42.36 56.16 ;
    END
  END o[415]
  PIN o[416]
    DIRECTION OUTPUT ;
    USE SIGNAL ;
    PORT
      LAYER M3 ;
        RECT  42.444 56.016 42.462 56.16 ;
    END
  END o[416]
  PIN o[417]
    DIRECTION OUTPUT ;
    USE SIGNAL ;
    PORT
      LAYER M5 ;
        RECT  42.528 55.968 42.552 56.16 ;
    END
  END o[417]
  PIN o[418]
    DIRECTION OUTPUT ;
    USE SIGNAL ;
    PORT
      LAYER M3 ;
        RECT  42.624 56.016 42.642 56.16 ;
    END
  END o[418]
  PIN o[419]
    DIRECTION OUTPUT ;
    USE SIGNAL ;
    PORT
      LAYER M5 ;
        RECT  42.72 55.968 42.744 56.16 ;
    END
  END o[419]
  PIN o[41]
    DIRECTION OUTPUT ;
    USE SIGNAL ;
    PORT
      LAYER M5 ;
        RECT  6.144 55.968 6.168 56.16 ;
    END
  END o[41]
  PIN o[420]
    DIRECTION OUTPUT ;
    USE SIGNAL ;
    PORT
      LAYER M3 ;
        RECT  42.804 56.016 42.822 56.16 ;
    END
  END o[420]
  PIN o[421]
    DIRECTION OUTPUT ;
    USE SIGNAL ;
    PORT
      LAYER M5 ;
        RECT  42.912 55.968 42.936 56.16 ;
    END
  END o[421]
  PIN o[422]
    DIRECTION OUTPUT ;
    USE SIGNAL ;
    PORT
      LAYER M3 ;
        RECT  43.02 56.016 43.038 56.16 ;
    END
  END o[422]
  PIN o[423]
    DIRECTION OUTPUT ;
    USE SIGNAL ;
    PORT
      LAYER M5 ;
        RECT  43.104 55.968 43.128 56.16 ;
    END
  END o[423]
  PIN o[424]
    DIRECTION OUTPUT ;
    USE SIGNAL ;
    PORT
      LAYER M3 ;
        RECT  43.2 56.016 43.218 56.16 ;
    END
  END o[424]
  PIN o[425]
    DIRECTION OUTPUT ;
    USE SIGNAL ;
    PORT
      LAYER M5 ;
        RECT  43.296 55.968 43.32 56.16 ;
    END
  END o[425]
  PIN o[426]
    DIRECTION OUTPUT ;
    USE SIGNAL ;
    PORT
      LAYER M3 ;
        RECT  43.416 56.016 43.434 56.16 ;
    END
  END o[426]
  PIN o[427]
    DIRECTION OUTPUT ;
    USE SIGNAL ;
    PORT
      LAYER M5 ;
        RECT  43.488 55.968 43.512 56.16 ;
    END
  END o[427]
  PIN o[428]
    DIRECTION OUTPUT ;
    USE SIGNAL ;
    PORT
      LAYER M3 ;
        RECT  43.596 56.016 43.614 56.16 ;
    END
  END o[428]
  PIN o[429]
    DIRECTION OUTPUT ;
    USE SIGNAL ;
    PORT
      LAYER M5 ;
        RECT  43.68 55.968 43.704 56.16 ;
    END
  END o[429]
  PIN o[42]
    DIRECTION OUTPUT ;
    USE SIGNAL ;
    PORT
      LAYER M3 ;
        RECT  6.264 56.016 6.282 56.16 ;
    END
  END o[42]
  PIN o[430]
    DIRECTION OUTPUT ;
    USE SIGNAL ;
    PORT
      LAYER M3 ;
        RECT  43.776 56.016 43.794 56.16 ;
    END
  END o[430]
  PIN o[431]
    DIRECTION OUTPUT ;
    USE SIGNAL ;
    PORT
      LAYER M5 ;
        RECT  43.872 55.968 43.896 56.16 ;
    END
  END o[431]
  PIN o[432]
    DIRECTION OUTPUT ;
    USE SIGNAL ;
    PORT
      LAYER M3 ;
        RECT  43.992 56.016 44.01 56.16 ;
    END
  END o[432]
  PIN o[433]
    DIRECTION OUTPUT ;
    USE SIGNAL ;
    PORT
      LAYER M5 ;
        RECT  44.064 55.968 44.088 56.16 ;
    END
  END o[433]
  PIN o[434]
    DIRECTION OUTPUT ;
    USE SIGNAL ;
    PORT
      LAYER M3 ;
        RECT  44.172 56.016 44.19 56.16 ;
    END
  END o[434]
  PIN o[435]
    DIRECTION OUTPUT ;
    USE SIGNAL ;
    PORT
      LAYER M5 ;
        RECT  44.256 55.968 44.28 56.16 ;
    END
  END o[435]
  PIN o[436]
    DIRECTION OUTPUT ;
    USE SIGNAL ;
    PORT
      LAYER M3 ;
        RECT  44.352 56.016 44.37 56.16 ;
    END
  END o[436]
  PIN o[437]
    DIRECTION OUTPUT ;
    USE SIGNAL ;
    PORT
      LAYER M5 ;
        RECT  44.448 55.968 44.472 56.16 ;
    END
  END o[437]
  PIN o[438]
    DIRECTION OUTPUT ;
    USE SIGNAL ;
    PORT
      LAYER M3 ;
        RECT  44.568 56.016 44.586 56.16 ;
    END
  END o[438]
  PIN o[439]
    DIRECTION OUTPUT ;
    USE SIGNAL ;
    PORT
      LAYER M5 ;
        RECT  44.64 55.968 44.664 56.16 ;
    END
  END o[439]
  PIN o[43]
    DIRECTION OUTPUT ;
    USE SIGNAL ;
    PORT
      LAYER M5 ;
        RECT  6.336 55.968 6.36 56.16 ;
    END
  END o[43]
  PIN o[440]
    DIRECTION OUTPUT ;
    USE SIGNAL ;
    PORT
      LAYER M3 ;
        RECT  44.748 56.016 44.766 56.16 ;
    END
  END o[440]
  PIN o[441]
    DIRECTION OUTPUT ;
    USE SIGNAL ;
    PORT
      LAYER M5 ;
        RECT  44.832 55.968 44.856 56.16 ;
    END
  END o[441]
  PIN o[442]
    DIRECTION OUTPUT ;
    USE SIGNAL ;
    PORT
      LAYER M3 ;
        RECT  44.964 56.016 44.982 56.16 ;
    END
  END o[442]
  PIN o[443]
    DIRECTION OUTPUT ;
    USE SIGNAL ;
    PORT
      LAYER M5 ;
        RECT  45.024 55.968 45.048 56.16 ;
    END
  END o[443]
  PIN o[444]
    DIRECTION OUTPUT ;
    USE SIGNAL ;
    PORT
      LAYER M3 ;
        RECT  45.144 56.016 45.162 56.16 ;
    END
  END o[444]
  PIN o[445]
    DIRECTION OUTPUT ;
    USE SIGNAL ;
    PORT
      LAYER M5 ;
        RECT  45.216 55.968 45.24 56.16 ;
    END
  END o[445]
  PIN o[446]
    DIRECTION OUTPUT ;
    USE SIGNAL ;
    PORT
      LAYER M3 ;
        RECT  45.324 56.016 45.342 56.16 ;
    END
  END o[446]
  PIN o[447]
    DIRECTION OUTPUT ;
    USE SIGNAL ;
    PORT
      LAYER M5 ;
        RECT  45.408 55.968 45.432 56.16 ;
    END
  END o[447]
  PIN o[448]
    DIRECTION OUTPUT ;
    USE SIGNAL ;
    PORT
      LAYER M3 ;
        RECT  45.54 56.016 45.558 56.16 ;
    END
  END o[448]
  PIN o[449]
    DIRECTION OUTPUT ;
    USE SIGNAL ;
    PORT
      LAYER M5 ;
        RECT  45.6 55.968 45.624 56.16 ;
    END
  END o[449]
  PIN o[44]
    DIRECTION OUTPUT ;
    USE SIGNAL ;
    PORT
      LAYER M3 ;
        RECT  6.444 56.016 6.462 56.16 ;
    END
  END o[44]
  PIN o[450]
    DIRECTION OUTPUT ;
    USE SIGNAL ;
    PORT
      LAYER M3 ;
        RECT  45.72 56.016 45.738 56.16 ;
    END
  END o[450]
  PIN o[451]
    DIRECTION OUTPUT ;
    USE SIGNAL ;
    PORT
      LAYER M5 ;
        RECT  45.792 55.968 45.816 56.16 ;
    END
  END o[451]
  PIN o[452]
    DIRECTION OUTPUT ;
    USE SIGNAL ;
    PORT
      LAYER M3 ;
        RECT  45.9 56.016 45.918 56.16 ;
    END
  END o[452]
  PIN o[453]
    DIRECTION OUTPUT ;
    USE SIGNAL ;
    PORT
      LAYER M5 ;
        RECT  46.032 55.968 46.056 56.16 ;
    END
  END o[453]
  PIN o[454]
    DIRECTION OUTPUT ;
    USE SIGNAL ;
    PORT
      LAYER M3 ;
        RECT  46.116 56.016 46.134 56.16 ;
    END
  END o[454]
  PIN o[455]
    DIRECTION OUTPUT ;
    USE SIGNAL ;
    PORT
      LAYER M5 ;
        RECT  46.224 55.968 46.248 56.16 ;
    END
  END o[455]
  PIN o[456]
    DIRECTION OUTPUT ;
    USE SIGNAL ;
    PORT
      LAYER M3 ;
        RECT  46.296 56.016 46.314 56.16 ;
    END
  END o[456]
  PIN o[457]
    DIRECTION OUTPUT ;
    USE SIGNAL ;
    PORT
      LAYER M5 ;
        RECT  46.416 55.968 46.44 56.16 ;
    END
  END o[457]
  PIN o[458]
    DIRECTION OUTPUT ;
    USE SIGNAL ;
    PORT
      LAYER M3 ;
        RECT  46.512 56.016 46.53 56.16 ;
    END
  END o[458]
  PIN o[459]
    DIRECTION OUTPUT ;
    USE SIGNAL ;
    PORT
      LAYER M5 ;
        RECT  46.608 55.968 46.632 56.16 ;
    END
  END o[459]
  PIN o[45]
    DIRECTION OUTPUT ;
    USE SIGNAL ;
    PORT
      LAYER M5 ;
        RECT  6.528 55.968 6.552 56.16 ;
    END
  END o[45]
  PIN o[460]
    DIRECTION OUTPUT ;
    USE SIGNAL ;
    PORT
      LAYER M3 ;
        RECT  46.692 56.016 46.71 56.16 ;
    END
  END o[460]
  PIN o[461]
    DIRECTION OUTPUT ;
    USE SIGNAL ;
    PORT
      LAYER M5 ;
        RECT  46.8 55.968 46.824 56.16 ;
    END
  END o[461]
  PIN o[462]
    DIRECTION OUTPUT ;
    USE SIGNAL ;
    PORT
      LAYER M3 ;
        RECT  46.872 56.016 46.89 56.16 ;
    END
  END o[462]
  PIN o[463]
    DIRECTION OUTPUT ;
    USE SIGNAL ;
    PORT
      LAYER M5 ;
        RECT  46.992 55.968 47.016 56.16 ;
    END
  END o[463]
  PIN o[464]
    DIRECTION OUTPUT ;
    USE SIGNAL ;
    PORT
      LAYER M3 ;
        RECT  47.088 56.016 47.106 56.16 ;
    END
  END o[464]
  PIN o[465]
    DIRECTION OUTPUT ;
    USE SIGNAL ;
    PORT
      LAYER M5 ;
        RECT  47.184 55.968 47.208 56.16 ;
    END
  END o[465]
  PIN o[466]
    DIRECTION OUTPUT ;
    USE SIGNAL ;
    PORT
      LAYER M3 ;
        RECT  47.268 56.016 47.286 56.16 ;
    END
  END o[466]
  PIN o[467]
    DIRECTION OUTPUT ;
    USE SIGNAL ;
    PORT
      LAYER M5 ;
        RECT  47.376 55.968 47.4 56.16 ;
    END
  END o[467]
  PIN o[468]
    DIRECTION OUTPUT ;
    USE SIGNAL ;
    PORT
      LAYER M3 ;
        RECT  47.448 56.016 47.466 56.16 ;
    END
  END o[468]
  PIN o[469]
    DIRECTION OUTPUT ;
    USE SIGNAL ;
    PORT
      LAYER M5 ;
        RECT  47.568 55.968 47.592 56.16 ;
    END
  END o[469]
  PIN o[46]
    DIRECTION OUTPUT ;
    USE SIGNAL ;
    PORT
      LAYER M3 ;
        RECT  6.66 56.016 6.678 56.16 ;
    END
  END o[46]
  PIN o[470]
    DIRECTION OUTPUT ;
    USE SIGNAL ;
    PORT
      LAYER M3 ;
        RECT  47.664 56.016 47.682 56.16 ;
    END
  END o[470]
  PIN o[471]
    DIRECTION OUTPUT ;
    USE SIGNAL ;
    PORT
      LAYER M5 ;
        RECT  47.76 55.968 47.784 56.16 ;
    END
  END o[471]
  PIN o[472]
    DIRECTION OUTPUT ;
    USE SIGNAL ;
    PORT
      LAYER M3 ;
        RECT  47.844 56.016 47.862 56.16 ;
    END
  END o[472]
  PIN o[473]
    DIRECTION OUTPUT ;
    USE SIGNAL ;
    PORT
      LAYER M5 ;
        RECT  47.952 55.968 47.976 56.16 ;
    END
  END o[473]
  PIN o[474]
    DIRECTION OUTPUT ;
    USE SIGNAL ;
    PORT
      LAYER M3 ;
        RECT  48.06 56.016 48.078 56.16 ;
    END
  END o[474]
  PIN o[475]
    DIRECTION OUTPUT ;
    USE SIGNAL ;
    PORT
      LAYER M5 ;
        RECT  48.144 55.968 48.168 56.16 ;
    END
  END o[475]
  PIN o[476]
    DIRECTION OUTPUT ;
    USE SIGNAL ;
    PORT
      LAYER M3 ;
        RECT  48.24 56.016 48.258 56.16 ;
    END
  END o[476]
  PIN o[477]
    DIRECTION OUTPUT ;
    USE SIGNAL ;
    PORT
      LAYER M5 ;
        RECT  48.336 55.968 48.36 56.16 ;
    END
  END o[477]
  PIN o[478]
    DIRECTION OUTPUT ;
    USE SIGNAL ;
    PORT
      LAYER M3 ;
        RECT  48.42 56.016 48.438 56.16 ;
    END
  END o[478]
  PIN o[479]
    DIRECTION OUTPUT ;
    USE SIGNAL ;
    PORT
      LAYER M5 ;
        RECT  48.528 55.968 48.552 56.16 ;
    END
  END o[479]
  PIN o[47]
    DIRECTION OUTPUT ;
    USE SIGNAL ;
    PORT
      LAYER M5 ;
        RECT  6.72 55.968 6.744 56.16 ;
    END
  END o[47]
  PIN o[480]
    DIRECTION OUTPUT ;
    USE SIGNAL ;
    PORT
      LAYER M3 ;
        RECT  48.636 56.016 48.654 56.16 ;
    END
  END o[480]
  PIN o[481]
    DIRECTION OUTPUT ;
    USE SIGNAL ;
    PORT
      LAYER M5 ;
        RECT  48.72 55.968 48.744 56.16 ;
    END
  END o[481]
  PIN o[482]
    DIRECTION OUTPUT ;
    USE SIGNAL ;
    PORT
      LAYER M3 ;
        RECT  48.816 56.016 48.834 56.16 ;
    END
  END o[482]
  PIN o[483]
    DIRECTION OUTPUT ;
    USE SIGNAL ;
    PORT
      LAYER M5 ;
        RECT  48.912 55.968 48.936 56.16 ;
    END
  END o[483]
  PIN o[484]
    DIRECTION OUTPUT ;
    USE SIGNAL ;
    PORT
      LAYER M3 ;
        RECT  48.996 56.016 49.014 56.16 ;
    END
  END o[484]
  PIN o[485]
    DIRECTION OUTPUT ;
    USE SIGNAL ;
    PORT
      LAYER M5 ;
        RECT  49.104 55.968 49.128 56.16 ;
    END
  END o[485]
  PIN o[486]
    DIRECTION OUTPUT ;
    USE SIGNAL ;
    PORT
      LAYER M3 ;
        RECT  49.212 56.016 49.23 56.16 ;
    END
  END o[486]
  PIN o[487]
    DIRECTION OUTPUT ;
    USE SIGNAL ;
    PORT
      LAYER M5 ;
        RECT  49.296 55.968 49.32 56.16 ;
    END
  END o[487]
  PIN o[488]
    DIRECTION OUTPUT ;
    USE SIGNAL ;
    PORT
      LAYER M3 ;
        RECT  49.392 56.016 49.41 56.16 ;
    END
  END o[488]
  PIN o[489]
    DIRECTION OUTPUT ;
    USE SIGNAL ;
    PORT
      LAYER M5 ;
        RECT  49.488 55.968 49.512 56.16 ;
    END
  END o[489]
  PIN o[48]
    DIRECTION OUTPUT ;
    USE SIGNAL ;
    PORT
      LAYER M3 ;
        RECT  6.84 56.016 6.858 56.16 ;
    END
  END o[48]
  PIN o[490]
    DIRECTION OUTPUT ;
    USE SIGNAL ;
    PORT
      LAYER M3 ;
        RECT  49.608 56.016 49.626 56.16 ;
    END
  END o[490]
  PIN o[491]
    DIRECTION OUTPUT ;
    USE SIGNAL ;
    PORT
      LAYER M5 ;
        RECT  49.68 55.968 49.704 56.16 ;
    END
  END o[491]
  PIN o[492]
    DIRECTION OUTPUT ;
    USE SIGNAL ;
    PORT
      LAYER M3 ;
        RECT  49.788 56.016 49.806 56.16 ;
    END
  END o[492]
  PIN o[493]
    DIRECTION OUTPUT ;
    USE SIGNAL ;
    PORT
      LAYER M5 ;
        RECT  49.872 55.968 49.896 56.16 ;
    END
  END o[493]
  PIN o[494]
    DIRECTION OUTPUT ;
    USE SIGNAL ;
    PORT
      LAYER M3 ;
        RECT  49.968 56.016 49.986 56.16 ;
    END
  END o[494]
  PIN o[495]
    DIRECTION OUTPUT ;
    USE SIGNAL ;
    PORT
      LAYER M5 ;
        RECT  50.064 55.968 50.088 56.16 ;
    END
  END o[495]
  PIN o[496]
    DIRECTION OUTPUT ;
    USE SIGNAL ;
    PORT
      LAYER M3 ;
        RECT  50.184 56.016 50.202 56.16 ;
    END
  END o[496]
  PIN o[497]
    DIRECTION OUTPUT ;
    USE SIGNAL ;
    PORT
      LAYER M5 ;
        RECT  50.256 55.968 50.28 56.16 ;
    END
  END o[497]
  PIN o[498]
    DIRECTION OUTPUT ;
    USE SIGNAL ;
    PORT
      LAYER M3 ;
        RECT  50.364 56.016 50.382 56.16 ;
    END
  END o[498]
  PIN o[499]
    DIRECTION OUTPUT ;
    USE SIGNAL ;
    PORT
      LAYER M5 ;
        RECT  50.448 55.968 50.472 56.16 ;
    END
  END o[499]
  PIN o[49]
    DIRECTION OUTPUT ;
    USE SIGNAL ;
    PORT
      LAYER M5 ;
        RECT  6.912 55.968 6.936 56.16 ;
    END
  END o[49]
  PIN o[4]
    DIRECTION OUTPUT ;
    USE SIGNAL ;
    PORT
      LAYER M3 ;
        RECT  2.592 56.016 2.61 56.16 ;
    END
  END o[4]
  PIN o[500]
    DIRECTION OUTPUT ;
    USE SIGNAL ;
    PORT
      LAYER M3 ;
        RECT  50.544 56.016 50.562 56.16 ;
    END
  END o[500]
  PIN o[501]
    DIRECTION OUTPUT ;
    USE SIGNAL ;
    PORT
      LAYER M5 ;
        RECT  50.64 55.968 50.664 56.16 ;
    END
  END o[501]
  PIN o[502]
    DIRECTION OUTPUT ;
    USE SIGNAL ;
    PORT
      LAYER M3 ;
        RECT  50.76 56.016 50.778 56.16 ;
    END
  END o[502]
  PIN o[503]
    DIRECTION OUTPUT ;
    USE SIGNAL ;
    PORT
      LAYER M5 ;
        RECT  50.832 55.968 50.856 56.16 ;
    END
  END o[503]
  PIN o[504]
    DIRECTION OUTPUT ;
    USE SIGNAL ;
    PORT
      LAYER M3 ;
        RECT  50.94 56.016 50.958 56.16 ;
    END
  END o[504]
  PIN o[505]
    DIRECTION OUTPUT ;
    USE SIGNAL ;
    PORT
      LAYER M5 ;
        RECT  51.024 55.968 51.048 56.16 ;
    END
  END o[505]
  PIN o[506]
    DIRECTION OUTPUT ;
    USE SIGNAL ;
    PORT
      LAYER M3 ;
        RECT  51.12 56.016 51.138 56.16 ;
    END
  END o[506]
  PIN o[507]
    DIRECTION OUTPUT ;
    USE SIGNAL ;
    PORT
      LAYER M5 ;
        RECT  51.216 55.968 51.24 56.16 ;
    END
  END o[507]
  PIN o[508]
    DIRECTION OUTPUT ;
    USE SIGNAL ;
    PORT
      LAYER M3 ;
        RECT  51.336 56.016 51.354 56.16 ;
    END
  END o[508]
  PIN o[509]
    DIRECTION OUTPUT ;
    USE SIGNAL ;
    PORT
      LAYER M5 ;
        RECT  51.408 55.968 51.432 56.16 ;
    END
  END o[509]
  PIN o[50]
    DIRECTION OUTPUT ;
    USE SIGNAL ;
    PORT
      LAYER M3 ;
        RECT  7.02 56.016 7.038 56.16 ;
    END
  END o[50]
  PIN o[510]
    DIRECTION OUTPUT ;
    USE SIGNAL ;
    PORT
      LAYER M3 ;
        RECT  51.516 56.016 51.534 56.16 ;
    END
  END o[510]
  PIN o[511]
    DIRECTION OUTPUT ;
    USE SIGNAL ;
    PORT
      LAYER M5 ;
        RECT  51.6 55.968 51.624 56.16 ;
    END
  END o[511]
  PIN o[512]
    DIRECTION OUTPUT ;
    USE SIGNAL ;
    PORT
      LAYER M3 ;
        RECT  51.732 56.016 51.75 56.16 ;
    END
  END o[512]
  PIN o[513]
    DIRECTION OUTPUT ;
    USE SIGNAL ;
    PORT
      LAYER M5 ;
        RECT  51.792 55.968 51.816 56.16 ;
    END
  END o[513]
  PIN o[514]
    DIRECTION OUTPUT ;
    USE SIGNAL ;
    PORT
      LAYER M3 ;
        RECT  51.912 56.016 51.93 56.16 ;
    END
  END o[514]
  PIN o[515]
    DIRECTION OUTPUT ;
    USE SIGNAL ;
    PORT
      LAYER M5 ;
        RECT  51.984 55.968 52.008 56.16 ;
    END
  END o[515]
  PIN o[516]
    DIRECTION OUTPUT ;
    USE SIGNAL ;
    PORT
      LAYER M3 ;
        RECT  52.092 56.016 52.11 56.16 ;
    END
  END o[516]
  PIN o[517]
    DIRECTION OUTPUT ;
    USE SIGNAL ;
    PORT
      LAYER M5 ;
        RECT  52.176 55.968 52.2 56.16 ;
    END
  END o[517]
  PIN o[518]
    DIRECTION OUTPUT ;
    USE SIGNAL ;
    PORT
      LAYER M3 ;
        RECT  52.308 56.016 52.326 56.16 ;
    END
  END o[518]
  PIN o[519]
    DIRECTION OUTPUT ;
    USE SIGNAL ;
    PORT
      LAYER M5 ;
        RECT  52.416 55.968 52.44 56.16 ;
    END
  END o[519]
  PIN o[51]
    DIRECTION OUTPUT ;
    USE SIGNAL ;
    PORT
      LAYER M5 ;
        RECT  7.152 55.968 7.176 56.16 ;
    END
  END o[51]
  PIN o[520]
    DIRECTION OUTPUT ;
    USE SIGNAL ;
    PORT
      LAYER M3 ;
        RECT  52.488 56.016 52.506 56.16 ;
    END
  END o[520]
  PIN o[521]
    DIRECTION OUTPUT ;
    USE SIGNAL ;
    PORT
      LAYER M5 ;
        RECT  52.608 55.968 52.632 56.16 ;
    END
  END o[521]
  PIN o[522]
    DIRECTION OUTPUT ;
    USE SIGNAL ;
    PORT
      LAYER M3 ;
        RECT  52.668 56.016 52.686 56.16 ;
    END
  END o[522]
  PIN o[523]
    DIRECTION OUTPUT ;
    USE SIGNAL ;
    PORT
      LAYER M5 ;
        RECT  52.8 55.968 52.824 56.16 ;
    END
  END o[523]
  PIN o[524]
    DIRECTION OUTPUT ;
    USE SIGNAL ;
    PORT
      LAYER M3 ;
        RECT  52.884 56.016 52.902 56.16 ;
    END
  END o[524]
  PIN o[525]
    DIRECTION OUTPUT ;
    USE SIGNAL ;
    PORT
      LAYER M5 ;
        RECT  52.992 55.968 53.016 56.16 ;
    END
  END o[525]
  PIN o[526]
    DIRECTION OUTPUT ;
    USE SIGNAL ;
    PORT
      LAYER M3 ;
        RECT  53.064 56.016 53.082 56.16 ;
    END
  END o[526]
  PIN o[527]
    DIRECTION OUTPUT ;
    USE SIGNAL ;
    PORT
      LAYER M5 ;
        RECT  53.184 55.968 53.208 56.16 ;
    END
  END o[527]
  PIN o[528]
    DIRECTION OUTPUT ;
    USE SIGNAL ;
    PORT
      LAYER M3 ;
        RECT  53.28 56.016 53.298 56.16 ;
    END
  END o[528]
  PIN o[529]
    DIRECTION OUTPUT ;
    USE SIGNAL ;
    PORT
      LAYER M5 ;
        RECT  53.376 55.968 53.4 56.16 ;
    END
  END o[529]
  PIN o[52]
    DIRECTION OUTPUT ;
    USE SIGNAL ;
    PORT
      LAYER M3 ;
        RECT  7.236 56.016 7.254 56.16 ;
    END
  END o[52]
  PIN o[530]
    DIRECTION OUTPUT ;
    USE SIGNAL ;
    PORT
      LAYER M3 ;
        RECT  53.46 56.016 53.478 56.16 ;
    END
  END o[530]
  PIN o[531]
    DIRECTION OUTPUT ;
    USE SIGNAL ;
    PORT
      LAYER M5 ;
        RECT  53.568 55.968 53.592 56.16 ;
    END
  END o[531]
  PIN o[532]
    DIRECTION OUTPUT ;
    USE SIGNAL ;
    PORT
      LAYER M3 ;
        RECT  53.64 56.016 53.658 56.16 ;
    END
  END o[532]
  PIN o[533]
    DIRECTION OUTPUT ;
    USE SIGNAL ;
    PORT
      LAYER M5 ;
        RECT  53.76 55.968 53.784 56.16 ;
    END
  END o[533]
  PIN o[534]
    DIRECTION OUTPUT ;
    USE SIGNAL ;
    PORT
      LAYER M3 ;
        RECT  53.856 56.016 53.874 56.16 ;
    END
  END o[534]
  PIN o[535]
    DIRECTION OUTPUT ;
    USE SIGNAL ;
    PORT
      LAYER M5 ;
        RECT  53.952 55.968 53.976 56.16 ;
    END
  END o[535]
  PIN o[53]
    DIRECTION OUTPUT ;
    USE SIGNAL ;
    PORT
      LAYER M5 ;
        RECT  7.344 55.968 7.368 56.16 ;
    END
  END o[53]
  PIN o[54]
    DIRECTION OUTPUT ;
    USE SIGNAL ;
    PORT
      LAYER M3 ;
        RECT  7.416 56.016 7.434 56.16 ;
    END
  END o[54]
  PIN o[55]
    DIRECTION OUTPUT ;
    USE SIGNAL ;
    PORT
      LAYER M5 ;
        RECT  7.536 55.968 7.56 56.16 ;
    END
  END o[55]
  PIN o[56]
    DIRECTION OUTPUT ;
    USE SIGNAL ;
    PORT
      LAYER M3 ;
        RECT  7.632 56.016 7.65 56.16 ;
    END
  END o[56]
  PIN o[57]
    DIRECTION OUTPUT ;
    USE SIGNAL ;
    PORT
      LAYER M5 ;
        RECT  7.728 55.968 7.752 56.16 ;
    END
  END o[57]
  PIN o[58]
    DIRECTION OUTPUT ;
    USE SIGNAL ;
    PORT
      LAYER M3 ;
        RECT  7.812 56.016 7.83 56.16 ;
    END
  END o[58]
  PIN o[59]
    DIRECTION OUTPUT ;
    USE SIGNAL ;
    PORT
      LAYER M5 ;
        RECT  7.92 55.968 7.944 56.16 ;
    END
  END o[59]
  PIN o[5]
    DIRECTION OUTPUT ;
    USE SIGNAL ;
    PORT
      LAYER M5 ;
        RECT  2.688 55.968 2.712 56.16 ;
    END
  END o[5]
  PIN o[60]
    DIRECTION OUTPUT ;
    USE SIGNAL ;
    PORT
      LAYER M3 ;
        RECT  7.992 56.016 8.01 56.16 ;
    END
  END o[60]
  PIN o[61]
    DIRECTION OUTPUT ;
    USE SIGNAL ;
    PORT
      LAYER M5 ;
        RECT  8.112 55.968 8.136 56.16 ;
    END
  END o[61]
  PIN o[62]
    DIRECTION OUTPUT ;
    USE SIGNAL ;
    PORT
      LAYER M3 ;
        RECT  8.208 56.016 8.226 56.16 ;
    END
  END o[62]
  PIN o[63]
    DIRECTION OUTPUT ;
    USE SIGNAL ;
    PORT
      LAYER M5 ;
        RECT  8.304 55.968 8.328 56.16 ;
    END
  END o[63]
  PIN o[64]
    DIRECTION OUTPUT ;
    USE SIGNAL ;
    PORT
      LAYER M3 ;
        RECT  8.388 56.016 8.406 56.16 ;
    END
  END o[64]
  PIN o[65]
    DIRECTION OUTPUT ;
    USE SIGNAL ;
    PORT
      LAYER M5 ;
        RECT  8.496 55.968 8.52 56.16 ;
    END
  END o[65]
  PIN o[66]
    DIRECTION OUTPUT ;
    USE SIGNAL ;
    PORT
      LAYER M3 ;
        RECT  8.568 56.016 8.586 56.16 ;
    END
  END o[66]
  PIN o[67]
    DIRECTION OUTPUT ;
    USE SIGNAL ;
    PORT
      LAYER M5 ;
        RECT  8.688 55.968 8.712 56.16 ;
    END
  END o[67]
  PIN o[68]
    DIRECTION OUTPUT ;
    USE SIGNAL ;
    PORT
      LAYER M3 ;
        RECT  8.784 56.016 8.802 56.16 ;
    END
  END o[68]
  PIN o[69]
    DIRECTION OUTPUT ;
    USE SIGNAL ;
    PORT
      LAYER M5 ;
        RECT  8.88 55.968 8.904 56.16 ;
    END
  END o[69]
  PIN o[6]
    DIRECTION OUTPUT ;
    USE SIGNAL ;
    PORT
      LAYER M3 ;
        RECT  2.772 56.016 2.79 56.16 ;
    END
  END o[6]
  PIN o[70]
    DIRECTION OUTPUT ;
    USE SIGNAL ;
    PORT
      LAYER M3 ;
        RECT  8.964 56.016 8.982 56.16 ;
    END
  END o[70]
  PIN o[71]
    DIRECTION OUTPUT ;
    USE SIGNAL ;
    PORT
      LAYER M5 ;
        RECT  9.072 55.968 9.096 56.16 ;
    END
  END o[71]
  PIN o[72]
    DIRECTION OUTPUT ;
    USE SIGNAL ;
    PORT
      LAYER M3 ;
        RECT  9.18 56.016 9.198 56.16 ;
    END
  END o[72]
  PIN o[73]
    DIRECTION OUTPUT ;
    USE SIGNAL ;
    PORT
      LAYER M5 ;
        RECT  9.264 55.968 9.288 56.16 ;
    END
  END o[73]
  PIN o[74]
    DIRECTION OUTPUT ;
    USE SIGNAL ;
    PORT
      LAYER M3 ;
        RECT  9.36 56.016 9.378 56.16 ;
    END
  END o[74]
  PIN o[75]
    DIRECTION OUTPUT ;
    USE SIGNAL ;
    PORT
      LAYER M5 ;
        RECT  9.456 55.968 9.48 56.16 ;
    END
  END o[75]
  PIN o[76]
    DIRECTION OUTPUT ;
    USE SIGNAL ;
    PORT
      LAYER M3 ;
        RECT  9.54 56.016 9.558 56.16 ;
    END
  END o[76]
  PIN o[77]
    DIRECTION OUTPUT ;
    USE SIGNAL ;
    PORT
      LAYER M5 ;
        RECT  9.648 55.968 9.672 56.16 ;
    END
  END o[77]
  PIN o[78]
    DIRECTION OUTPUT ;
    USE SIGNAL ;
    PORT
      LAYER M3 ;
        RECT  9.756 56.016 9.774 56.16 ;
    END
  END o[78]
  PIN o[79]
    DIRECTION OUTPUT ;
    USE SIGNAL ;
    PORT
      LAYER M5 ;
        RECT  9.84 55.968 9.864 56.16 ;
    END
  END o[79]
  PIN o[7]
    DIRECTION OUTPUT ;
    USE SIGNAL ;
    PORT
      LAYER M5 ;
        RECT  2.88 55.968 2.904 56.16 ;
    END
  END o[7]
  PIN o[80]
    DIRECTION OUTPUT ;
    USE SIGNAL ;
    PORT
      LAYER M3 ;
        RECT  9.936 56.016 9.954 56.16 ;
    END
  END o[80]
  PIN o[81]
    DIRECTION OUTPUT ;
    USE SIGNAL ;
    PORT
      LAYER M5 ;
        RECT  10.032 55.968 10.056 56.16 ;
    END
  END o[81]
  PIN o[82]
    DIRECTION OUTPUT ;
    USE SIGNAL ;
    PORT
      LAYER M3 ;
        RECT  10.116 56.016 10.134 56.16 ;
    END
  END o[82]
  PIN o[83]
    DIRECTION OUTPUT ;
    USE SIGNAL ;
    PORT
      LAYER M5 ;
        RECT  10.224 55.968 10.248 56.16 ;
    END
  END o[83]
  PIN o[84]
    DIRECTION OUTPUT ;
    USE SIGNAL ;
    PORT
      LAYER M3 ;
        RECT  10.332 56.016 10.35 56.16 ;
    END
  END o[84]
  PIN o[85]
    DIRECTION OUTPUT ;
    USE SIGNAL ;
    PORT
      LAYER M5 ;
        RECT  10.416 55.968 10.44 56.16 ;
    END
  END o[85]
  PIN o[86]
    DIRECTION OUTPUT ;
    USE SIGNAL ;
    PORT
      LAYER M3 ;
        RECT  10.512 56.016 10.53 56.16 ;
    END
  END o[86]
  PIN o[87]
    DIRECTION OUTPUT ;
    USE SIGNAL ;
    PORT
      LAYER M5 ;
        RECT  10.608 55.968 10.632 56.16 ;
    END
  END o[87]
  PIN o[88]
    DIRECTION OUTPUT ;
    USE SIGNAL ;
    PORT
      LAYER M3 ;
        RECT  10.728 56.016 10.746 56.16 ;
    END
  END o[88]
  PIN o[89]
    DIRECTION OUTPUT ;
    USE SIGNAL ;
    PORT
      LAYER M5 ;
        RECT  10.8 55.968 10.824 56.16 ;
    END
  END o[89]
  PIN o[8]
    DIRECTION OUTPUT ;
    USE SIGNAL ;
    PORT
      LAYER M3 ;
        RECT  2.988 56.016 3.006 56.16 ;
    END
  END o[8]
  PIN o[90]
    DIRECTION OUTPUT ;
    USE SIGNAL ;
    PORT
      LAYER M3 ;
        RECT  10.908 56.016 10.926 56.16 ;
    END
  END o[90]
  PIN o[91]
    DIRECTION OUTPUT ;
    USE SIGNAL ;
    PORT
      LAYER M5 ;
        RECT  10.992 55.968 11.016 56.16 ;
    END
  END o[91]
  PIN o[92]
    DIRECTION OUTPUT ;
    USE SIGNAL ;
    PORT
      LAYER M3 ;
        RECT  11.088 56.016 11.106 56.16 ;
    END
  END o[92]
  PIN o[93]
    DIRECTION OUTPUT ;
    USE SIGNAL ;
    PORT
      LAYER M5 ;
        RECT  11.184 55.968 11.208 56.16 ;
    END
  END o[93]
  PIN o[94]
    DIRECTION OUTPUT ;
    USE SIGNAL ;
    PORT
      LAYER M3 ;
        RECT  11.304 56.016 11.322 56.16 ;
    END
  END o[94]
  PIN o[95]
    DIRECTION OUTPUT ;
    USE SIGNAL ;
    PORT
      LAYER M5 ;
        RECT  11.376 55.968 11.4 56.16 ;
    END
  END o[95]
  PIN o[96]
    DIRECTION OUTPUT ;
    USE SIGNAL ;
    PORT
      LAYER M3 ;
        RECT  11.484 56.016 11.502 56.16 ;
    END
  END o[96]
  PIN o[97]
    DIRECTION OUTPUT ;
    USE SIGNAL ;
    PORT
      LAYER M5 ;
        RECT  11.568 55.968 11.592 56.16 ;
    END
  END o[97]
  PIN o[98]
    DIRECTION OUTPUT ;
    USE SIGNAL ;
    PORT
      LAYER M3 ;
        RECT  11.664 56.016 11.682 56.16 ;
    END
  END o[98]
  PIN o[99]
    DIRECTION OUTPUT ;
    USE SIGNAL ;
    PORT
      LAYER M5 ;
        RECT  11.76 55.968 11.784 56.16 ;
    END
  END o[99]
  PIN o[9]
    DIRECTION OUTPUT ;
    USE SIGNAL ;
    PORT
      LAYER M5 ;
        RECT  3.072 55.968 3.096 56.16 ;
    END
  END o[9]
  PIN rs
    DIRECTION INPUT ;
    USE SIGNAL ;
    PORT
      LAYER M5 ;
        RECT  41.04 0 41.064 0.192 ;
    END
  END rs
  PIN VDD
    DIRECTION INOUT ;
    USE POWER ;
    PORT
      LAYER M5 ;
        RECT  53.892 2.151 54.012 54.009 ;
        RECT  51.192 2.151 51.312 54.009 ;
        RECT  48.492 2.151 48.612 54.009 ;
        RECT  45.792 2.151 45.912 54.009 ;
        RECT  43.092 2.151 43.212 54.009 ;
        RECT  40.392 2.151 40.512 54.009 ;
        RECT  37.692 2.151 37.812 54.009 ;
        RECT  34.992 2.151 35.112 54.009 ;
        RECT  32.292 2.151 32.412 54.009 ;
        RECT  29.592 2.151 29.712 54.009 ;
        RECT  26.892 2.151 27.012 54.009 ;
        RECT  24.192 2.151 24.312 54.009 ;
        RECT  21.492 2.151 21.612 54.009 ;
        RECT  18.792 2.151 18.912 54.009 ;
        RECT  16.092 2.151 16.212 54.009 ;
        RECT  13.392 2.151 13.512 54.009 ;
        RECT  10.692 2.151 10.812 54.009 ;
        RECT  7.992 2.151 8.112 54.009 ;
        RECT  5.292 2.151 5.412 54.009 ;
        RECT  2.592 2.151 2.712 54.009 ;
    END
  END VDD
  PIN VSS
    DIRECTION INOUT ;
    USE GROUND ;
    PORT
      LAYER M5 ;
        RECT  53.7 2.137 53.82 54.023 ;
        RECT  51 2.137 51.12 54.023 ;
        RECT  48.3 2.137 48.42 54.023 ;
        RECT  45.6 2.137 45.72 54.023 ;
        RECT  42.9 2.137 43.02 54.023 ;
        RECT  40.2 2.137 40.32 54.023 ;
        RECT  37.5 2.137 37.62 54.023 ;
        RECT  34.8 2.137 34.92 54.023 ;
        RECT  32.1 2.137 32.22 54.023 ;
        RECT  29.4 2.137 29.52 54.023 ;
        RECT  26.7 2.137 26.82 54.023 ;
        RECT  24 2.137 24.12 54.023 ;
        RECT  21.3 2.137 21.42 54.023 ;
        RECT  18.6 2.137 18.72 54.023 ;
        RECT  15.9 2.137 16.02 54.023 ;
        RECT  13.2 2.137 13.32 54.023 ;
        RECT  10.5 2.137 10.62 54.023 ;
        RECT  7.8 2.137 7.92 54.023 ;
        RECT  5.1 2.137 5.22 54.023 ;
        RECT  2.4 2.137 2.52 54.023 ;
    END
  END VSS
  OBS
    LAYER RVTN ;
     RECT  2.16 2.16 54 2.295 ;
     RECT  2.16 2.565 54 2.835 ;
     RECT  2.16 3.105 54 3.375 ;
     RECT  2.16 3.645 54 3.915 ;
     RECT  2.16 4.185 54 4.455 ;
     RECT  2.16 4.725 54 4.995 ;
     RECT  2.16 5.265 54 5.535 ;
     RECT  2.16 5.805 54 6.075 ;
     RECT  2.16 6.345 54 6.615 ;
     RECT  2.16 6.885 54 7.155 ;
     RECT  2.16 7.425 54 7.695 ;
     RECT  2.16 7.965 54 8.235 ;
     RECT  2.16 8.505 54 8.775 ;
     RECT  2.16 9.045 54 9.315 ;
     RECT  2.16 9.585 54 9.855 ;
     RECT  2.16 10.125 54 10.395 ;
     RECT  2.16 10.665 54 10.935 ;
     RECT  2.16 11.205 54 11.475 ;
     RECT  2.16 11.745 54 12.015 ;
     RECT  2.16 12.285 54 12.555 ;
     RECT  2.16 12.825 54 13.095 ;
     RECT  2.16 13.365 54 13.635 ;
     RECT  2.16 13.905 54 14.175 ;
     RECT  2.16 14.445 54 14.715 ;
     RECT  2.16 14.985 54 15.255 ;
     RECT  2.16 15.525 54 15.795 ;
     RECT  2.16 16.065 54 16.335 ;
     RECT  2.16 16.605 54 16.875 ;
     RECT  2.16 17.145 54 17.415 ;
     RECT  2.16 17.685 54 17.955 ;
     RECT  2.16 18.225 54 18.495 ;
     RECT  2.16 18.765 54 19.035 ;
     RECT  2.16 19.305 54 19.575 ;
     RECT  2.16 19.845 54 20.115 ;
     RECT  2.16 20.385 54 20.655 ;
     RECT  2.16 20.925 54 21.195 ;
     RECT  2.16 21.465 54 21.735 ;
     RECT  2.16 22.005 54 22.275 ;
     RECT  2.16 22.545 54 22.815 ;
     RECT  2.16 23.085 54 23.355 ;
     RECT  2.16 23.625 54 23.895 ;
     RECT  2.16 24.165 54 24.435 ;
     RECT  2.16 24.705 54 24.975 ;
     RECT  2.16 25.245 54 25.515 ;
     RECT  2.16 25.785 54 26.055 ;
     RECT  2.16 26.325 54 26.595 ;
     RECT  2.16 26.865 54 27.135 ;
     RECT  2.16 27.405 54 27.675 ;
     RECT  2.16 27.945 54 28.215 ;
     RECT  2.16 28.485 54 28.755 ;
     RECT  2.16 29.025 54 29.295 ;
     RECT  2.16 29.565 54 29.835 ;
     RECT  2.16 30.105 54 30.375 ;
     RECT  2.16 30.645 54 30.915 ;
     RECT  2.16 31.185 54 31.455 ;
     RECT  2.16 31.725 54 31.995 ;
     RECT  2.16 32.265 54 32.535 ;
     RECT  2.16 32.805 54 33.075 ;
     RECT  2.16 33.345 54 33.615 ;
     RECT  2.16 33.885 54 34.155 ;
     RECT  2.16 34.425 54 34.695 ;
     RECT  2.16 34.965 54 35.235 ;
     RECT  2.16 35.505 54 35.775 ;
     RECT  2.16 36.045 54 36.315 ;
     RECT  2.16 36.585 54 36.855 ;
     RECT  2.16 37.125 54 37.395 ;
     RECT  2.16 37.665 54 37.935 ;
     RECT  2.16 38.205 54 38.475 ;
     RECT  2.16 38.745 54 39.015 ;
     RECT  2.16 39.285 54 39.555 ;
     RECT  2.16 39.825 54 40.095 ;
     RECT  2.16 40.365 54 40.635 ;
     RECT  2.16 40.905 54 41.175 ;
     RECT  2.16 41.445 54 41.715 ;
     RECT  2.16 41.985 54 42.255 ;
     RECT  2.16 42.525 54 42.795 ;
     RECT  2.16 43.065 54 43.335 ;
     RECT  2.16 43.605 54 43.875 ;
     RECT  2.16 44.145 54 44.415 ;
     RECT  2.16 44.685 54 44.955 ;
     RECT  2.16 45.225 54 45.495 ;
     RECT  2.16 45.765 54 46.035 ;
     RECT  2.16 46.305 54 46.575 ;
     RECT  2.16 46.845 54 47.115 ;
     RECT  2.16 47.385 54 47.655 ;
     RECT  2.16 47.925 54 48.195 ;
     RECT  2.16 48.465 54 48.735 ;
     RECT  2.16 49.005 54 49.275 ;
     RECT  2.16 49.545 54 49.815 ;
     RECT  2.16 50.085 54 50.355 ;
     RECT  2.16 50.625 54 50.895 ;
     RECT  2.16 51.165 54 51.435 ;
     RECT  2.16 51.705 54 51.975 ;
     RECT  2.16 52.245 54 52.515 ;
     RECT  2.16 52.785 54 53.055 ;
     RECT  2.16 53.325 54 53.595 ;
     RECT  2.16 53.865 54 54 ;
    LAYER RVTP ;
     RECT  2.16 2.295 54 2.565 ;
     RECT  2.16 2.835 54 3.105 ;
     RECT  2.16 3.375 54 3.645 ;
     RECT  2.16 3.915 54 4.185 ;
     RECT  2.16 4.455 54 4.725 ;
     RECT  2.16 4.995 54 5.265 ;
     RECT  2.16 5.535 54 5.805 ;
     RECT  2.16 6.075 54 6.345 ;
     RECT  2.16 6.615 54 6.885 ;
     RECT  2.16 7.155 54 7.425 ;
     RECT  2.16 7.695 54 7.965 ;
     RECT  2.16 8.235 54 8.505 ;
     RECT  2.16 8.775 54 9.045 ;
     RECT  2.16 9.315 54 9.585 ;
     RECT  2.16 9.855 54 10.125 ;
     RECT  2.16 10.395 54 10.665 ;
     RECT  2.16 10.935 54 11.205 ;
     RECT  2.16 11.475 54 11.745 ;
     RECT  2.16 12.015 54 12.285 ;
     RECT  2.16 12.555 54 12.825 ;
     RECT  2.16 13.095 54 13.365 ;
     RECT  2.16 13.635 54 13.905 ;
     RECT  2.16 14.175 54 14.445 ;
     RECT  2.16 14.715 54 14.985 ;
     RECT  2.16 15.255 54 15.525 ;
     RECT  2.16 15.795 54 16.065 ;
     RECT  2.16 16.335 54 16.605 ;
     RECT  2.16 16.875 54 17.145 ;
     RECT  2.16 17.415 54 17.685 ;
     RECT  2.16 17.955 54 18.225 ;
     RECT  2.16 18.495 54 18.765 ;
     RECT  2.16 19.035 54 19.305 ;
     RECT  2.16 19.575 54 19.845 ;
     RECT  2.16 20.115 54 20.385 ;
     RECT  2.16 20.655 54 20.925 ;
     RECT  2.16 21.195 54 21.465 ;
     RECT  2.16 21.735 54 22.005 ;
     RECT  2.16 22.275 54 22.545 ;
     RECT  2.16 22.815 54 23.085 ;
     RECT  2.16 23.355 54 23.625 ;
     RECT  2.16 23.895 54 24.165 ;
     RECT  2.16 24.435 54 24.705 ;
     RECT  2.16 24.975 54 25.245 ;
     RECT  2.16 25.515 54 25.785 ;
     RECT  2.16 26.055 54 26.325 ;
     RECT  2.16 26.595 54 26.865 ;
     RECT  2.16 27.135 54 27.405 ;
     RECT  2.16 27.675 54 27.945 ;
     RECT  2.16 28.215 54 28.485 ;
     RECT  2.16 28.755 54 29.025 ;
     RECT  2.16 29.295 54 29.565 ;
     RECT  2.16 29.835 54 30.105 ;
     RECT  2.16 30.375 54 30.645 ;
     RECT  2.16 30.915 54 31.185 ;
     RECT  2.16 31.455 54 31.725 ;
     RECT  2.16 31.995 54 32.265 ;
     RECT  2.16 32.535 54 32.805 ;
     RECT  2.16 33.075 54 33.345 ;
     RECT  2.16 33.615 54 33.885 ;
     RECT  2.16 34.155 54 34.425 ;
     RECT  2.16 34.695 54 34.965 ;
     RECT  2.16 35.235 54 35.505 ;
     RECT  2.16 35.775 54 36.045 ;
     RECT  2.16 36.315 54 36.585 ;
     RECT  2.16 36.855 54 37.125 ;
     RECT  2.16 37.395 54 37.665 ;
     RECT  2.16 37.935 54 38.205 ;
     RECT  2.16 38.475 54 38.745 ;
     RECT  2.16 39.015 54 39.285 ;
     RECT  2.16 39.555 54 39.825 ;
     RECT  2.16 40.095 54 40.365 ;
     RECT  2.16 40.635 54 40.905 ;
     RECT  2.16 41.175 54 41.445 ;
     RECT  2.16 41.715 54 41.985 ;
     RECT  2.16 42.255 54 42.525 ;
     RECT  2.16 42.795 54 43.065 ;
     RECT  2.16 43.335 54 43.605 ;
     RECT  2.16 43.875 54 44.145 ;
     RECT  2.16 44.415 54 44.685 ;
     RECT  2.16 44.955 54 45.225 ;
     RECT  2.16 45.495 54 45.765 ;
     RECT  2.16 46.035 54 46.305 ;
     RECT  2.16 46.575 54 46.845 ;
     RECT  2.16 47.115 54 47.385 ;
     RECT  2.16 47.655 54 47.925 ;
     RECT  2.16 48.195 54 48.465 ;
     RECT  2.16 48.735 54 49.005 ;
     RECT  2.16 49.275 54 49.545 ;
     RECT  2.16 49.815 54 50.085 ;
     RECT  2.16 50.355 54 50.625 ;
     RECT  2.16 50.895 54 51.165 ;
     RECT  2.16 51.435 54 51.705 ;
     RECT  2.16 51.975 54 52.245 ;
     RECT  2.16 52.515 54 52.785 ;
     RECT  2.16 53.055 54 53.325 ;
     RECT  2.16 53.595 54 53.865 ;
    LAYER M1 ;
     RECT  2.16 2.151 54 54.009 ;
    LAYER M2 ;
     RECT  2.16 2.151 2.371 54.009 ;
     RECT  2.371 2.151 2.759 54.702 ;
     RECT  2.759 2.151 2.795 54.63 ;
     RECT  2.795 2.151 4.135 54.009 ;
     RECT  4.135 2.151 4.459 54.432 ;
     RECT  4.459 2.151 4.559 54.702 ;
     RECT  4.559 2.151 5.287 54.432 ;
     RECT  5.287 2.151 5.531 54.702 ;
     RECT  5.531 2.151 6.655 54.432 ;
     RECT  6.655 2.151 8.627 54.702 ;
     RECT  8.779 55.296 11.147 55.314 ;
     RECT  8.627 2.151 13.207 54.432 ;
     RECT  13.207 2.151 13.559 54.702 ;
     RECT  13.559 2.151 16.123 54.432 ;
     RECT  16.123 2.151 16.699 54.702 ;
     RECT  16.699 2.151 16.799 55.404 ;
     RECT  16.799 2.151 19.687 54.702 ;
     RECT  19.687 2.151 19.823 55.278 ;
     RECT  19.823 2.151 20.903 54.702 ;
     RECT  24.043 55.296 25.367 55.314 ;
     RECT  27.355 55.296 28.355 55.314 ;
     RECT  29.227 56.07 29.263 56.088 ;
     RECT  29.263 55.998 29.363 56.088 ;
     RECT  32.755 55.998 32.791 56.016 ;
     RECT  32.791 55.998 32.891 56.088 ;
     RECT  20.903 2.151 33.151 54.432 ;
     RECT  33.151 2.151 36.239 54.702 ;
     RECT  36.239 2.151 37.255 54.009 ;
     RECT  37.255 2.151 37.795 54.09 ;
     RECT  37.795 2.151 37.859 54.702 ;
     RECT  37.859 2.151 38.767 54.63 ;
     RECT  38.767 2.151 40.991 54.702 ;
     RECT  41.791 55.116 41.891 55.134 ;
     RECT  40.991 2.151 41.899 54.009 ;
     RECT  41.899 2.151 42.763 54.162 ;
     RECT  42.763 2.151 43.223 54.234 ;
     RECT  43.223 2.151 44.167 54.126 ;
     RECT  44.167 2.151 44.563 54.162 ;
     RECT  44.563 2.151 44.671 54.279 ;
     RECT  44.671 2.151 46.103 54.396 ;
     RECT  45.895 55.296 46.507 55.314 ;
     RECT  46.507 55.296 46.535 55.404 ;
     RECT  46.535 55.386 46.607 55.404 ;
     RECT  46.103 2.151 47.299 54.324 ;
     RECT  47.299 2.151 48.667 54.738 ;
     RECT  48.667 2.151 49.711 55.314 ;
     RECT  49.711 2.151 50.251 55.359 ;
     RECT  50.251 2.151 51.295 56.052 ;
     RECT  51.295 2.106 51.863 56.052 ;
     RECT  51.863 2.151 52.115 56.052 ;
     RECT  52.115 2.151 52.627 55.008 ;
     RECT  52.115 56.034 53.023 56.052 ;
     RECT  53.023 55.962 53.051 56.052 ;
     RECT  52.627 2.034 53.087 55.008 ;
     RECT  53.087 54.99 53.303 55.008 ;
     RECT  53.051 55.962 53.483 55.98 ;
     RECT  53.087 2.034 53.591 54.126 ;
     RECT  53.591 2.106 53.699 54.126 ;
     RECT  53.699 2.106 54 54.009 ;
     RECT  54 2.106 54.012 53.928 ;
     RECT  54.012 2.106 54.167 13.626 ;
     RECT  54.012 14.418 54.167 53.928 ;
     RECT  54.167 14.418 54.419 53.856 ;
     RECT  54.419 14.418 54.635 33.948 ;
     RECT  54.167 2.268 54.707 13.626 ;
     RECT  54.419 34.704 54.707 53.856 ;
     RECT  54.707 2.268 54.743 7.416 ;
     RECT  54.707 8.208 54.743 13.626 ;
     RECT  54.635 14.418 54.743 15.552 ;
     RECT  54.635 16.308 54.743 33.948 ;
     RECT  54.707 34.704 54.743 53.316 ;
     RECT  54.743 10.98 54.779 13.626 ;
     RECT  54.743 16.308 54.779 19.638 ;
     RECT  54.743 25.452 54.779 33.066 ;
     RECT  54.743 33.93 54.779 33.948 ;
     RECT  54.743 34.704 54.779 52.848 ;
     RECT  54.743 8.208 54.815 10.188 ;
     RECT  54.779 16.308 54.815 17.244 ;
     RECT  54.743 23.166 54.815 24.498 ;
     RECT  54.779 29.61 54.815 33.066 ;
     RECT  54.815 23.166 54.851 24.228 ;
     RECT  54.815 29.808 54.851 33.066 ;
     RECT  54.851 23.166 54.887 23.184 ;
     RECT  54.851 30.888 54.887 33.066 ;
     RECT  54.815 8.748 54.923 10.188 ;
     RECT  54.851 24.138 54.923 24.228 ;
     RECT  54.779 40.878 54.959 52.038 ;
     RECT  54.779 37.404 55.283 40.122 ;
     RECT  54.743 2.376 55.319 7.218 ;
     RECT  54.923 8.946 55.319 10.188 ;
     RECT  54.779 10.98 55.319 12.924 ;
     RECT  54.743 14.526 55.319 15.552 ;
     RECT  54.815 16.578 55.319 17.244 ;
     RECT  54.779 18.036 55.319 19.638 ;
     RECT  54.743 20.394 55.319 22.149 ;
     RECT  54.923 24.138 55.319 24.156 ;
     RECT  54.779 25.452 55.319 28.746 ;
     RECT  54.851 29.808 55.319 30.096 ;
     RECT  54.887 30.924 55.319 33.066 ;
     RECT  55.283 37.44 55.319 40.122 ;
     RECT  54.959 40.878 55.319 45.486 ;
     RECT  54.959 46.278 55.319 52.038 ;
     RECT  54.779 52.83 55.319 52.848 ;
     RECT  55.319 3.888 55.355 6.066 ;
     RECT  55.319 6.966 55.355 6.984 ;
     RECT  55.319 8.946 55.355 10.152 ;
     RECT  55.319 11.718 55.355 12.384 ;
     RECT  55.319 15.534 55.355 15.552 ;
     RECT  55.319 16.578 55.355 16.866 ;
     RECT  55.319 18.036 55.355 19.404 ;
     RECT  55.319 21.816 55.355 22.149 ;
     RECT  55.319 25.452 55.355 26.046 ;
     RECT  55.319 26.946 55.355 27.36 ;
     RECT  55.319 31.428 55.355 31.824 ;
     RECT  54.779 34.704 55.355 36.306 ;
     RECT  55.319 41.418 55.355 45.018 ;
     RECT  55.319 46.278 55.355 48.222 ;
     RECT  55.319 48.978 55.355 49.806 ;
     RECT  55.319 50.67 55.355 51.264 ;
     RECT  55.319 52.02 55.355 52.038 ;
     RECT  55.355 5.346 55.391 5.904 ;
     RECT  55.355 8.946 55.391 9.576 ;
     RECT  55.355 16.848 55.391 16.866 ;
     RECT  55.355 18.774 55.391 18.792 ;
     RECT  55.319 20.97 55.391 20.988 ;
     RECT  55.355 25.452 55.391 25.47 ;
     RECT  55.355 26.946 55.391 26.964 ;
     RECT  55.355 34.704 55.391 35.226 ;
     RECT  55.355 36.288 55.391 36.306 ;
     RECT  55.319 38.016 55.391 40.086 ;
     RECT  55.355 41.418 55.391 43.749 ;
     RECT  55.355 44.496 55.391 44.514 ;
     RECT  55.355 46.278 55.391 47.952 ;
     RECT  55.355 48.978 55.391 49.572 ;
     RECT  55.355 51.246 55.391 51.264 ;
     RECT  55.391 9.054 55.427 9.576 ;
     RECT  55.355 21.861 55.427 22.149 ;
     RECT  55.391 35.208 55.427 35.226 ;
     RECT  55.391 38.016 55.427 39.114 ;
     RECT  55.391 40.068 55.427 40.086 ;
     RECT  55.391 41.454 55.427 42.012 ;
     RECT  55.391 42.768 55.427 43.749 ;
     RECT  55.391 47.628 55.427 47.952 ;
     RECT  55.391 49.554 55.427 49.572 ;
     RECT  55.427 38.142 55.463 39.114 ;
     RECT  55.427 41.688 55.463 42.012 ;
     RECT  55.427 47.934 55.463 47.952 ;
     RECT  55.463 39.024 55.499 39.042 ;
     RECT  55.463 41.688 55.499 41.94 ;
     RECT  55.427 42.768 55.499 43.596 ;
     RECT  55.499 42.768 55.535 43.434 ;
     RECT  55.535 42.768 55.571 42.786 ;
     RECT  55.463 38.142 55.967 38.16 ;
     RECT  55.391 46.278 56.003 46.764 ;
     RECT  55.939 22.248 56.039 22.266 ;
    LAYER M3 ;
     RECT  15.12 0.108 15.138 0.173 ;
     RECT  47.916 1.963 47.934 2.059 ;
     RECT  48.996 1.963 49.014 2.059 ;
     RECT  52.632 2.029 52.65 2.059 ;
     RECT  52.632 2.059 52.83 2.101 ;
     RECT  53.568 2.029 53.586 2.101 ;
     RECT  10.692 2.059 10.71 2.143 ;
     RECT  18.792 2.059 18.81 2.143 ;
     RECT  29.592 2.059 29.61 2.143 ;
     RECT  37.692 2.059 37.71 2.143 ;
     RECT  51.3 2.101 51.858 2.143 ;
     RECT  13.215 2.143 13.305 2.191 ;
     RECT  21.315 2.143 21.405 2.191 ;
     RECT  42.915 2.143 43.005 2.191 ;
     RECT  45.615 2.143 45.705 2.191 ;
     RECT  47.052 2.155 47.07 2.191 ;
     RECT  47.916 2.059 49.014 2.191 ;
     RECT  49.932 2.059 49.95 2.191 ;
     RECT  13.104 2.191 13.41 2.237 ;
     RECT  14.832 2.059 14.85 2.237 ;
     RECT  21.204 2.191 21.51 2.237 ;
     RECT  41.184 1.723 41.202 2.263 ;
     RECT  49.86 2.191 49.95 2.263 ;
     RECT  52.632 2.101 54.162 2.263 ;
     RECT  45.615 2.191 46.062 2.299 ;
     RECT  47.052 2.191 49.014 2.299 ;
     RECT  49.86 2.263 50.13 2.299 ;
     RECT  51.015 2.143 51.858 2.299 ;
     RECT  45.108 2.299 46.062 2.335 ;
     RECT  46.908 2.299 51.858 2.335 ;
     RECT  45.108 2.335 51.858 2.371 ;
     RECT  52.632 2.263 54.738 2.371 ;
     RECT  2.415 2.143 2.505 2.413 ;
     RECT  5.115 2.143 5.205 2.413 ;
     RECT  7.815 2.143 7.905 2.413 ;
     RECT  10.515 2.143 10.71 2.413 ;
     RECT  13.215 2.237 13.41 2.413 ;
     RECT  15.915 2.143 16.005 2.413 ;
     RECT  18.615 2.143 18.81 2.413 ;
     RECT  21.315 2.237 21.51 2.413 ;
     RECT  24.015 2.143 24.105 2.413 ;
     RECT  26.676 2.059 26.874 2.413 ;
     RECT  29.415 2.143 29.61 2.413 ;
     RECT  32.115 2.143 32.205 2.413 ;
     RECT  34.815 2.143 34.905 2.413 ;
     RECT  37.515 2.143 37.71 2.413 ;
     RECT  40.215 2.143 40.305 2.413 ;
     RECT  41.184 2.263 41.634 2.413 ;
     RECT  42.732 2.191 43.005 2.413 ;
     RECT  43.848 2.263 43.866 2.413 ;
     RECT  42.732 2.413 43.866 2.489 ;
     RECT  40.215 2.413 41.634 2.525 ;
     RECT  42.732 2.489 43.197 2.525 ;
     RECT  7.815 2.413 8.097 2.539 ;
     RECT  41.436 2.525 41.634 2.561 ;
     RECT  45.108 2.371 55.314 2.587 ;
     RECT  22.932 2.731 22.95 2.813 ;
     RECT  26.676 2.413 26.997 2.813 ;
     RECT  30.78 2.059 30.798 2.861 ;
     RECT  38.772 2.059 38.79 2.861 ;
     RECT  45.036 2.587 55.314 2.861 ;
     RECT  32.115 2.413 32.397 3.037 ;
     RECT  41.652 3.181 41.67 3.245 ;
     RECT  42.915 2.525 43.197 3.307 ;
     RECT  45.216 2.861 55.314 3.749 ;
     RECT  45.288 3.749 55.314 3.883 ;
     RECT  45.288 3.883 55.35 3.983 ;
     RECT  4.356 4.189 4.374 4.801 ;
     RECT  34.815 2.413 35.097 4.801 ;
     RECT  42.552 3.307 43.197 4.939 ;
     RECT  10.515 2.413 10.797 5.071 ;
     RECT  9.756 5.071 10.797 5.117 ;
     RECT  5.115 2.413 5.397 5.161 ;
     RECT  45.576 3.983 55.35 5.179 ;
     RECT  45.504 5.179 55.35 5.227 ;
     RECT  45.036 5.227 55.35 5.341 ;
     RECT  42.552 4.939 43.614 5.515 ;
     RECT  41.58 4.693 41.598 5.881 ;
     RECT  42.552 5.515 43.83 5.881 ;
     RECT  45.036 5.341 55.386 5.909 ;
     RECT  9.828 5.117 10.797 5.995 ;
     RECT  5.115 5.161 5.634 6.007 ;
     RECT  7.128 2.539 8.097 6.007 ;
     RECT  45.036 5.909 55.35 6.029 ;
     RECT  45.612 6.029 55.35 6.071 ;
     RECT  4.284 4.801 4.374 6.079 ;
     RECT  5.115 6.007 8.097 6.079 ;
     RECT  45.612 6.071 55.314 6.179 ;
     RECT  39.168 5.269 39.186 6.421 ;
     RECT  40.215 2.525 40.497 6.421 ;
     RECT  39.168 6.421 40.497 6.511 ;
     RECT  38.808 6.511 40.497 6.539 ;
     RECT  34.092 4.801 35.097 6.547 ;
     RECT  38.808 6.539 39.186 6.611 ;
     RECT  39.924 6.539 40.497 6.611 ;
     RECT  41.58 5.881 43.83 6.889 ;
     RECT  31.176 6.853 31.194 6.961 ;
     RECT  45.615 6.179 55.314 6.961 ;
     RECT  26.715 2.813 26.997 7.051 ;
     RECT  40.215 6.611 40.497 7.051 ;
     RECT  30.528 6.961 31.194 7.079 ;
     RECT  25.848 6.691 25.866 7.231 ;
     RECT  25.416 7.231 25.866 7.349 ;
     RECT  25.416 7.349 25.434 7.393 ;
     RECT  29.415 2.413 29.697 7.435 ;
     RECT  30.78 7.079 31.194 7.435 ;
     RECT  39.168 6.611 39.186 7.483 ;
     RECT  29.415 7.435 29.718 7.723 ;
     RECT  37.515 2.413 37.797 7.723 ;
     RECT  38.88 7.483 39.186 7.723 ;
     RECT  28.404 7.627 28.422 7.771 ;
     RECT  29.415 7.723 29.79 7.771 ;
     RECT  45.615 6.961 55.35 7.861 ;
     RECT  22.932 7.771 22.95 7.897 ;
     RECT  45.54 7.861 55.35 7.897 ;
     RECT  28.404 7.771 29.79 7.901 ;
     RECT  37.515 7.723 37.89 7.933 ;
     RECT  45.396 7.897 55.35 7.949 ;
     RECT  41.58 6.889 43.866 7.963 ;
     RECT  33.408 6.547 35.097 8.239 ;
     RECT  30.78 7.435 31.338 8.299 ;
     RECT  41.544 7.963 43.866 8.429 ;
     RECT  41.58 8.429 43.866 8.539 ;
     RECT  45.615 7.949 54.918 8.683 ;
     RECT  45.615 8.683 55.314 8.779 ;
     RECT  33.408 8.239 35.442 8.815 ;
     RECT  36.396 7.627 36.414 8.815 ;
     RECT  45.615 8.779 55.35 8.941 ;
     RECT  41.58 8.539 44.586 8.969 ;
     RECT  45.615 8.941 55.386 9.049 ;
     RECT  33.408 8.815 36.414 9.211 ;
     RECT  37.515 7.933 37.962 9.211 ;
     RECT  20.376 4.153 20.394 9.307 ;
     RECT  21.315 2.413 21.597 9.307 ;
     RECT  38.772 7.723 39.186 9.341 ;
     RECT  28.404 7.901 29.697 9.661 ;
     RECT  28.332 9.661 29.697 9.931 ;
     RECT  45.615 9.049 55.422 9.965 ;
     RECT  26.604 7.051 26.997 10.021 ;
     RECT  18.615 2.413 18.897 10.093 ;
     RECT  45.615 9.965 55.35 10.157 ;
     RECT  39.168 9.341 39.186 10.363 ;
     RECT  28.116 9.931 29.697 10.399 ;
     RECT  30.672 8.299 31.338 10.399 ;
     RECT  33.408 9.211 37.962 10.459 ;
     RECT  38.772 10.363 39.186 10.459 ;
     RECT  28.116 10.399 31.338 10.651 ;
     RECT  45.615 10.157 55.314 10.699 ;
     RECT  25.236 7.393 25.434 10.831 ;
     RECT  26.46 10.021 26.997 10.831 ;
     RECT  33.408 10.459 39.186 10.973 ;
     RECT  25.236 10.831 26.997 11.173 ;
     RECT  27.756 10.651 31.338 11.173 ;
     RECT  45.36 10.699 55.314 11.323 ;
     RECT  33.408 10.973 38.358 11.707 ;
     RECT  39.168 10.973 39.186 11.707 ;
     RECT  45.36 11.323 55.35 12.389 ;
     RECT  45.36 12.389 55.314 12.901 ;
     RECT  32.115 3.037 32.562 13.051 ;
     RECT  33.408 11.707 39.186 13.051 ;
     RECT  32.115 13.051 39.186 13.369 ;
     RECT  45.036 12.901 55.314 13.675 ;
     RECT  2.415 2.413 2.697 14.071 ;
     RECT  3.42 3.721 3.438 14.071 ;
     RECT  32.115 13.369 39.258 14.443 ;
     RECT  40.215 7.051 40.626 14.443 ;
     RECT  32.115 14.443 40.626 14.881 ;
     RECT  44.712 13.675 55.314 15.529 ;
     RECT  25.236 11.173 31.338 15.727 ;
     RECT  32.115 14.881 40.698 15.727 ;
     RECT  15.915 2.413 16.197 15.961 ;
     RECT  22.464 7.897 22.95 15.961 ;
     RECT  24.015 2.413 24.297 15.961 ;
     RECT  25.236 15.727 40.698 15.961 ;
     RECT  15.552 15.961 16.197 16.141 ;
     RECT  22.464 15.961 40.698 16.331 ;
     RECT  12.132 2.767 12.15 16.363 ;
     RECT  13.215 2.413 13.497 16.363 ;
     RECT  15.552 16.141 16.794 16.363 ;
     RECT  20.376 9.307 21.597 16.363 ;
     RECT  14.832 16.363 16.794 16.375 ;
     RECT  24.012 16.331 40.698 16.439 ;
     RECT  44.712 15.529 55.35 16.507 ;
     RECT  22.464 16.331 23.274 16.529 ;
     RECT  12.132 16.363 13.59 16.541 ;
     RECT  14.832 16.375 17.37 16.541 ;
     RECT  22.464 16.529 23.202 16.565 ;
     RECT  15.336 16.541 17.37 16.573 ;
     RECT  18.615 10.093 19.566 16.573 ;
     RECT  20.376 16.363 21.69 16.681 ;
     RECT  22.464 16.565 22.95 16.681 ;
     RECT  20.376 16.681 22.95 16.799 ;
     RECT  44.712 16.507 55.386 16.871 ;
     RECT  24.015 16.439 40.698 16.943 ;
     RECT  44.712 16.871 55.314 17.105 ;
     RECT  25.236 16.943 40.698 17.141 ;
     RECT  20.376 16.799 21.654 17.375 ;
     RECT  25.236 17.141 40.626 17.959 ;
     RECT  45.036 17.105 55.314 18.031 ;
     RECT  15.336 16.573 19.566 18.427 ;
     RECT  24.015 16.943 24.297 18.499 ;
     RECT  25.02 17.959 40.626 18.499 ;
     RECT  45.036 18.031 55.35 18.527 ;
     RECT  20.376 17.375 21.597 18.667 ;
     RECT  22.464 16.799 22.95 18.733 ;
     RECT  24.015 18.499 40.626 18.733 ;
     RECT  45.036 18.527 53.997 18.749 ;
     RECT  54.72 18.527 55.35 18.769 ;
     RECT  20.376 18.667 21.69 18.797 ;
     RECT  45.18 18.749 53.997 18.797 ;
     RECT  22.464 18.733 40.626 18.805 ;
     RECT  54.72 18.769 55.386 18.989 ;
     RECT  15.336 18.427 19.602 19.111 ;
     RECT  15.336 19.111 19.638 19.243 ;
     RECT  20.376 18.797 21.597 19.243 ;
     RECT  54.72 18.989 55.35 19.409 ;
     RECT  45.36 18.797 53.997 19.435 ;
     RECT  54.72 19.409 55.314 19.435 ;
     RECT  15.336 19.243 21.597 19.483 ;
     RECT  14.832 19.483 21.597 19.613 ;
     RECT  45.36 19.435 55.314 19.643 ;
     RECT  15.336 19.613 21.597 19.651 ;
     RECT  22.392 18.805 40.626 19.651 ;
     RECT  41.58 8.969 43.866 19.651 ;
     RECT  15.336 19.651 40.626 19.913 ;
     RECT  2.415 14.071 3.438 20.155 ;
     RECT  45.36 19.643 54.81 20.155 ;
     RECT  45.288 20.155 54.81 20.192 ;
     RECT  45.36 20.192 54.81 20.389 ;
     RECT  12.132 16.541 13.497 20.893 ;
     RECT  9.396 5.995 10.797 20.965 ;
     RECT  45.36 20.389 55.314 20.965 ;
     RECT  45.36 20.965 55.386 21.433 ;
     RECT  45.072 21.433 55.386 21.485 ;
     RECT  11.88 20.893 13.497 21.541 ;
     RECT  41.58 19.651 43.902 21.767 ;
     RECT  45.36 21.485 55.386 21.856 ;
     RECT  15.336 19.913 39.186 22.001 ;
     RECT  2.415 20.155 3.474 22.219 ;
     RECT  45.36 21.856 55.422 22.219 ;
     RECT  45.36 22.219 55.962 22.243 ;
     RECT  45.36 22.243 56.034 22.301 ;
     RECT  45.36 22.301 55.422 22.315 ;
     RECT  45.036 22.315 55.422 22.445 ;
     RECT  2.415 22.219 3.546 22.621 ;
     RECT  4.284 6.079 8.097 22.621 ;
     RECT  45.036 22.445 54.882 22.711 ;
     RECT  15.336 22.001 38.358 22.819 ;
     RECT  39.096 22.001 39.186 22.819 ;
     RECT  15.336 22.819 39.186 22.855 ;
     RECT  41.58 21.767 43.866 23.161 ;
     RECT  44.712 22.711 54.882 23.161 ;
     RECT  41.58 23.161 54.882 23.621 ;
     RECT  44.712 23.621 54.882 23.707 ;
     RECT  15.336 22.855 39.258 23.827 ;
     RECT  14.832 23.827 39.258 23.899 ;
     RECT  14.58 23.899 39.258 23.927 ;
     RECT  44.712 23.707 55.314 24.161 ;
     RECT  44.712 24.161 54.918 24.269 ;
     RECT  15.336 23.927 39.258 24.439 ;
     RECT  40.215 19.913 40.626 24.439 ;
     RECT  41.58 23.621 43.866 24.629 ;
     RECT  45.216 24.269 54.918 24.629 ;
     RECT  14.58 23.927 14.598 24.943 ;
     RECT  15.336 24.439 40.626 24.943 ;
     RECT  45.288 24.629 54.918 25.339 ;
     RECT  11.88 21.541 13.806 25.411 ;
     RECT  14.58 24.943 40.626 25.411 ;
     RECT  45.288 25.339 55.314 25.447 ;
     RECT  45.288 25.447 55.386 25.771 ;
     RECT  45.18 25.771 55.386 25.949 ;
     RECT  45.18 25.949 55.35 26.051 ;
     RECT  11.88 25.411 40.626 26.093 ;
     RECT  45.18 26.051 55.314 26.131 ;
     RECT  45 26.131 55.314 26.393 ;
     RECT  9.396 20.965 11.106 26.491 ;
     RECT  11.88 26.093 38.358 26.827 ;
     RECT  39.096 26.093 40.626 26.827 ;
     RECT  45.036 26.393 55.314 26.941 ;
     RECT  45.036 26.941 55.386 27.115 ;
     RECT  45 27.115 55.386 27.293 ;
     RECT  41.796 24.629 43.866 27.365 ;
     RECT  45 27.293 55.35 27.365 ;
     RECT  11.88 26.827 40.626 27.473 ;
     RECT  32.115 27.473 40.626 27.743 ;
     RECT  9.36 26.491 11.106 27.751 ;
     RECT  11.88 27.473 31.338 27.751 ;
     RECT  32.115 27.743 36.774 27.779 ;
     RECT  32.115 27.779 33.678 27.869 ;
     RECT  32.115 27.869 33.462 28.049 ;
     RECT  45 27.365 55.314 28.751 ;
     RECT  34.56 27.779 36.774 28.795 ;
     RECT  37.515 27.743 40.626 28.795 ;
     RECT  41.796 27.365 43.83 28.831 ;
     RECT  45 28.751 54.774 28.831 ;
     RECT  41.796 28.831 54.774 29.129 ;
     RECT  34.56 28.795 40.626 29.363 ;
     RECT  45.036 29.129 54.774 29.525 ;
     RECT  2.415 22.621 8.097 29.533 ;
     RECT  45.36 29.525 54.774 29.563 ;
     RECT  2.415 29.533 8.622 29.569 ;
     RECT  9.36 27.751 31.338 29.569 ;
     RECT  36.396 29.363 40.626 29.659 ;
     RECT  36.396 29.659 40.662 29.831 ;
     RECT  37.515 29.831 40.662 29.839 ;
     RECT  32.115 28.049 33.426 29.903 ;
     RECT  2.415 29.569 31.338 30.001 ;
     RECT  32.115 29.903 32.562 30.001 ;
     RECT  37.515 29.839 40.77 30.029 ;
     RECT  37.515 30.029 40.662 30.065 ;
     RECT  41.796 29.129 43.83 30.299 ;
     RECT  45.36 29.563 55.314 30.331 ;
     RECT  45.216 30.331 55.314 30.407 ;
     RECT  36.396 29.831 36.594 30.649 ;
     RECT  37.515 30.065 40.626 30.649 ;
     RECT  36.396 30.649 40.626 30.811 ;
     RECT  36.396 30.811 40.77 30.839 ;
     RECT  37.515 30.839 40.77 30.919 ;
     RECT  41.796 30.299 43.758 30.919 ;
     RECT  45.504 30.407 55.314 31.195 ;
     RECT  45.18 31.195 55.314 31.261 ;
     RECT  34.56 29.363 35.622 31.381 ;
     RECT  45.144 31.261 55.314 31.423 ;
     RECT  34.488 31.381 35.622 31.424 ;
     RECT  34.524 31.424 35.622 31.517 ;
     RECT  45.144 31.423 55.35 31.531 ;
     RECT  37.515 30.919 43.758 31.649 ;
     RECT  36.396 30.839 36.594 31.693 ;
     RECT  37.515 31.649 38.358 31.693 ;
     RECT  39.096 31.649 43.758 31.693 ;
     RECT  45.108 31.531 55.35 31.693 ;
     RECT  2.415 30.001 32.562 31.765 ;
     RECT  33.408 29.903 33.426 31.765 ;
     RECT  39.096 31.693 55.35 31.949 ;
     RECT  36.396 31.693 38.358 31.991 ;
     RECT  36.396 31.991 36.594 32.063 ;
     RECT  34.56 31.517 35.622 32.539 ;
     RECT  34.524 32.539 35.622 32.639 ;
     RECT  39.096 31.949 55.314 32.717 ;
     RECT  37.515 31.991 38.358 32.773 ;
     RECT  39.096 32.717 53.997 32.773 ;
     RECT  2.415 31.765 33.426 32.971 ;
     RECT  2.415 32.971 33.642 33.385 ;
     RECT  2.415 33.385 33.714 33.421 ;
     RECT  37.515 32.773 53.997 33.451 ;
     RECT  54.72 32.717 55.314 33.451 ;
     RECT  2.415 33.421 33.822 33.511 ;
     RECT  34.56 32.639 35.622 33.511 ;
     RECT  37.515 33.451 55.314 33.869 ;
     RECT  2.415 33.511 35.622 34.159 ;
     RECT  36.396 32.063 36.414 34.159 ;
     RECT  37.515 33.869 54.774 34.457 ;
     RECT  41.508 34.457 54.774 34.529 ;
     RECT  41.796 34.529 54.774 34.699 ;
     RECT  2.415 34.159 36.414 34.997 ;
     RECT  41.796 34.699 55.386 35.203 ;
     RECT  37.515 34.457 40.626 35.473 ;
     RECT  41.796 35.203 55.422 35.473 ;
     RECT  36.396 34.997 36.414 35.779 ;
     RECT  36.396 35.779 36.63 35.851 ;
     RECT  2.415 34.997 35.55 36.013 ;
     RECT  36.36 35.851 36.666 36.013 ;
     RECT  37.515 35.473 55.422 36.013 ;
     RECT  2.415 36.013 55.422 36.989 ;
     RECT  2.415 36.989 55.386 37.049 ;
     RECT  41.58 37.049 55.386 37.613 ;
     RECT  41.796 37.613 55.386 38.011 ;
     RECT  41.796 38.011 55.422 38.137 ;
     RECT  41.796 38.137 55.962 38.141 ;
     RECT  41.796 38.141 54.162 38.443 ;
     RECT  41.688 38.443 54.162 38.713 ;
     RECT  2.415 37.049 40.626 38.749 ;
     RECT  41.652 38.713 54.162 38.875 ;
     RECT  54.972 38.141 55.962 38.875 ;
     RECT  41.652 38.875 55.962 39.289 ;
     RECT  2.415 38.749 40.734 39.487 ;
     RECT  41.616 39.289 55.962 39.487 ;
     RECT  2.415 39.487 55.962 39.965 ;
     RECT  2.415 39.965 55.494 41.945 ;
     RECT  2.415 41.945 55.458 42.763 ;
     RECT  2.415 42.763 55.566 45.389 ;
     RECT  2.415 45.389 55.35 46.273 ;
     RECT  2.415 46.273 55.998 46.769 ;
     RECT  2.415 46.769 55.926 48.941 ;
     RECT  2.415 48.941 55.458 49.565 ;
     RECT  2.415 49.565 55.422 50.525 ;
     RECT  2.415 50.525 55.386 52.591 ;
     RECT  2.34 52.591 55.386 52.861 ;
     RECT  2.196 52.861 55.386 53.861 ;
     RECT  2.196 53.861 54.162 53.933 ;
     RECT  55.368 53.861 55.386 53.981 ;
     RECT  2.196 53.933 53.874 56.028 ;
     RECT  50.256 56.028 50.274 56.057 ;
     RECT  53.028 56.028 53.046 56.057 ;
     RECT  29.232 56.028 29.358 56.093 ;
     RECT  32.796 56.028 32.886 56.093 ;
    LAYER M4 ;
     RECT  2.293 54.96 2.329 54.984 ;
     RECT  2.329 54.672 2.408 54.984 ;
     RECT  2.408 2.148 2.512 54.984 ;
     RECT  2.512 2.418 2.704 54.984 ;
     RECT  2.704 38.4 2.819 38.424 ;
     RECT  2.704 53.616 3.02 54.984 ;
     RECT  2.704 34.896 3.025 35.928 ;
     RECT  3.02 53.616 3.107 55.32 ;
     RECT  3.025 34.896 3.593 35.64 ;
     RECT  2.704 22.224 3.601 22.248 ;
     RECT  2.704 52.08 4.021 52.104 ;
     RECT  3.107 53.616 4.213 54.984 ;
     RECT  4.213 53.568 4.789 54.984 ;
     RECT  4.789 53.568 4.997 55.32 ;
     RECT  2.704 3.648 5.108 3.672 ;
     RECT  2.704 19.584 5.108 19.608 ;
     RECT  2.704 21.12 5.108 21.144 ;
     RECT  3.593 34.896 5.108 34.92 ;
     RECT  4.405 43.872 5.108 43.896 ;
     RECT  4.021 52.08 5.108 52.296 ;
     RECT  4.997 53.568 5.108 54.984 ;
     RECT  5.108 2.148 5.212 54.984 ;
     RECT  5.212 2.418 5.404 54.984 ;
     RECT  5.404 53.568 5.555 54.984 ;
     RECT  5.404 52.176 6.517 52.2 ;
     RECT  5.555 53.616 6.649 54.984 ;
     RECT  5.404 18.96 6.829 19.512 ;
     RECT  5.404 23.28 7.477 23.304 ;
     RECT  6.517 52.176 7.477 52.44 ;
     RECT  6.649 53.568 7.477 54.984 ;
     RECT  7.141 31.776 7.525 31.8 ;
     RECT  6.829 18.96 7.621 19.608 ;
     RECT  7.117 2.544 7.808 2.568 ;
     RECT  5.404 3.648 7.808 3.672 ;
     RECT  6.661 6.816 7.808 6.84 ;
     RECT  5.404 8.784 7.808 8.808 ;
     RECT  7.369 11.232 7.808 11.256 ;
     RECT  7.621 18.72 7.808 19.608 ;
     RECT  5.404 21.12 7.808 21.144 ;
     RECT  7.477 22.464 7.808 23.304 ;
     RECT  7.669 29.76 7.808 29.784 ;
     RECT  7.525 31.104 7.808 31.8 ;
     RECT  5.404 34.896 7.808 34.92 ;
     RECT  6.709 51.072 7.808 51.096 ;
     RECT  7.477 52.176 7.808 54.984 ;
     RECT  7.808 2.148 7.912 54.984 ;
     RECT  7.912 2.418 8.104 54.984 ;
     RECT  8.104 50.736 8.425 51.096 ;
     RECT  8.104 52.176 8.641 52.488 ;
     RECT  8.104 6.816 9.385 7.656 ;
     RECT  8.104 29.232 9.445 32.328 ;
     RECT  8.104 33.552 9.445 33.576 ;
     RECT  8.104 22.464 9.637 23.304 ;
     RECT  9.385 6 9.745 7.656 ;
     RECT  9.745 5.088 9.781 7.656 ;
     RECT  8.104 8.784 9.781 8.808 ;
     RECT  8.104 26.064 9.853 26.088 ;
     RECT  9.637 22.464 10.021 23.352 ;
     RECT  8.104 2.544 10.357 2.568 ;
     RECT  9.853 25.2 10.357 26.088 ;
     RECT  10.357 2.064 10.508 2.568 ;
     RECT  8.104 3.648 10.508 3.672 ;
     RECT  9.781 5.088 10.508 8.808 ;
     RECT  8.104 11.232 10.508 11.256 ;
     RECT  8.104 18.72 10.508 19.608 ;
     RECT  8.104 21.12 10.508 21.144 ;
     RECT  10.021 22.464 10.508 23.592 ;
     RECT  10.357 25.2 10.508 26.664 ;
     RECT  9.445 29.232 10.508 33.576 ;
     RECT  8.104 34.896 10.508 34.92 ;
     RECT  8.425 51.072 10.508 51.096 ;
     RECT  8.641 52.176 10.508 52.296 ;
     RECT  8.104 53.616 10.508 54.984 ;
     RECT  10.508 2.064 10.721 54.984 ;
     RECT  10.721 2.208 10.804 54.984 ;
     RECT  10.804 53.616 11.981 54.984 ;
     RECT  10.804 28.224 12.325 28.248 ;
     RECT  10.804 29.232 12.325 33.576 ;
     RECT  10.804 25.2 12.709 26.664 ;
     RECT  11.981 53.616 13.093 54.408 ;
     RECT  10.804 2.208 13.208 2.568 ;
     RECT  10.804 3.648 13.208 3.672 ;
     RECT  10.804 6 13.208 8.808 ;
     RECT  10.804 11.232 13.208 11.256 ;
     RECT  12.661 16.368 13.208 16.392 ;
     RECT  10.804 18.72 13.208 19.512 ;
     RECT  10.804 21.12 13.208 21.144 ;
     RECT  10.804 22.464 13.208 23.592 ;
     RECT  12.709 25.2 13.208 27.192 ;
     RECT  12.325 28.224 13.208 33.576 ;
     RECT  10.804 34.896 13.208 34.92 ;
     RECT  10.804 51.072 13.208 51.096 ;
     RECT  10.804 52.176 13.208 52.44 ;
     RECT  13.093 53.616 13.208 54.456 ;
     RECT  13.208 2.148 13.285 54.456 ;
     RECT  13.285 2.148 13.312 54.696 ;
     RECT  13.312 2.208 13.504 54.696 ;
     RECT  13.504 16.368 13.601 16.536 ;
     RECT  13.504 53.616 13.909 54.696 ;
     RECT  13.909 53.616 13.997 55.32 ;
     RECT  13.504 2.208 14.821 2.568 ;
     RECT  13.601 16.512 14.821 16.536 ;
     RECT  13.504 18.72 14.821 19.512 ;
     RECT  13.504 51.072 14.821 51.096 ;
     RECT  13.504 25.152 14.861 33.576 ;
     RECT  14.821 51.072 14.861 51.192 ;
     RECT  13.504 52.176 14.861 52.44 ;
     RECT  13.997 53.616 15.061 54.456 ;
     RECT  15.068 0.144 15.155 0.168 ;
     RECT  14.821 16.368 15.205 16.536 ;
     RECT  15.061 53.616 15.253 54.696 ;
     RECT  15.205 16.368 15.445 16.824 ;
     RECT  14.821 2.064 15.908 2.568 ;
     RECT  13.504 3.648 15.908 3.672 ;
     RECT  13.504 6 15.908 8.808 ;
     RECT  13.504 11.232 15.908 11.256 ;
     RECT  15.445 16.272 15.908 16.824 ;
     RECT  14.821 18.72 15.908 19.608 ;
     RECT  13.504 21.12 15.908 21.192 ;
     RECT  13.504 22.464 15.908 23.592 ;
     RECT  14.861 25.2 15.908 33.576 ;
     RECT  13.504 34.896 15.908 34.92 ;
     RECT  14.861 51.168 15.908 51.192 ;
     RECT  14.861 52.176 15.908 52.296 ;
     RECT  15.253 53.616 15.908 55.32 ;
     RECT  15.908 2.064 16.204 55.32 ;
     RECT  16.204 53.616 16.213 55.32 ;
     RECT  16.213 53.616 16.3 55.368 ;
     RECT  16.3 53.616 16.481 55.32 ;
     RECT  16.204 18.72 17.417 19.704 ;
     RECT  16.204 16.272 17.557 17.64 ;
     RECT  17.417 18.72 17.557 19.608 ;
     RECT  16.481 53.808 17.941 55.32 ;
     RECT  17.941 53.808 18.209 55.368 ;
     RECT  16.204 21.12 18.421 21.192 ;
     RECT  16.204 22.464 18.421 23.592 ;
     RECT  17.557 16.272 18.469 19.608 ;
     RECT  16.204 2.064 18.608 2.568 ;
     RECT  16.204 3.648 18.608 3.672 ;
     RECT  16.204 6 18.608 8.808 ;
     RECT  16.204 11.232 18.608 11.256 ;
     RECT  18.469 16.272 18.608 19.8 ;
     RECT  18.421 21.12 18.608 23.592 ;
     RECT  16.204 25.2 18.608 33.576 ;
     RECT  16.204 34.896 18.608 34.92 ;
     RECT  16.204 51.168 18.608 51.192 ;
     RECT  16.204 52.176 18.608 52.296 ;
     RECT  18.209 53.808 18.608 55.32 ;
     RECT  18.608 2.064 18.821 55.32 ;
     RECT  18.821 2.208 18.904 55.32 ;
     RECT  18.904 18.144 18.965 23.592 ;
     RECT  18.904 6 20.725 8.808 ;
     RECT  18.904 53.808 21.085 55.32 ;
     RECT  18.904 2.208 21.308 2.568 ;
     RECT  18.904 3.648 21.308 3.672 ;
     RECT  20.725 6 21.308 9.336 ;
     RECT  18.904 11.232 21.308 11.256 ;
     RECT  18.904 12.864 21.308 12.888 ;
     RECT  18.904 16.272 21.308 16.824 ;
     RECT  18.965 18.72 21.308 23.592 ;
     RECT  18.904 25.2 21.308 33.576 ;
     RECT  18.904 34.896 21.308 34.92 ;
     RECT  18.904 51.168 21.308 51.192 ;
     RECT  18.904 52.176 21.308 52.44 ;
     RECT  21.085 53.616 21.308 55.32 ;
     RECT  21.308 2.148 21.412 55.32 ;
     RECT  21.412 2.208 21.604 55.32 ;
     RECT  21.604 51.072 21.731 51.192 ;
     RECT  21.604 20.928 21.809 33.576 ;
     RECT  21.809 21.12 22.169 33.576 ;
     RECT  22.169 21.12 22.601 26.808 ;
     RECT  21.604 6 22.813 9.24 ;
     RECT  21.604 18.672 22.813 19.512 ;
     RECT  21.731 51.072 22.813 51.096 ;
     RECT  22.813 51.072 22.853 51.192 ;
     RECT  21.604 52.176 22.853 52.44 ;
     RECT  22.813 18.672 22.889 19.608 ;
     RECT  21.604 2.208 22.921 2.568 ;
     RECT  21.604 3.648 22.921 3.672 ;
     RECT  22.169 27.936 22.997 33.576 ;
     RECT  21.604 53.616 23.173 55.32 ;
     RECT  21.604 11.232 23.797 11.256 ;
     RECT  21.604 13.008 23.797 13.032 ;
     RECT  22.921 2.208 23.893 3.672 ;
     RECT  23.797 13.008 23.893 13.128 ;
     RECT  23.893 2.064 24.008 3.672 ;
     RECT  22.813 6 24.008 9.336 ;
     RECT  23.797 10.848 24.008 11.256 ;
     RECT  23.893 12.864 24.008 13.128 ;
     RECT  21.604 16.272 24.008 16.824 ;
     RECT  22.889 18.72 24.008 19.608 ;
     RECT  22.601 21.12 24.008 26.712 ;
     RECT  22.997 27.936 24.008 29.784 ;
     RECT  22.997 30.768 24.008 33.576 ;
     RECT  21.604 34.896 24.008 34.92 ;
     RECT  23.749 40.416 24.008 40.44 ;
     RECT  22.853 51.168 24.008 51.192 ;
     RECT  22.853 52.176 24.008 52.296 ;
     RECT  23.173 53.616 24.008 55.368 ;
     RECT  24.008 2.064 24.304 55.368 ;
     RECT  24.304 30.816 24.365 31.128 ;
     RECT  24.304 40.416 24.365 40.44 ;
     RECT  24.365 30.816 24.467 30.888 ;
     RECT  24.467 30.864 24.473 30.888 ;
     RECT  24.304 53.568 24.545 55.368 ;
     RECT  24.304 21.12 24.581 29.256 ;
     RECT  24.304 16.272 24.617 16.824 ;
     RECT  24.581 21.12 24.653 28.536 ;
     RECT  24.545 53.568 24.761 55.32 ;
     RECT  24.617 16.272 24.797 16.392 ;
     RECT  24.761 53.616 25.337 55.32 ;
     RECT  24.304 51.168 25.409 51.192 ;
     RECT  24.304 52.176 25.553 52.296 ;
     RECT  25.477 43.872 25.861 43.896 ;
     RECT  25.553 52.176 26.245 52.2 ;
     RECT  26.053 41.568 26.581 41.592 ;
     RECT  24.304 2.064 26.708 3.672 ;
     RECT  24.304 6 26.708 9.336 ;
     RECT  24.304 11.232 26.708 11.256 ;
     RECT  24.304 12.864 26.708 12.888 ;
     RECT  24.797 16.368 26.708 16.392 ;
     RECT  24.304 18.72 26.708 19.608 ;
     RECT  24.653 21.12 26.708 23.592 ;
     RECT  24.653 25.008 26.708 28.536 ;
     RECT  24.304 34.896 26.708 34.92 ;
     RECT  26.581 41.568 26.708 42.024 ;
     RECT  25.861 43.824 26.708 43.896 ;
     RECT  24.304 49.536 26.708 49.56 ;
     RECT  26.245 51.216 26.708 52.2 ;
     RECT  25.337 53.616 26.708 54.408 ;
     RECT  26.708 2.064 27.004 54.408 ;
     RECT  27.004 50.112 27.253 52.2 ;
     RECT  27.004 42 27.389 42.024 ;
     RECT  27.004 25.2 27.425 28.536 ;
     RECT  27.253 50.112 27.713 50.712 ;
     RECT  27.713 50.112 28.217 50.136 ;
     RECT  27.004 30.144 28.573 30.168 ;
     RECT  27.253 52.176 28.597 52.2 ;
     RECT  27.004 2.064 29.408 3.672 ;
     RECT  27.004 5.472 29.408 9.336 ;
     RECT  27.004 10.656 29.408 11.256 ;
     RECT  27.004 12.864 29.408 12.888 ;
     RECT  27.004 16.368 29.408 16.392 ;
     RECT  27.004 18.72 29.408 19.608 ;
     RECT  27.004 21.12 29.408 23.592 ;
     RECT  27.425 25.2 29.408 26.088 ;
     RECT  27.425 27.072 29.408 28.536 ;
     RECT  28.573 30.096 29.408 30.168 ;
     RECT  27.004 34.896 29.408 34.92 ;
     RECT  27.004 43.344 29.408 43.896 ;
     RECT  29.221 44.976 29.408 45 ;
     RECT  28.597 51.84 29.408 52.2 ;
     RECT  27.004 53.808 29.408 54.408 ;
     RECT  29.408 2.064 29.621 54.408 ;
     RECT  29.621 2.208 29.704 54.408 ;
     RECT  29.704 29.808 29.765 30.168 ;
     RECT  29.704 16.368 29.801 16.536 ;
     RECT  29.704 43.344 30.017 44.472 ;
     RECT  30.017 43.536 30.053 44.472 ;
     RECT  29.765 29.808 30.593 30.12 ;
     RECT  29.704 31.392 30.697 31.416 ;
     RECT  30.053 43.728 30.709 44.472 ;
     RECT  29.704 51.84 30.737 52.2 ;
     RECT  29.704 2.208 30.769 3.672 ;
     RECT  29.704 5.472 30.769 9.24 ;
     RECT  29.704 18.672 30.769 19.8 ;
     RECT  30.593 29.808 30.773 30.024 ;
     RECT  29.801 16.512 30.805 16.536 ;
     RECT  29.704 12.288 30.809 13.032 ;
     RECT  30.709 43.728 30.809 44.952 ;
     RECT  30.805 16.368 30.845 16.536 ;
     RECT  30.737 52.176 30.901 52.2 ;
     RECT  30.769 18.624 30.949 19.8 ;
     RECT  29.704 53.808 31.025 54.408 ;
     RECT  30.697 31.392 31.129 32.376 ;
     RECT  30.809 44.448 31.265 44.952 ;
     RECT  31.025 53.808 31.957 54.264 ;
     RECT  30.845 16.368 32.029 16.392 ;
     RECT  30.769 2.064 32.108 3.672 ;
     RECT  30.769 5.472 32.108 9.336 ;
     RECT  29.704 10.656 32.108 11.256 ;
     RECT  30.809 12.288 32.108 12.888 ;
     RECT  32.029 15.84 32.108 16.392 ;
     RECT  30.949 18.528 32.108 19.8 ;
     RECT  29.704 21.12 32.108 23.304 ;
     RECT  29.704 25.2 32.108 28.536 ;
     RECT  31.129 31.344 32.108 32.376 ;
     RECT  31.525 33.552 32.108 33.576 ;
     RECT  29.704 34.896 32.108 34.92 ;
     RECT  31.265 44.448 32.108 45.576 ;
     RECT  30.901 52.176 32.108 52.44 ;
     RECT  31.957 53.472 32.108 54.264 ;
     RECT  32.108 2.064 32.404 54.264 ;
     RECT  32.404 52.176 32.483 54.264 ;
     RECT  32.404 21.12 32.501 23.304 ;
     RECT  32.483 52.176 32.933 53.928 ;
     RECT  32.404 44.736 32.969 46.152 ;
     RECT  32.933 53.568 33.509 53.928 ;
     RECT  32.933 52.176 33.545 52.2 ;
     RECT  32.404 18.144 33.721 19.8 ;
     RECT  32.501 21.168 33.721 23.304 ;
     RECT  32.404 33.552 33.833 33.576 ;
     RECT  33.637 55.296 33.869 55.32 ;
     RECT  32.404 15.84 34.045 17.064 ;
     RECT  33.721 18.144 34.045 23.304 ;
     RECT  32.404 12.288 34.069 13.08 ;
     RECT  32.404 34.896 34.117 34.92 ;
     RECT  34.045 15.84 34.165 23.304 ;
     RECT  32.969 45.552 34.213 46.152 ;
     RECT  34.117 33.984 34.297 34.92 ;
     RECT  34.117 14.64 34.405 14.664 ;
     RECT  34.165 15.792 34.405 23.304 ;
     RECT  33.509 53.808 34.405 53.928 ;
     RECT  34.477 31.392 34.513 31.416 ;
     RECT  34.405 53.808 34.697 54.744 ;
     RECT  32.404 2.064 34.808 3.672 ;
     RECT  32.404 5.472 34.808 9.336 ;
     RECT  32.404 10.656 34.808 11.256 ;
     RECT  34.069 12.288 34.808 13.128 ;
     RECT  34.405 14.64 34.808 23.304 ;
     RECT  32.404 25.2 34.808 28.536 ;
     RECT  34.513 31.392 34.808 31.512 ;
     RECT  34.297 33.984 34.808 34.968 ;
     RECT  34.213 45.456 34.808 46.152 ;
     RECT  34.697 53.808 34.808 54.696 ;
     RECT  34.808 2.064 35.104 54.696 ;
     RECT  35.104 53.808 35.315 54.696 ;
     RECT  35.104 34.8 35.705 34.92 ;
     RECT  35.705 34.8 35.849 34.824 ;
     RECT  35.104 46.128 36.029 46.152 ;
     RECT  35.104 47.328 36.241 47.88 ;
     RECT  35.104 5.472 36.277 11.256 ;
     RECT  35.104 12.288 36.277 13.128 ;
     RECT  35.315 53.808 36.317 53.928 ;
     RECT  35.104 25.2 36.421 28.536 ;
     RECT  35.104 14.64 36.457 23.304 ;
     RECT  36.457 14.64 36.661 23.592 ;
     RECT  36.421 24.912 36.661 28.536 ;
     RECT  36.661 14.64 36.817 28.536 ;
     RECT  36.317 53.808 36.901 53.832 ;
     RECT  36.901 53.28 37.381 53.832 ;
     RECT  35.104 2.064 37.508 3.672 ;
     RECT  36.277 5.472 37.508 13.128 ;
     RECT  36.817 14.112 37.508 28.536 ;
     RECT  35.104 36.528 37.508 36.696 ;
     RECT  36.241 47.28 37.508 47.88 ;
     RECT  37.093 51.84 37.508 51.864 ;
     RECT  37.381 53.28 37.508 54.168 ;
     RECT  37.508 2.064 37.669 54.168 ;
     RECT  37.669 2.064 37.721 54.984 ;
     RECT  37.721 2.208 37.804 54.984 ;
     RECT  37.804 36.528 37.937 36.552 ;
     RECT  37.804 53.28 38.053 54.984 ;
     RECT  37.804 37.536 38.225 37.56 ;
     RECT  37.804 51.792 38.549 51.864 ;
     RECT  38.549 51.792 38.729 51.816 ;
     RECT  37.804 2.208 38.761 3.672 ;
     RECT  37.804 47.568 38.821 47.592 ;
     RECT  37.804 31.392 38.981 31.416 ;
     RECT  37.804 5.472 39.013 28.728 ;
     RECT  38.821 47.568 39.013 48.072 ;
     RECT  39.013 5.472 39.337 29.112 ;
     RECT  39.337 5.472 39.481 29.304 ;
     RECT  39.481 5.472 40.069 30.264 ;
     RECT  39.013 47.568 40.069 48.456 ;
     RECT  38.761 2.064 40.208 3.672 ;
     RECT  40.069 5.472 40.208 30.36 ;
     RECT  37.804 38.736 40.208 38.952 ;
     RECT  40.069 47.424 40.208 49.032 ;
     RECT  38.053 53.28 40.208 55.032 ;
     RECT  40.208 2.064 40.451 55.032 ;
     RECT  40.451 2.064 40.504 53.832 ;
     RECT  40.504 48.432 40.565 49.56 ;
     RECT  40.504 32.496 40.717 32.76 ;
     RECT  40.504 2.064 41.029 3.672 ;
     RECT  40.504 5.472 41.033 31.464 ;
     RECT  41.029 1.728 41.213 3.672 ;
     RECT  40.717 32.736 41.285 32.76 ;
     RECT  40.504 51.36 41.497 51.864 ;
     RECT  40.504 53.568 41.569 53.832 ;
     RECT  40.451 54.96 41.569 55.032 ;
     RECT  41.213 2.064 41.653 3.672 ;
     RECT  41.713 33.024 41.821 33.048 ;
     RECT  41.569 37.584 41.897 37.608 ;
     RECT  40.565 48.912 41.921 49.56 ;
     RECT  41.497 51.36 41.965 52.008 ;
     RECT  41.857 46.272 42.037 46.296 ;
     RECT  40.504 47.424 42.037 47.448 ;
     RECT  42.037 46.272 42.073 47.448 ;
     RECT  41.921 48.912 42.073 50.136 ;
     RECT  41.965 51.36 42.073 52.488 ;
     RECT  41.033 5.472 42.133 30.648 ;
     RECT  42.073 48.912 42.133 52.488 ;
     RECT  42.133 48.432 42.145 52.488 ;
     RECT  41.569 53.568 42.145 55.032 ;
     RECT  42.073 46.224 42.181 47.448 ;
     RECT  42.145 48.432 42.181 55.032 ;
     RECT  42.181 46.224 42.325 55.032 ;
     RECT  42.037 35.472 42.38 35.496 ;
     RECT  42.38 35.472 42.577 35.592 ;
     RECT  42.421 36.576 42.577 36.6 ;
     RECT  40.504 41.664 42.577 42.744 ;
     RECT  42.133 5.472 42.709 31.416 ;
     RECT  41.821 33.024 42.709 33.672 ;
     RECT  42.577 40.896 42.721 42.744 ;
     RECT  42.325 45.504 42.757 55.32 ;
     RECT  42.721 40.848 42.829 42.744 ;
     RECT  42.757 45.168 42.865 55.32 ;
     RECT  42.577 35.472 42.901 36.6 ;
     RECT  41.653 2.064 42.908 3.864 ;
     RECT  42.709 5.472 42.908 31.752 ;
     RECT  42.709 33.024 42.908 34.152 ;
     RECT  42.901 35.472 42.908 36.84 ;
     RECT  42.541 39.84 42.908 39.864 ;
     RECT  42.829 40.848 42.908 43.128 ;
     RECT  42.865 44.448 42.908 55.32 ;
     RECT  42.908 2.064 42.947 55.32 ;
     RECT  42.947 2.064 43.204 54.264 ;
     RECT  43.204 33.888 43.331 37.128 ;
     RECT  42.947 55.296 43.331 55.32 ;
     RECT  43.204 38.784 44.005 54.264 ;
     RECT  44.005 38.784 44.197 54.648 ;
     RECT  43.331 35.568 44.233 37.128 ;
     RECT  44.233 35.568 44.413 37.224 ;
     RECT  43.331 33.888 44.437 34.248 ;
     RECT  44.413 35.52 44.437 37.224 ;
     RECT  44.197 38.688 44.437 54.648 ;
     RECT  43.204 4.944 44.485 32.856 ;
     RECT  44.437 33.888 44.485 37.224 ;
     RECT  44.437 38.688 44.485 54.744 ;
     RECT  44.485 38.688 44.521 55.32 ;
     RECT  44.485 4.944 44.881 37.224 ;
     RECT  44.521 38.256 44.881 55.32 ;
     RECT  43.204 2.064 45.608 3.864 ;
     RECT  44.881 4.944 45.608 55.32 ;
     RECT  45.608 2.064 46.249 55.32 ;
     RECT  46.249 2.064 46.597 55.368 ;
     RECT  46.597 2.064 46.739 55.944 ;
     RECT  46.739 2.064 47.905 55.368 ;
     RECT  47.905 1.968 49.025 55.368 ;
     RECT  49.025 2.064 50.713 55.368 ;
     RECT  50.713 2.064 52.841 55.416 ;
     RECT  52.841 2.148 52.913 55.416 ;
     RECT  52.913 2.148 53.219 55.032 ;
     RECT  53.219 2.148 53.603 54.984 ;
     RECT  53.603 2.148 53.812 54.744 ;
     RECT  53.812 2.208 53.987 54.744 ;
     RECT  53.987 2.208 55.357 53.88 ;
     RECT  55.357 2.208 55.98 53.976 ;
     RECT  55.98 22.272 56.045 22.296 ;
    LAYER M5 ;
     RECT  41.04 0.144 41.064 1.763 ;
     RECT  10.368 2.053 10.392 2.137 ;
     RECT  15.12 0.133 15.144 2.137 ;
     RECT  23.904 2.053 23.928 2.137 ;
     RECT  50.688 2.053 50.712 2.137 ;
     RECT  2.4 2.137 2.52 2.151 ;
     RECT  5.1 2.137 5.22 2.151 ;
     RECT  7.8 2.137 7.92 2.151 ;
     RECT  10.368 2.137 10.62 2.151 ;
     RECT  13.2 2.137 13.32 2.151 ;
     RECT  15.12 2.137 16.02 2.151 ;
     RECT  18.6 2.137 18.72 2.151 ;
     RECT  21.3 2.137 21.42 2.151 ;
     RECT  23.904 2.137 24.12 2.151 ;
     RECT  26.7 2.137 26.82 2.151 ;
     RECT  29.4 2.137 29.52 2.151 ;
     RECT  32.1 2.137 32.22 2.151 ;
     RECT  34.8 2.137 34.92 2.151 ;
     RECT  37.5 2.137 37.62 2.151 ;
     RECT  42.9 2.137 43.02 2.151 ;
     RECT  45.6 2.137 45.72 2.151 ;
     RECT  48.3 2.137 48.42 2.151 ;
     RECT  50.688 2.137 51.12 2.151 ;
     RECT  53.7 2.137 53.82 2.151 ;
     RECT  48.3 2.151 48.612 2.197 ;
     RECT  23.904 2.151 24.312 2.243 ;
     RECT  45.6 2.151 45.912 2.533 ;
     RECT  47.808 2.197 49.464 2.917 ;
     RECT  50.688 2.151 51.312 2.917 ;
     RECT  47.808 2.917 51.312 3.205 ;
     RECT  45.504 2.533 45.912 3.443 ;
     RECT  2.4 2.151 2.712 3.637 ;
     RECT  41.664 3.205 41.688 3.875 ;
     RECT  45.6 3.443 45.912 3.925 ;
     RECT  47.808 3.205 51.864 4.019 ;
     RECT  45.6 3.925 46.488 4.453 ;
     RECT  47.808 4.019 51.48 4.453 ;
     RECT  10.368 2.151 10.812 5.077 ;
     RECT  26.7 2.151 27.012 5.461 ;
     RECT  7.8 2.151 8.112 7.621 ;
     RECT  37.5 2.151 37.812 7.621 ;
     RECT  24 2.243 24.312 7.717 ;
     RECT  45.6 4.453 51.48 7.813 ;
     RECT  44.592 6.085 44.616 7.861 ;
     RECT  45.6 7.813 52.392 7.861 ;
     RECT  53.7 2.151 54.012 7.861 ;
     RECT  44.592 7.861 52.392 7.909 ;
     RECT  30.816 7.621 30.84 7.955 ;
     RECT  37.5 7.621 38.808 7.955 ;
     RECT  9.792 5.077 10.812 8.051 ;
     RECT  18.6 2.151 18.912 8.245 ;
     RECT  23.904 7.717 24.312 8.485 ;
     RECT  44.592 7.909 52.44 8.579 ;
     RECT  45.408 8.579 52.44 8.771 ;
     RECT  45.408 8.771 52.392 9.011 ;
     RECT  53.52 7.861 54.012 9.155 ;
     RECT  53.7 9.155 54.012 9.349 ;
     RECT  53.7 9.349 54.696 9.587 ;
     RECT  34.8 2.151 35.112 9.781 ;
     RECT  36.24 9.061 36.264 9.781 ;
     RECT  34.8 9.781 36.264 10.117 ;
     RECT  37.5 7.955 37.812 10.117 ;
     RECT  45.6 9.011 52.392 10.453 ;
     RECT  45.6 10.453 52.728 10.501 ;
     RECT  53.7 9.587 54.012 10.501 ;
     RECT  23.904 8.485 24.456 10.837 ;
     RECT  45.6 10.501 54.012 10.931 ;
     RECT  34.8 10.117 37.812 10.933 ;
     RECT  52.8 10.931 54.012 12.277 ;
     RECT  45.6 10.931 51.312 12.421 ;
     RECT  45.6 12.421 51.432 12.469 ;
     RECT  52.416 12.277 54.012 12.469 ;
     RECT  18.6 8.245 19.032 12.853 ;
     RECT  34.176 10.933 37.812 13.093 ;
     RECT  23.808 10.837 24.456 13.139 ;
     RECT  34.08 13.093 37.812 13.573 ;
     RECT  45.6 12.469 54.012 15.443 ;
     RECT  53.568 15.443 54.012 15.493 ;
     RECT  53.568 15.493 54.696 15.779 ;
     RECT  45.6 15.443 52.44 16.211 ;
     RECT  22.8 16.261 22.824 16.403 ;
     RECT  45.6 16.211 51.96 16.643 ;
     RECT  45.6 16.643 51.72 16.645 ;
     RECT  34.08 13.573 38.52 16.691 ;
     RECT  53.568 15.779 54.012 16.789 ;
     RECT  15.12 2.151 16.212 16.981 ;
     RECT  52.992 16.789 54.012 17.413 ;
     RECT  52.944 17.413 54.012 17.461 ;
     RECT  15.12 16.981 16.44 17.605 ;
     RECT  45.024 16.645 51.72 17.605 ;
     RECT  34.176 16.691 38.52 17.747 ;
     RECT  45.024 17.605 51.864 17.795 ;
     RECT  15.12 17.605 16.824 18.181 ;
     RECT  6.672 6.805 6.696 18.709 ;
     RECT  7.8 7.621 8.616 18.709 ;
     RECT  15.12 18.181 17.592 18.757 ;
     RECT  18.6 12.853 19.368 18.757 ;
     RECT  26.7 5.461 27.624 18.851 ;
     RECT  52.848 17.461 54.012 18.851 ;
     RECT  45.6 17.795 51.864 19.093 ;
     RECT  34.176 17.747 38.184 19.427 ;
     RECT  34.176 19.427 37.812 20.003 ;
     RECT  45.6 19.093 52.44 20.003 ;
     RECT  15.12 18.757 19.368 20.005 ;
     RECT  15.12 20.005 19.512 20.341 ;
     RECT  53.7 18.851 54.012 21.061 ;
     RECT  34.176 20.003 36.312 21.155 ;
     RECT  13.2 2.151 13.512 21.157 ;
     RECT  15.12 20.341 20.328 21.157 ;
     RECT  45.6 20.003 52.152 21.301 ;
     RECT  53.136 21.061 54.012 21.301 ;
     RECT  30.864 21.397 30.888 21.539 ;
     RECT  13.2 21.157 20.328 21.589 ;
     RECT  21.3 2.151 21.612 21.589 ;
     RECT  34.176 21.155 35.88 21.683 ;
     RECT  37.5 20.003 37.812 22.165 ;
     RECT  2.4 3.637 3.576 22.259 ;
     RECT  45.6 21.301 54.012 22.355 ;
     RECT  13.2 21.589 21.612 22.549 ;
     RECT  5.1 2.151 5.412 23.269 ;
     RECT  10.5 8.051 10.812 23.317 ;
     RECT  45.6 22.355 47.064 23.605 ;
     RECT  48.096 22.355 54.012 23.605 ;
     RECT  36.672 22.165 37.812 23.797 ;
     RECT  36.672 23.797 38.136 24.227 ;
     RECT  45.6 23.605 54.012 24.563 ;
     RECT  37.5 24.227 38.136 24.757 ;
     RECT  13.2 22.549 22.248 25.045 ;
     RECT  45.6 24.563 52.488 25.715 ;
     RECT  23.904 13.139 24.456 26.197 ;
     RECT  45.6 25.715 46.488 26.293 ;
     RECT  40.2 2.137 40.512 27.061 ;
     RECT  47.568 25.715 52.488 27.061 ;
     RECT  53.7 24.563 54.012 27.061 ;
     RECT  13.2 25.045 22.44 27.157 ;
     RECT  37.5 24.757 38.184 27.253 ;
     RECT  39.312 27.061 40.512 27.253 ;
     RECT  26.7 18.851 27.012 27.301 ;
     RECT  45.456 26.293 46.488 27.301 ;
     RECT  47.568 27.061 54.012 27.301 ;
     RECT  45.456 27.301 54.012 27.971 ;
     RECT  9.648 23.317 10.812 28.213 ;
     RECT  37.5 27.253 40.512 28.595 ;
     RECT  9.648 28.213 11.592 28.933 ;
     RECT  12.72 27.157 22.44 28.933 ;
     RECT  39.312 28.595 40.512 28.933 ;
     RECT  39.312 28.933 41.016 29.123 ;
     RECT  6.672 18.709 8.616 29.221 ;
     RECT  9.648 28.933 22.44 29.221 ;
     RECT  53.7 27.971 54.012 29.221 ;
     RECT  53.7 29.221 54.12 29.507 ;
     RECT  45.456 27.971 52.44 29.699 ;
     RECT  45.456 29.699 52.392 30.035 ;
     RECT  39.84 29.123 41.016 30.083 ;
     RECT  39.888 30.083 41.016 30.275 ;
     RECT  50.544 30.035 52.392 30.275 ;
     RECT  40.08 30.275 41.016 30.371 ;
     RECT  45.456 30.035 49.56 30.611 ;
     RECT  53.7 29.507 54.012 30.757 ;
     RECT  53.7 30.757 54.744 30.947 ;
     RECT  55.872 30.757 55.896 30.947 ;
     RECT  45.6 30.611 49.56 31.093 ;
     RECT  50.544 30.275 51.912 31.093 ;
     RECT  40.2 30.371 41.016 31.379 ;
     RECT  42.9 2.151 43.212 31.381 ;
     RECT  40.2 31.379 40.968 31.475 ;
     RECT  23.904 26.197 25.128 31.955 ;
     RECT  53.7 30.947 54.012 32.293 ;
     RECT  40.2 31.475 40.68 32.531 ;
     RECT  45.6 31.093 51.912 32.579 ;
     RECT  42.144 31.381 43.212 32.821 ;
     RECT  42.144 32.821 43.32 33.013 ;
     RECT  45.6 32.579 51.864 33.781 ;
     RECT  45.264 33.781 51.864 33.925 ;
     RECT  52.992 32.293 54.012 33.925 ;
     RECT  45.264 33.925 54.012 34.069 ;
     RECT  2.4 22.259 3 34.885 ;
     RECT  44.976 34.069 54.012 34.931 ;
     RECT  44.976 34.931 52.44 35.173 ;
     RECT  42.048 33.013 43.32 35.507 ;
     RECT  42.432 35.507 43.32 35.797 ;
     RECT  44.448 35.173 52.44 35.797 ;
     RECT  42.432 35.797 52.44 35.941 ;
     RECT  53.7 34.931 54.012 35.941 ;
     RECT  42.432 35.941 54.012 36.037 ;
     RECT  42.432 36.037 54.696 36.275 ;
     RECT  42.432 36.275 54.012 36.611 ;
     RECT  42.9 36.611 54.012 37.043 ;
     RECT  42.9 37.043 52.44 37.475 ;
     RECT  42.9 37.475 52.392 38.819 ;
     RECT  53.7 37.043 54.012 38.965 ;
     RECT  53.7 38.965 54.696 39.107 ;
     RECT  44.928 38.819 52.392 39.395 ;
     RECT  44.976 39.395 52.392 39.587 ;
     RECT  44.976 39.587 51.96 39.923 ;
     RECT  24 31.955 25.128 40.405 ;
     RECT  45.024 39.923 51.96 40.981 ;
     RECT  44.448 40.981 51.96 41.461 ;
     RECT  23.76 40.405 25.128 41.557 ;
     RECT  26.7 27.301 27.24 41.557 ;
     RECT  44.448 41.461 52.056 41.747 ;
     RECT  45.024 41.747 51.96 41.795 ;
     RECT  45.024 41.795 51.528 42.851 ;
     RECT  53.7 39.107 54.012 42.853 ;
     RECT  52.992 42.853 54.012 42.995 ;
     RECT  45.024 42.851 51.432 43.285 ;
     RECT  29.4 2.151 29.712 43.333 ;
     RECT  28.224 43.333 29.712 43.717 ;
     RECT  2.4 34.885 3.48 43.861 ;
     RECT  5.1 23.269 5.544 43.861 ;
     RECT  23.76 41.557 27.24 43.861 ;
     RECT  28.224 43.717 29.976 43.861 ;
     RECT  44.688 43.285 51.432 44.293 ;
     RECT  23.76 43.861 30.168 44.437 ;
     RECT  53.472 42.995 54.012 44.483 ;
     RECT  42.9 38.819 43.212 44.533 ;
     RECT  44.688 44.293 51.528 44.533 ;
     RECT  23.76 44.437 31.128 44.725 ;
     RECT  32.1 2.151 32.412 44.725 ;
     RECT  42.9 44.533 51.528 44.773 ;
     RECT  42.9 44.773 51.576 45.109 ;
     RECT  42.9 45.109 51.816 45.157 ;
     RECT  34.8 21.683 35.112 45.445 ;
     RECT  42.768 45.157 51.816 45.493 ;
     RECT  23.76 44.725 32.412 45.541 ;
     RECT  34.224 45.445 35.112 45.541 ;
     RECT  42.336 45.493 51.816 46.069 ;
     RECT  23.76 45.541 35.112 46.117 ;
     RECT  42.336 46.069 51.912 46.787 ;
     RECT  42.768 46.787 51.912 46.883 ;
     RECT  42.9 46.883 51.912 47.029 ;
     RECT  23.76 46.117 35.4 47.317 ;
     RECT  37.5 28.595 37.812 47.317 ;
     RECT  40.2 32.531 40.512 47.413 ;
     RECT  42.9 47.029 52.056 47.461 ;
     RECT  42.9 47.461 52.152 47.555 ;
     RECT  38.832 48.037 38.856 48.229 ;
     RECT  40.08 47.413 40.512 48.229 ;
     RECT  42.9 47.555 49.176 48.421 ;
     RECT  50.256 47.555 52.152 48.515 ;
     RECT  50.736 48.515 52.056 48.899 ;
     RECT  38.832 48.229 40.512 48.901 ;
     RECT  42.144 48.421 49.176 48.901 ;
     RECT  38.832 48.901 49.176 49.093 ;
     RECT  38.832 49.093 49.752 50.101 ;
     RECT  50.736 48.899 51.72 50.101 ;
     RECT  38.832 50.101 51.72 50.293 ;
     RECT  38.832 50.293 52.44 51.107 ;
     RECT  50.208 51.107 52.44 51.157 ;
     RECT  38.832 51.107 49.032 51.587 ;
     RECT  50.208 51.157 52.632 51.683 ;
     RECT  23.76 47.317 37.812 51.781 ;
     RECT  38.832 51.587 48.792 51.781 ;
     RECT  2.4 43.861 5.544 52.165 ;
     RECT  6.672 29.221 22.44 52.165 ;
     RECT  50.592 51.683 52.632 52.741 ;
     RECT  53.7 44.483 54.012 52.741 ;
     RECT  23.76 51.781 48.792 53.125 ;
     RECT  23.76 53.125 48.936 53.221 ;
     RECT  50.592 52.741 54.012 53.221 ;
     RECT  23.76 53.221 54.012 54.009 ;
     RECT  2.4 52.165 22.44 54.949 ;
     RECT  2.304 54.949 22.44 55.285 ;
     RECT  23.76 54.009 53.976 55.285 ;
     RECT  2.304 55.285 53.976 56.016 ;
  END
END dsfd_rly_536_EN
END LIBRARY
